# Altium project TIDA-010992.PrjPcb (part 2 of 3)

## Sheet TIDA-010992_04_BOOT_SoC power_CLK.SchDoc
size 431 x 279 mm; Date: Not shown in title block; ApprovedBy: Not shown in title block; CheckedBy: Not shown in title block; Author: Not shown in title block; CompanyName: Not shown in title block; Engineer: Not shown in title block; Organization: Not shown in title block; Address1: Not shown in title block; Address2: Not shown in title block; Address3: Not shown in title block; Address4: Not shown in title block; DocumentNumber: 4; Revision: Use project parameter SCH_Rev; SheetNumber: 4; SheetTotal: 13; PageSetup: Record=PageOptions¦CenterHorizontal=True¦CenterVertical=True¦PrintScale=1.00¦XCorrection=1.00¦YCorrection=1.00¦PrintKind=0¦BorderSize=5000000¦LeftOffset=0¦BottomOffset=0¦Orientation=2¦PaperLength=1000¦PaperWidth=1000¦Scale=100¦PaperSource=15¦PrintQuality=600¦MediaType=1¦DitherType=10¦PaperKind=Letter¦PrintScaleMode=1

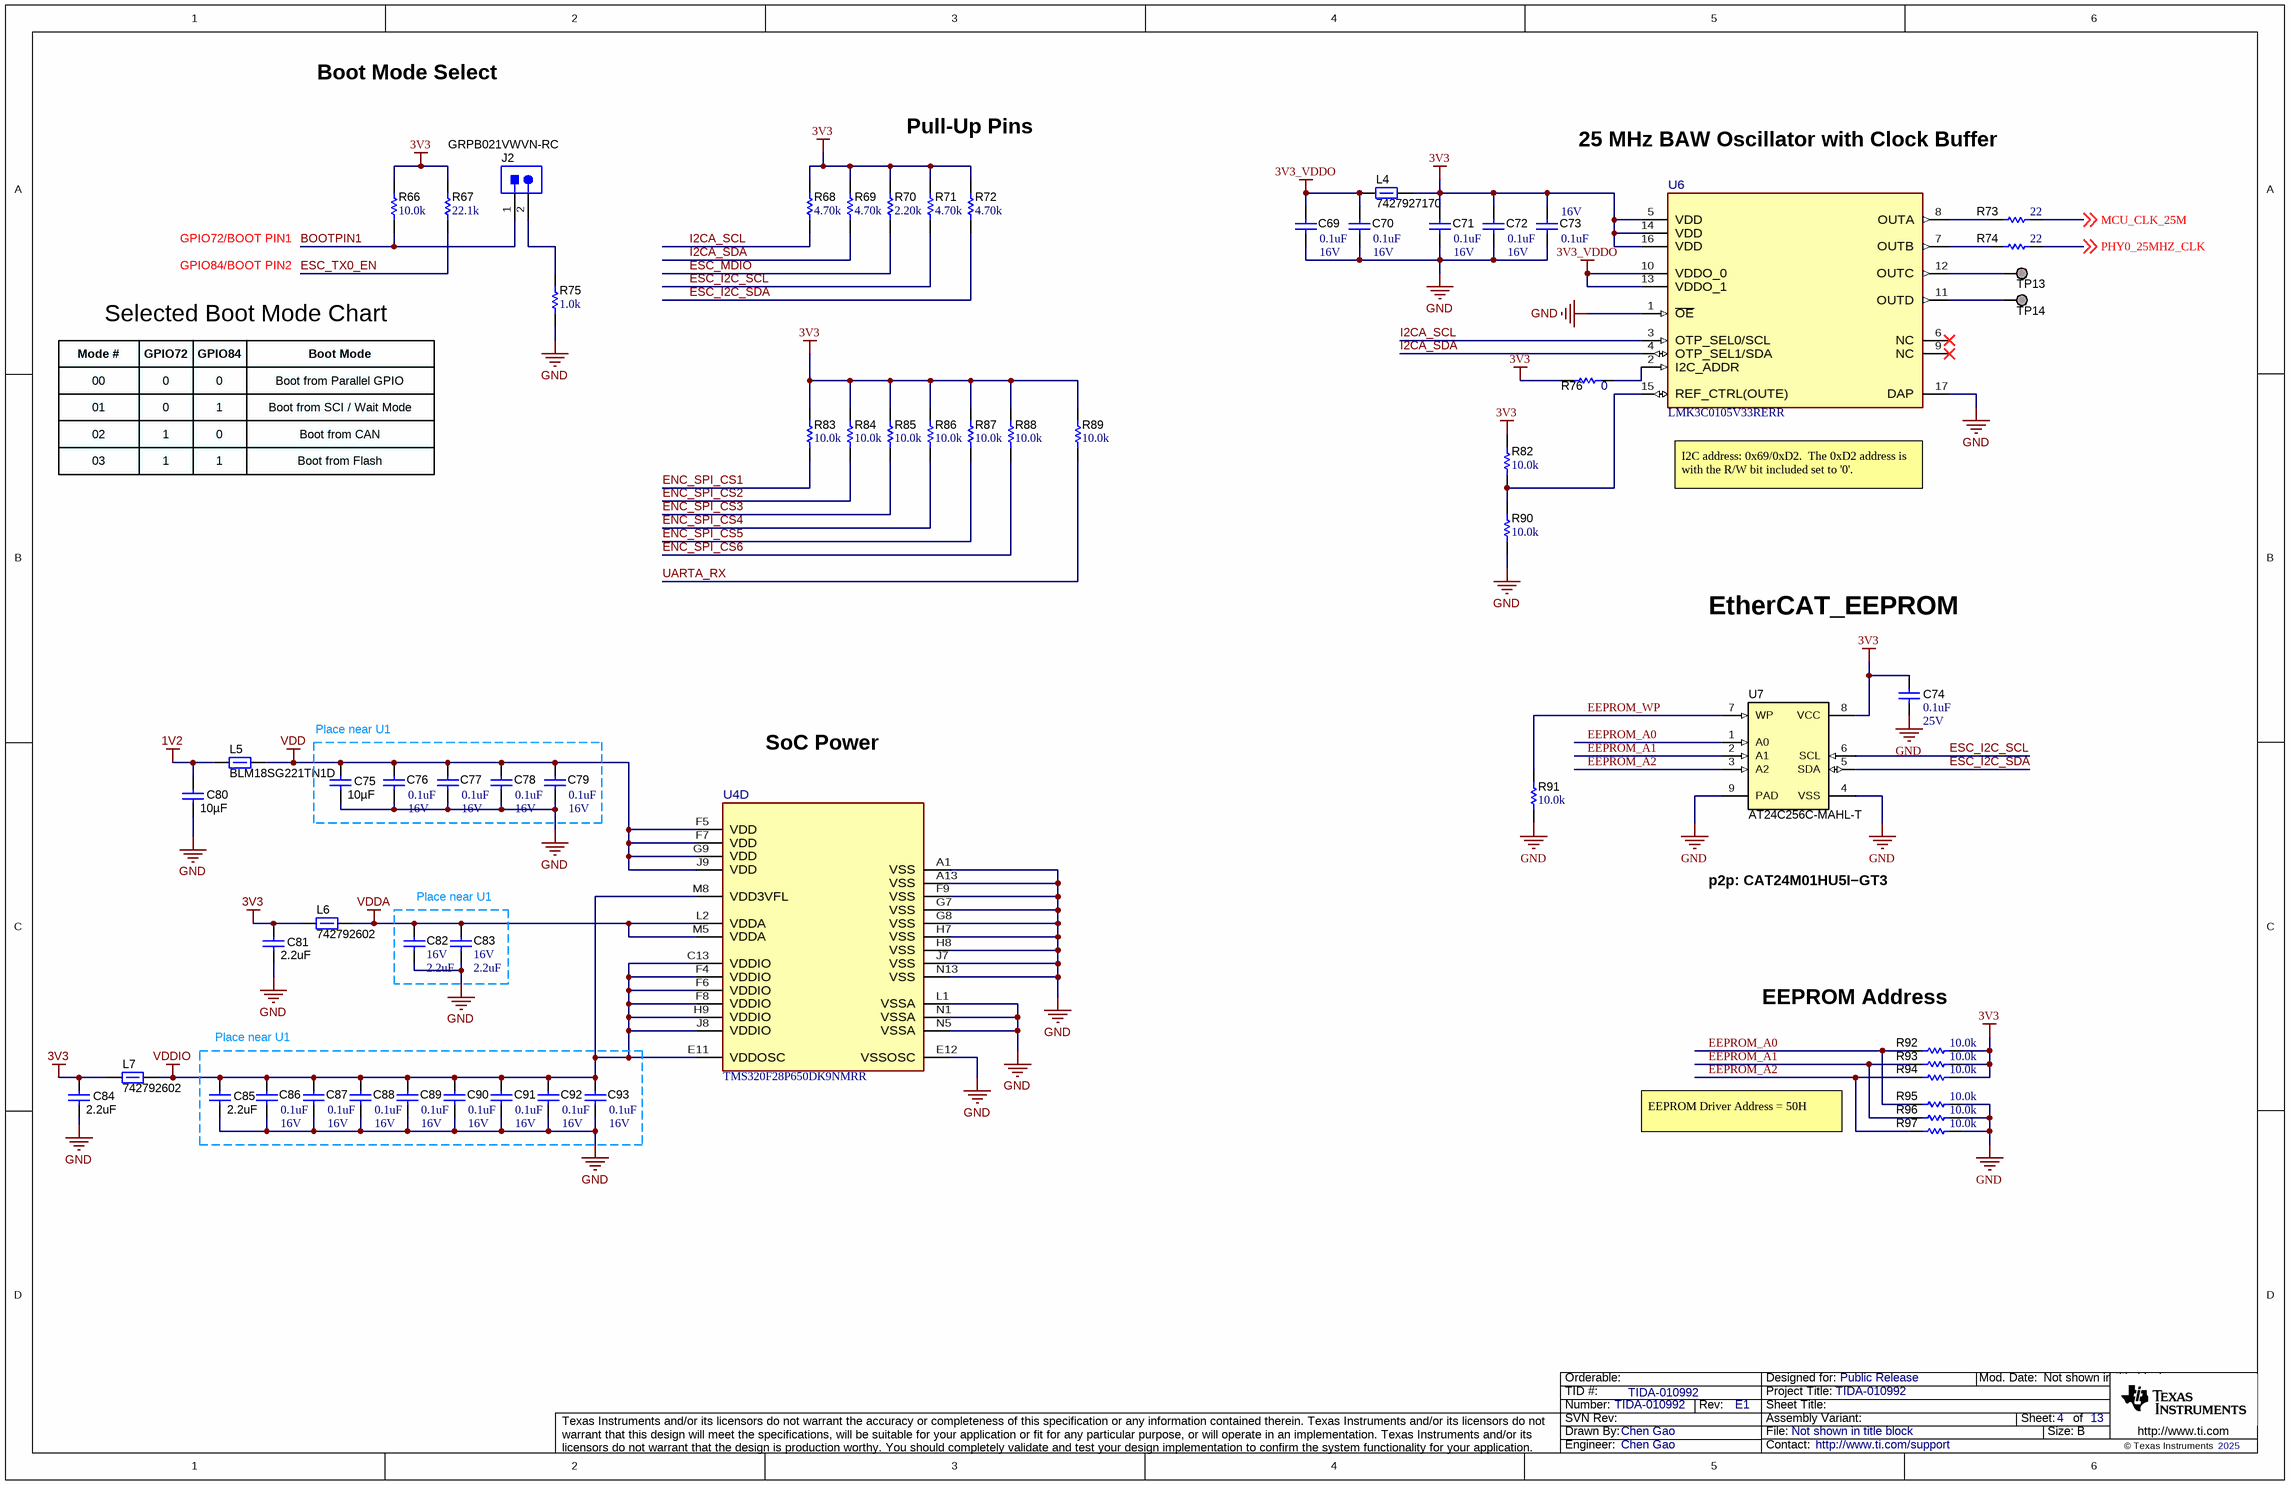
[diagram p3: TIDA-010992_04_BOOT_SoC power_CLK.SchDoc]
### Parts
C69  VDC_V: 16V  ValueDisplayed: 0.1uF  [0201]  (hidden comment: GRM033Z71C104KE14D)
C70  VDC_V: 16V  ValueDisplayed: 0.1uF  [0201]  (hidden comment: GRM033Z71C104KE14D)
C71  VDC_V: 16V  ValueDisplayed: 0.1uF  [0201]  (hidden comment: GRM033Z71C104KE14D)
C72  VDC_V: 16V  ValueDisplayed: 0.1uF  [0201]  (hidden comment: GRM033Z71C104KE14D)
C73  VDC_V: 16V  ValueDisplayed: 0.1uF  [0201]  (hidden comment: GRM033Z71C104KE14D)
C74  Value2: 25V  ValueDisplayed: 0.1uF  [0402]  (hidden comment: GRM155R71E104KE14D)
C75  ValueDisplayed: 10µF  [0603]  (hidden comment: GRM188R61C106KAALD)
C76  VDC_V: 16V  ValueDisplayed: 0.1uF  [0201]  (hidden comment: GRM033Z71C104KE14D)
C77  VDC_V: 16V  ValueDisplayed: 0.1uF  [0201]  (hidden comment: GRM033Z71C104KE14D)
C78  VDC_V: 16V  ValueDisplayed: 0.1uF  [0201]  (hidden comment: GRM033Z71C104KE14D)
C79  VDC_V: 16V  ValueDisplayed: 0.1uF  [0201]  (hidden comment: GRM033Z71C104KE14D)
C80  ValueDisplayed: 10µF  [0603]  (hidden comment: GRM188R61C106KAALD)
C81  ValueDisplayed: 2.2uF  [0603]  (hidden comment: 885012106018)
C82  VDC_V: 16V  ValueDisplayed: 2.2uF  [0402]  (hidden comment: GRM155R61C225KE11D)
C83  VDC_V: 16V  ValueDisplayed: 2.2uF  [0402]  (hidden comment: GRM155R61C225KE11D)
C84  ValueDisplayed: 2.2uF  [0603]  (hidden comment: 885012106018)
C85  ValueDisplayed: 2.2uF  [0603]  (hidden comment: 885012106018)
C86  VDC_V: 16V  ValueDisplayed: 0.1uF  [0201]  (hidden comment: GRM033Z71C104KE14D)
C87  VDC_V: 16V  ValueDisplayed: 0.1uF  [0201]  (hidden comment: GRM033Z71C104KE14D)
C88  VDC_V: 16V  ValueDisplayed: 0.1uF  [0201]  (hidden comment: GRM033Z71C104KE14D)
C89  VDC_V: 16V  ValueDisplayed: 0.1uF  [0201]  (hidden comment: GRM033Z71C104KE14D)
C90  VDC_V: 16V  ValueDisplayed: 0.1uF  [0201]  (hidden comment: GRM033Z71C104KE14D)
C91  VDC_V: 16V  ValueDisplayed: 0.1uF  [0201]  (hidden comment: GRM033Z71C104KE14D)
C92  VDC_V: 16V  ValueDisplayed: 0.1uF  [0201]  (hidden comment: GRM033Z71C104KE14D)
C93  VDC_V: 16V  ValueDisplayed: 0.1uF  [0201]  (hidden comment: GRM033Z71C104KE14D)
J2  GRPB021VWVN-RC  [Sullins_GRPB021VWVN-RC]
L4  7427927170  [0402]
L5  BLM18SG221TN1D  [0603]
L6  742792602  [0603]
L7  742792602  [0603]
R66  ValueDisplayed: 10.0k  [0402]  (hidden comment: ERJ-2RKF1002X)
R67  ValueDisplayed: 22.1k  [0402]  (hidden comment: CRCW040222K1FKED)
R68  ValueDisplayed: 4.70k  [0201]  (hidden comment: RC0201FR-7D4K7L)
R69  ValueDisplayed: 4.70k  [0201]  (hidden comment: RC0201FR-7D4K7L)
R70  ValueDisplayed: 2.20k  [0201]  (hidden comment: RC0201FR-072K2L)
R71  ValueDisplayed: 4.70k  [0201]  (hidden comment: RC0201FR-7D4K7L)
R72  ValueDisplayed: 4.70k  [0201]  (hidden comment: RC0201FR-7D4K7L)
R73  ValueDisplayed: 22  [0402L]  (hidden comment: CRCW040222R0JNED)
R74  ValueDisplayed: 22  [0402L]  (hidden comment: CRCW040222R0JNED)
R75  ValueDisplayed: 1.0k  [0402]  (hidden comment: ERJ-2GEJ102X)
R76  ValueDisplayed: 0  [0402]  (hidden comment: CRCW04020000Z0EDHP)
R82  ValueDisplayed: 10.0k  [0201]  (hidden comment: RC0201FS-7D10KL)
R83  ValueDisplayed: 10.0k  [0201]  (hidden comment: RC0201FS-7D10KL)
R84  ValueDisplayed: 10.0k  [0201]  (hidden comment: RC0201FS-7D10KL)
R85  ValueDisplayed: 10.0k  [0201]  (hidden comment: RC0201FS-7D10KL)
R86  ValueDisplayed: 10.0k  [0201]  (hidden comment: RC0201FS-7D10KL)
R87  ValueDisplayed: 10.0k  [0201]  (hidden comment: RC0201FS-7D10KL)
R88  ValueDisplayed: 10.0k  [0201]  (hidden comment: RC0201FS-7D10KL)
R89  ValueDisplayed: 10.0k  [0201]  (hidden comment: RC0201FS-7D10KL)
R90  ValueDisplayed: 10.0k  [0201]  (hidden comment: RC0201FS-7D10KL)
R91  ValueDisplayed: 10.0k  [0402]  (hidden comment: ERJ-2RKF1002X)
R92  ValueDisplayed: 10.0k  [0402]  (hidden comment: ERJ-2RKF1002X)
R93  ValueDisplayed: 10.0k  [0402]  (hidden comment: ERJ-2RKF1002X)
R94  ValueDisplayed: 10.0k  [0402]  (hidden comment: ERJ-2RKF1002X)
R95  ValueDisplayed: 10.0k  [0402]  (hidden comment: ERJ-2RKF1002X)
R96  ValueDisplayed: 10.0k  [0402]  (hidden comment: ERJ-2RKF1002X)
R97  ValueDisplayed: 10.0k  [0402]  (hidden comment: ERJ-2RKF1002X)
TP13  TP_SM_1MM  [TP_SM_1MM]  (value not drawn)  (no BOM)
TP14  TP_SM_1MM  [TP_SM_1MM]  (value not drawn)  (no BOM)
U4  TMS320F28P650DK9NMRR  [NMR0169A-MFG]  (part D of 4)
U6  LMK3C0105V33RERR  [RER0016A-MFG]
U7  AT24C256C-MAHL-T  [8MA2]

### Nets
1V2: C80.1 L5.1
3V3: C71.1 C72.1 C73.1 C74.2 C81.1 C84.1 L4.1 L6.1 L7.1 R66.1 R67.2 R68.2 R69.2 R70.2 R71.2 R72.2 R76.1 R82.2 R83.2 R84.2 R85.2 R86.2 R87.2 R88.2 R89.2 R92.1 R93.1 R94.1 U6.5(VDD) U6.14(VDD) U6.16(VDD) U7.8(VCC)
3V3_VDDO: C69.1 C70.1 L4.2 U6.10(VDDO_0) U6.13(VDDO_1)
GND: C69.2 C70.2 C71.2 C72.2 C73.2 C74.1 C75.2 C76.2 C77.2 C78.2 C79.2 C80.2 C81.2 C82.2 C83.2 C84.2 C85.2 C86.2 C87.2 C88.2 C89.2 C90.2 C91.2 C92.2 C93.2 R75.1 R90.1 R91.2 R95.1 R96.1 R97.1 U4.A1(VSS) U4.A13(VSS) U4.E12(VSSOSC) U4.F9(VSS) U4.G7(VSS) U4.G8(VSS) U4.H7(VSS) U4.H8(VSS) U4.J7(VSS) U4.L1(VSSA) U4.N1(VSSA) U4.N5(VSSA) U4.N13(VSS) U6.1(~{OE}) U6.17(DAP) U7.4(VSS) U7.9(PAD)
VDD: C75.1 C76.1 C77.1 C78.1 C79.1 L5.2 U4.F5(VDD) U4.F7(VDD) U4.G9(VDD) U4.J9(VDD)
VDDA: C82.1 C83.1 L6.2 U4.L2(VDDA) U4.M5(VDDA)
VDDIO: C85.1 C86.1 C87.1 C88.1 C89.1 C90.1 C91.1 C92.1 C93.1 L7.2 U4.C13(VDDIO) U4.E11(VDDOSC) U4.F4(VDDIO) U4.F6(VDDIO) U4.F8(VDDIO) U4.H9(VDDIO) U4.J8(VDDIO) U4.M8(VDD3VFL)
BOOTPIN1: J2.1 R66.2
EEPROM_A0: R92.2 R95.2 U7.1(A0)
EEPROM_A1: R93.2 R96.2 U7.2(A1)
EEPROM_A2: R94.2 R97.2 U7.3(A2)
EEPROM_WP: R91.1 U7.7(WP)
ENC_SPI_CS1: R83.1
ENC_SPI_CS2: R84.1
ENC_SPI_CS3: R85.1
ENC_SPI_CS4: R86.1
ENC_SPI_CS5: R87.1
ENC_SPI_CS6: R88.1
ESC_I2C_SCL: R71.1 U7.6(SCL)
ESC_I2C_SDA: R72.1 U7.5(SDA)
ESC_MDIO: R70.1
ESC_TX0_EN: R67.1
I2CA_SCL: R68.1 U6.3(OTP_SEL0/SCL)
I2CA_SDA: R69.1 U6.4(OTP_SEL1/SDA)
MCU_CLK_25M: R73.2 ; off-sheet MCU_CLK_25M
PHY0_25MHZ_CLK: R74.2 ; off-sheet PHY0_25MHZ_CLK
UARTA_RX: R89.1
NetJ2_2: J2.2 R75.2
NetR73_1: R73.1 U6.8(OUTA)
NetR74_1: R74.1 U6.7(OUTB)
NetR76_2: R76.2 U6.2(I2C_ADDR)
NetR82_1: R82.1 R90.2 U6.15(REF_CTRL(OUTE))
NetTP13_1: TP13.1 U6.12(OUTC)
NetTP14_1: TP14.1 U6.11(OUTD)

Not connected (* = marked no-connect by the designer): U6 6(NC)* 9(NC)*

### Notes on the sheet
- Boot Mode Select
- Pull-Up Pins
- 25 MHz BAW Oscillator with Clock Buffer
- GPIO72/BOOT PIN1
- GPIO84/BOOT PIN2
- Mode #
- GPIO72
- GPIO84
- Selected Boot Mode Chart
- Boot Mode
- 00
- 01
- 02
- 0
- 1
- Boot from Parallel GPIO
- Boot from SCI / Wait Mode
- Boot from CAN
- 03
- Boot from Flash
- (near U6) I2C address: 0x69/0xD2.  The 0xD2 address is with the R/W bit included set to '0'.
- EtherCAT_EEPROM
- Place near U1
- SoC Power
- p2p: CAT24M01HU5I−GT3
- EEPROM Address
- EEPROM Driver Address = 50H

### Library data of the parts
C69-C73 C76-C79 C86-C93 = CMP-0064970-1: CAP, CERM, 0.1 uF, 16 V,+/- 10%, X7R, 0201; Manufacturer: MuRata; TaMin_C: -55°C; Polarized: N; SizeAreaWB_mm2: 2.08; Value1: Unknown; U/M: EA; Value: 0.1uF; TaMax_C: 125°C; SizeZ_mm: 0.26; SizeX_mm: 0.6; SizeY_mm: 0.3; SizeArea_mm2: 0.18; Cap_F: 100nF; AEC Category: Q200
C74 = CMP-0006659-2: CAP, CERM, 0.1 uF, 25 V, +/- 10%, X7R, 0402; Manufacturer: MuRata; TaMin_C: -55°C; Polarized: N; SizeAreaWB_mm2: 3; U/M: EA; Value: 0.1uF; TaMax_C: 125°C; SizeZ_mm: 0.6; SizeX_mm: 1; SizeY_mm: 0.5; Cap_F: 100nF; AEC Category: Q200; Value1: Unknown
C75 C80 = CMP-0086225-1: CAP, CERM, 10 µF, 16 V,+/- 10%, X5R, 0603; Manufacturer: MuRata; SizeZ_mm: 1; SizeX_mm: 1.6; SizeArea_mm2: 1.28; VDC_V: 16V; U/M: EA; AEC Category: Q200; SizeY_mm: 0.8; Polarized: N; TaMax_C: 85°C; Value: 10uF; SizeAreaWB_mm2: 4.68; TaMin_C: -55°C
C81 C84 C85 = CMP-0006825-5: CAP, CERM, 2.2 uF, 16 V, +/- 20%, X5R, 0603; Manufacturer: Wurth Elektronik; TaMin_C: -55°C; Polarized: N; SizeAreaWB_mm2: 4.68; Value1: Unknown; U/M: EA; Value: 2.2uF; TaMax_C: 85°C; SizeZ_mm: 1; SizeX_mm: 1.6; SizeY_mm: 0.8; Value2: 16V; SizeArea_mm2: 1.28; Cap_F: 2.2µF; AEC Category: Q200
C82 C83 = CMP-0006594-2: CAP, CERM, 2.2 uF, 16 V, +/- 10%, X5R, 0402; Manufacturer: MuRata; TaMin_C: -55°C; Polarized: N; SizeAreaWB_mm2: 3; Value1: Unknown; U/M: EA; Value: 2.2uF; TaMax_C: 85°C; SizeZ_mm: 0.6; SizeX_mm: 1; SizeY_mm: 0.5; Cap_F: 2.2µF; AEC Category: Q200
J2 = CMP-0054555-1: Header, 50mil, 2x1, Gold, TH; Manufacturer: Sullins Connector Solutions; CNHeader: TRUE; Green_Lifecycle: Not Set; Green_REACh: Incomplete; CT: FALSE
L4 = CMP-0003226-1: Ferrite Bead, 75 ohm @ 100 MHz, 0.3 A, 0402; Manufacturer: Wurth Elektronik; Ztyp@1GHz_Ohm: 541.253; ZTyp@100MHz_Ohm: 75; SizeAreaWB_mm2: 3; DCR_ohm: 0.31; Value1: 0.31 ohm; Value: 75 ohm; Imax_A: 300mA; SizeZ_mm: 0.6; SizeX_mm: 1; SizeY_mm: 0.5; Value2: 0.3A
L5 = CMP-0003353-2: Ferrite Bead, 220 ohm @ 100 MHz, 2.5 A, 0603; Manufacturer: MuRata; ZTyp@100MHz_Ohm: 220; SizeAreaWB_mm2: 4.68; DCR_ohm: 40m; Value1: 0.04 ohm; Value: 220 ohm; Imax_A: 2.5A; SizeZ_mm: 1; SizeX_mm: 1.6; SizeY_mm: 0.8; SizeArea_mm2: 1.28
L6 L7 = CMP-0003173-2: Ferrite Bead, 60 ohm @ 100 MHz, 3 A, 0603; Manufacturer: Wurth Elektronik; Ztyp@1GHz_Ohm: 110.436; ZTyp@100MHz_Ohm: 60; SizeAreaWB_mm2: 4.68; DCR_ohm: 40m; Value1: 0.04 ohm; Value: 60 ohm; Imax_A: 3A; SizeZ_mm: 1; SizeX_mm: 1.6; SizeY_mm: 0.8; SizeArea_mm2: 1.28
R66 R91-R97 = CMP-0026658-1: RES, 10.0 k, 1%, 0.1 W, 0402; Manufacturer: Panasonic; Power_W: 100mW; TempCo: 100 ppm/C; Value_Code: 10k0; U/M: EA; Value: 10.0k; EIA_Code: E96; Res_ohm: 10k; SizeX_mm: 1; SizeY_mm: 0.5; SizeZ_mm: 0.6; Value2: 0.1W; VDC_V: 50V; AEC Category: Q200
R67 = CMP-0026178-2: RES, 22.1 k, 1%, 0.063 W, AEC-Q200 Grade 0, 0402; Manufacturer: Vishay-Dale; Power_W: 63mW; TempCo: 100 ppm/C; Value_Code: 22k1; Value: 22.1k; EIA_Code: E96; SizeX_mm: 1; SizeY_mm: 0.5; SizeZ_mm: 0.6; Value2: 0.063W; AEC Qualified: Y; VDC_V: 50V; AEC Category: Q200; AEC Grade: 0
R68 R69 R71 R72 = CMP-0028031-1: RES, 4.70 k, 1%, 0.05 W, 0201; Manufacturer: Yageo America; Power_W: 50mW; TempCo: 200 ppm/C; Value_Code: 4k70; U/M: EA; Value: 4.70k; Res_ohm: 4.7k; SizeX_mm: 0.6; SizeY_mm: 0.3; SizeZ_mm: 0.26; Value2: 0.05W; SizeArea_mm2: 0.18; AEC Qualified: N; VDC_V: 25V; AEC Category: Q200
R70 = CMP-0027558-1: RES, 2.20 k, 1%, 0.05 W, 0201; Manufacturer: Yageo America; Power_W: 50mW; TempCo: 200 ppm/C; Value_Code: 2k20; U/M: EA; Value: 2.20k; Res_ohm: 2.2k; SizeX_mm: 0.6; SizeY_mm: 0.3; SizeZ_mm: 0.26; Value2: 0.05W; SizeArea_mm2: 0.18; AEC Qualified: N; VDC_V: 25V; AEC Category: Q200
R73 R74 = CMP-0026880-3: RES, 22, 5%, 0.063 W, AEC-Q200 Grade 0, 0402; Manufacturer: Vishay-Dale; Power_W: 63mW; TempCo: 200 ppm/C; Value_Code: 22R0; Value: 22; EIA_Code: E24; SizeX_mm: 1; SizeY_mm: 0.5; SizeZ_mm: 0.6; Value2: 0.063W; AEC Qualified: Y; VDC_V: 50V; AEC Category: Q200; AEC Grade: 0
R75 = CMP-0078193-1: RES, 1.0 k, 5%, 0.1 W, AEC-Q200 Grade 0, 0402; Manufacturer: Panasonic; Value_Code: 1k00; SizeArea_mm2: 0.5; AEC Qualified: Y; AEC Category: Q200; Res_ohm: 1k; Value: 1.0k; SizeZ_mm: 0.6; Green_REACh: Passed; EIA_Code: E24; TempCo: 200 ppm/C; AEC Grade: 0; Power_W: 100mW; VDC_V: 50V; Value2: 0.1W; Green_Lifecycle: Active; U/M: EA; SizeX_mm: 1
R76 = CMP-0081856-1: RES, 0, 0%, 0.2 W, AEC-Q200 Grade 0, 0402; Manufacturer: Vishay-Dale; SizeAreaWB_mm2: 3; SizeArea_mm2: 0.5; AEC Qualified: Y; AEC Category: Q200; Value: 0; SizeZ_mm: 0.6; Power_W: 200mW; VDC_V: 50V; Value2: 0.2W; SizeX_mm: 1
R82-R90 = CMP-0028071-1: RES, 10.0 k, 1%, 0.05 W, 0201; Manufacturer: Yageo America; Power_W: 50mW; TempCo: 200 ppm/C; Value_Code: 10k0; U/M: EA; Value: 10.0k; EIA_Code: E96; Res_ohm: 10k; SizeX_mm: 0.6; SizeY_mm: 0.3; SizeZ_mm: 0.26; Value2: 0.05W; SizeArea_mm2: 0.18; AEC Qualified: N; VDC_V: 25V; AEC Category: Q200
TP13 TP14 = CMP-0003825-1: 1mm Test Point, SMT; Manufacturer: Any
U4 = CMP-0098413-1: Real-Time Microcontroller, NFBGA169; Manufacturer: Texas Instruments; SizeZ_mm: 1mm; AEC Qualified: No; Core Architecture: C28x; Data Bus Width: 32bits; Frequency_Fixed: 200MHz; Interface: I2C,SPI,UART,CAN,USB,LIN,SCI,Ethernet; Max Supply Voltage: 3.63V; Memory Size: 1.28MBytes; Memory Type: FLASH; Min Supply Voltage: 1.14V; Number Of A/D Converters: 3; Number Of Adc Channels: 34; Number Of Cores: 2; Number Of Ethernet Channels: 1; Number Of I/Os: 119; Number Of Pwm Channels: 36; Number Of Spi Channels: 4; Number Of Timers/Counters: 6; Ram Size: 248KBytes; Standoff Height: 0.19mm; TaMax_C: +125°C; TaMin_C: -40°C; TJmax_C: +155°C
U6 = CMP-0126121-1: 5 output reference-less clock generator with bulk acoustic wave (BAW) 16-TQFN -40 to 85; Manufacturer: Texas Instruments; SizeZ_mm: 1.2mm; AEC Qualified: No; Interface: I2C; Max Frequency: 200MHz; Max Supply Voltage: 3.465V; Min Supply Voltage: 1.71V; Number Of Outputs: 5; Standoff Height: 0mm; TaMax_C: +85°C; TaMin_C: -40°C; TJmax_C: +105°C
U7 = CMP-0005119-3: I2C-Compatible (2-Wire) Serial EEPROM 256 kb, 8UDFN; Manufacturer: Atmel

## Sheet TIDA-010992_05_ETH_Conn.SchDoc
size 431 x 279 mm; Date: Not shown in title block; ApprovedBy: Not shown in title block; CheckedBy: Not shown in title block; Author: Not shown in title block; CompanyName: Not shown in title block; Engineer: Not shown in title block; Organization: Not shown in title block; Address1: Not shown in title block; Address2: Not shown in title block; Address3: Not shown in title block; Address4: Not shown in title block; DocumentNumber: 5; Revision: Use project parameter SCH_Rev; SheetNumber: 5; SheetTotal: 13; PageSetup: Record=PageOptions¦CenterHorizontal=True¦CenterVertical=True¦PrintScale=1.00¦XCorrection=1.00¦YCorrection=1.00¦PrintKind=0¦BorderSize=5000000¦LeftOffset=0¦BottomOffset=0¦Orientation=2¦PaperLength=1000¦PaperWidth=1000¦Scale=100¦PaperSource=15¦PrintQuality=600¦MediaType=1¦DitherType=10¦PaperKind=Letter¦PrintScaleMode=1

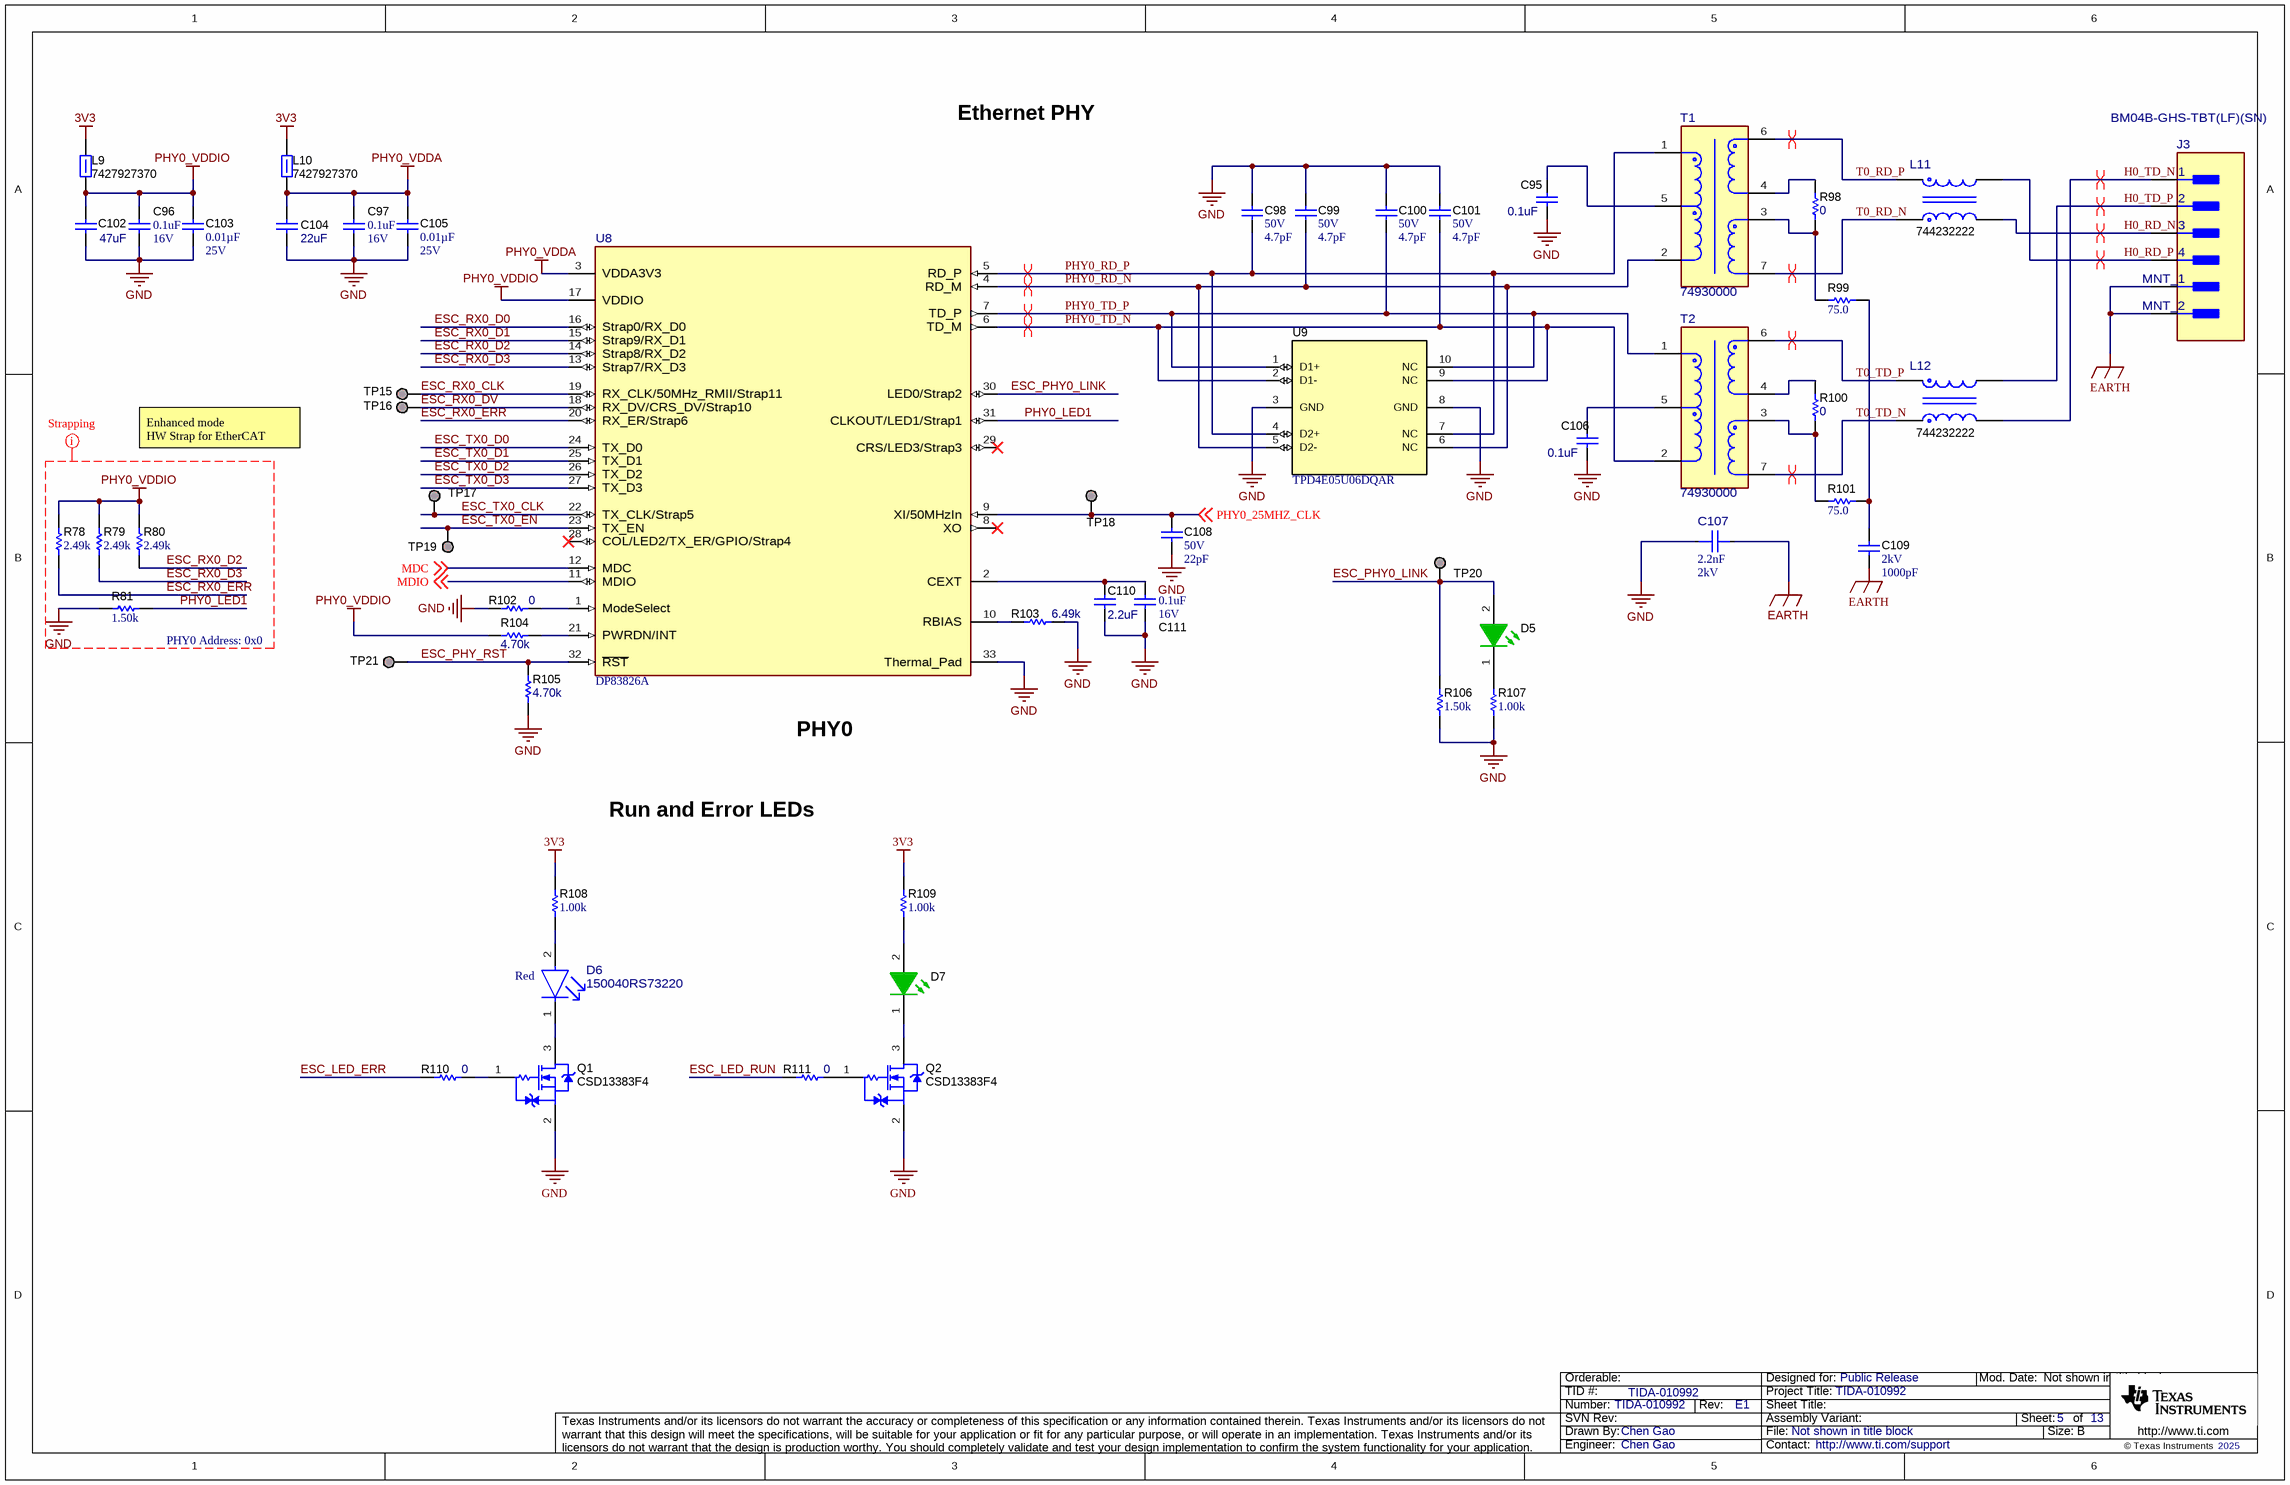
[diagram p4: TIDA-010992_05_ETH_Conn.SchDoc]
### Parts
C95  ValueDisplayed: 0.1uF  [0402]  (hidden comment: 885012205037)
C96  VDC_V: 16V  ValueDisplayed: 0.1uF  [0201]  (hidden comment: GRM033Z71C104KE14D)
C97  VDC_V: 16V  ValueDisplayed: 0.1uF  [0201]  (hidden comment: GRM033Z71C104KE14D)
C98  VDC_V: 50V  ValueDisplayed: 4.7pF  [0201_033]  (hidden comment: GRM0335C1H4R7BA01D)
C99  VDC_V: 50V  ValueDisplayed: 4.7pF  [0201_033]  (hidden comment: GRM0335C1H4R7BA01D)
C100  VDC_V: 50V  ValueDisplayed: 4.7pF  [0201_033]  (hidden comment: GRM0335C1H4R7BA01D)
C101  VDC_V: 50V  ValueDisplayed: 4.7pF  [0201_033]  (hidden comment: GRM0335C1H4R7BA01D)
C102  ValueDisplayed: 47uF  [0603]  (hidden comment: GRM188R60J476ME15D)
C103  ValueDisplayed: 0.01µF  VDC_V: 25V  [0201]  (hidden comment: GRM033R71E103KE14D)
C104  ValueDisplayed: 22uF  [0603]  (hidden comment: GRM188R61A226ME15D)
C105  ValueDisplayed: 0.01µF  VDC_V: 25V  [0201]  (hidden comment: GRM033R71E103KE14D)
C106  ValueDisplayed: 0.1uF  [0402]  (hidden comment: 885012205037)
C107  ValueDisplayed: 2.2nF  VDC_V: 2kV  [FP-1206Y2K00222KET_1206-MFG]  (hidden comment: 1206Y2K00222KET)
C108  VDC_V: 50V  ValueDisplayed: 22pF  [0402]  (hidden comment: CL05C220JB5NNNC)
C109  VDC_V: 2kV  ValueDisplayed: 1000pF  [1206_180]  (hidden comment: C1206C102KGRACAUTO)
C110  ValueDisplayed: 2.2uF  [0402_065]  (hidden comment: C1005X5R1V225K050BC)
C111  VDC_V: 16V  ValueDisplayed: 0.1uF  [0201]  (hidden comment: GRM033Z71C104KE14D)
D5  150040GS73240  [WL-SMCC_0402_Green]  (value not drawn)
D6  150040RS73220  Color: Red  [FP-150040RS73220_0402-MFG]
D7  150040GS73240  [WL-SMCC_0402_Green]  (value not drawn)
J3  BM04B-GHS-TBT(LF)(SN)  [FP-BM04B-GHS-TBT(LF)(SN)_HDR4-MFG]
L9  7427927370  [0402]
L10  7427927370  [0402]
L11  744232222  [FP-744232222_SMT4_3MM2_1MM6-MFG]
L12  744232222  [FP-744232222_SMT4_3MM2_1MM6-MFG]
Q1  CSD13383F4  [YJC0003A]
Q2  CSD13383F4  [YJC0003A]
R78  ValueDisplayed: 2.49k  [0201]  (hidden comment: RC0201FR-072K49L)
R79  ValueDisplayed: 2.49k  [0201]  (hidden comment: RC0201FR-072K49L)
R80  ValueDisplayed: 2.49k  [0201]  (hidden comment: RC0201FR-072K49L)
R81  ValueDisplayed: 1.50k  [0201]  (hidden comment: RK73H1HTTC1501F)
R98  ValueDisplayed: 0  [0402]  (hidden comment: CRCW04020000Z0EDHP)
R99  ValueDisplayed: 75.0  [0402]  (hidden comment: CRCW040275R0FKED)
R100  ValueDisplayed: 0  [0402]  (hidden comment: CRCW04020000Z0EDHP)
R101  ValueDisplayed: 75.0  [0402]  (hidden comment: CRCW040275R0FKED)
R102  ValueDisplayed: 0  [0402]  (hidden comment: CRCW04020000Z0EDHP)
R103  ValueDisplayed: 6.49k  [0402]  (hidden comment: CRCW04026K49FKED)
R104  ValueDisplayed: 4.70k  [0402]  (hidden comment: CRG0402F4K7)
R105  ValueDisplayed: 4.70k  [0402]  (hidden comment: CRG0402F4K7)
R106  ValueDisplayed: 1.50k  [0402]  (hidden comment: CRCW04021K50FKED)
R107  ValueDisplayed: 1.00k  [0402]  (hidden comment: CRCW04021K00FKED)
R108  ValueDisplayed: 1.00k  [0402]  (hidden comment: RC0402FR-071KL)
R109  ValueDisplayed: 1.00k  [0402]  (hidden comment: RC0402FR-071KL)
R110  ValueDisplayed: 0  [0402]  (hidden comment: CRCW04020000Z0EDHP)
R111  ValueDisplayed: 0  [0402]  (hidden comment: CRCW04020000Z0EDHP)
T1  74930000  [FP-74930000_SMT_4MM7_3MM22-MFG]
T2  74930000  [FP-74930000_SMT_4MM7_3MM22-MFG]
TP15  TESTPOINT  [TP_25MIL-SMT]  (value not drawn)  (no BOM)
TP16  TESTPOINT  [TP_25MIL-SMT]  (value not drawn)  (no BOM)
TP17  TESTPOINT  [TP_25MIL-SMT]  (value not drawn)  (no BOM)
TP18  TP_SM_1MM  [TP_SM_1MM]  (value not drawn)  (no BOM)
TP19  TESTPOINT  [TP_25MIL-SMT]  (value not drawn)  (no BOM)
TP20  TESTPOINT  [TP_25MIL-SMT]  (value not drawn)  (no BOM)
TP21  TESTPOINT  [TP_25MIL-SMT]  (value not drawn)  (no BOM)
U8  DP83826A  [RHB0032M-MFG]
U9  TPD4E05U06DQAR  [DQA0010A]

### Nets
3V3: L9.2 L10.2 R108.2 R109.2
EARTH: C107.2 C109.2 J3.5(MNT_1) J3.6(MNT_2)
GND: C95.2 C96.2 C97.2 C98.1 C99.1 C100.1 C101.1 C102.2 C103.2 C104.2 C105.2 C106.2 C107.1 C108.2 C110.2 C111.2 Q1.2(S) Q2.2(S) R81.1 R102.1 R103.2 R105.1 R106.2 R107.1 U8.33(Thermal_Pad) U9.3(GND) U9.8(GND)
PHY0_VDDA: C97.1 C104.1 C105.1 L10.1 U8.3(VDDA3V3)
PHY0_VDDIO: C96.1 C102.1 C103.1 L9.1 R78.2 R79.2 R80.2 R104.1 U8.17(VDDIO)
ESC_LED_ERR: R110.1
ESC_LED_RUN: R111.1
ESC_PHY0_LINK: D5.2(A) R106.1 TP20.1 U8.30(LED0/Strap2)
ESC_PHY_RST: R105.2 TP21.1 U8.32(~{RST})
ESC_RX0_CLK: TP15.1 U8.19(RX_CLK/50MHz_RMII/Strap11)
ESC_RX0_D0: U8.16(Strap0/RX_D0)
ESC_RX0_D1: U8.15(Strap9/RX_D1)
ESC_RX0_D2: R80.1 U8.14(Strap8/RX_D2)
ESC_RX0_D3: R79.1 U8.13(Strap7/RX_D3)
ESC_RX0_DV: TP16.1 U8.18(RX_DV/CRS_DV/Strap10)
ESC_RX0_ERR: R78.1 U8.20(RX_ER/Strap6)
ESC_TX0_CLK: TP17.1 U8.22(TX_CLK/Strap5)
ESC_TX0_D0: U8.24(TX_D0)
ESC_TX0_D1: U8.25(TX_D1)
ESC_TX0_D2: U8.26(TX_D2)
ESC_TX0_D3: U8.27(TX_D3)
ESC_TX0_EN: TP19.1 U8.23(TX_EN)
H0_RD_N: J3.3 L11.2
H0_RD_P: J3.4 L11.3
H0_TD_N: J3.1 L12.2
H0_TD_P: J3.2 L12.3
MDC: U8.12(MDC) ; off-sheet MDC
MDIO: U8.11(MDIO) ; off-sheet MDIO
PHY0_25MHZ_CLK: C108.1 TP18.1 U8.9(XI/50MHzIn) ; off-sheet PHY0_25MHZ_CLK
PHY0_LED1: R81.2 U8.31(CLKOUT/LED1/Strap1)
PHY0_RD_N: C99.2 T1.2 U8.4(RD_M) U9.5(D2-) U9.6(NC)
PHY0_RD_P: C98.2 T1.1 U8.5(RD_P) U9.4(D2+) U9.7(NC)
PHY0_TD_N: C101.2 T2.2 U8.6(TD_M) U9.2(D1-) U9.9(NC)
PHY0_TD_P: C100.2 T2.1 U8.7(TD_P) U9.1(D1+) U9.10(NC)
T0_RD_N: L11.1 T1.7
T0_RD_P: L11.4 T1.6
T0_TD_N: L12.1 T2.7
T0_TD_P: L12.4 T2.6
NetC95_1: C95.1 T1.5
NetC106_1: C106.1 T2.5
NetC109_1: C109.1 R99.2 R101.2
NetC110_1: C110.1 C111.1 U8.2(CEXT)
NetD5_1: D5.1(K) R107.2
NetD6_1: D6.1(CATHODE) Q1.3(D)
NetD6_2: D6.2(ANODE) R108.1
NetD7_1: D7.1(K) Q2.3(D)
NetD7_2: D7.2(A) R109.1
NetQ1_1: Q1.1(G) R110.2
NetQ2_1: Q2.1(G) R111.2
NetR98_1: R98.1 R99.1 T1.3
NetR98_2: R98.2 T1.4
NetR100_1: R100.1 R101.1 T2.3
NetR100_2: R100.2 T2.4
NetR102_2: R102.2 U8.1(ModeSelect)
NetR103_1: R103.1 U8.10(RBIAS)
NetR104_2: R104.2 U8.21(PWRDN/INT)

Not connected (* = marked no-connect by the designer): U8 8(XO)* 28(COL/LED2/TX_ER/GPIO/Strap4)* 29(CRS/LED3/Strap3)*

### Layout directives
differential pair: H0_RD_N, H0_RD_P, H0_TD_N, H0_TD_P, PHY0_RD_N, PHY0_RD_P, PHY0_TD_N, PHY0_TD_P, T0_RD_N, T0_RD_P, T0_TD_N, T0_TD_P
mark named Strapping: ESC_RX0_D2, ESC_RX0_D3, ESC_RX0_ERR, GND, PHY0_LED1, PHY0_VDDIO

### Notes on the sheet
- Ethernet PHY
- Enhanced mode
  HW Strap for EtherCAT setting
- (near R81) PHY0 Address: 0x0
- PHY0
- Run and Error LEDs

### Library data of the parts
C95 C106 = CMP-0006228-2: CAP, CERM, 0.1 uF, 16 V, +/- 10%, X7R, 0402; Manufacturer: Wurth Elektronik; TaMin_C: -55°C; Polarized: N; SizeAreaWB_mm2: 3; Value1: Unknown; U/M: EA; Value: 0.1uF; TaMax_C: 125°C; SizeZ_mm: 0.6; SizeX_mm: 1; SizeY_mm: 0.5; Value2: 16V; Cap_F: 100nF; AEC Category: Q200
C96 C97 C111 = CMP-0064970-1: as C69-C73 on sheet TIDA-010992_04_BOOT_SoC power_CLK
C98-C101 = CMP-0080076-1: CAP, CERM, 4.7 pF, 50 V,+/- 3%, C0G/NP0, 0201; Manufacturer: MuRata; TaMin_C: -55°C; Polarized: N; SizeAreaWB_mm2: 2.08; U/M: EA; Value: 4.7pF; TaMax_C: 125°C; SizeZ_mm: 0.33; SizeX_mm: 0.6; SizeY_mm: 0.3; Cap_Case: 0201; SizeArea_mm2: 0.18; AEC Category: Q200
C102 = CMP-0007313-5: CAP, CERM, 47 uF, 6.3 V, +/- 20%, X5R, 0603; Manufacturer: MuRata; TaMin_C: -55°C; Polarized: N; SizeAreaWB_mm2: 4.68; Value1: Unknown; U/M: EA; Value: 47uF; TaMax_C: 85°C; SizeZ_mm: 1; SizeX_mm: 1.6; SizeY_mm: 0.8; Value2: 6.3V; SizeArea_mm2: 1.28; Cap_F: 47µF; AEC Category: Q200
C103 C105 = CMP-0860568-1: CAP, CERM, 0.01 µF, 25 V,+/- 10%, X7R, 0201; Manufacturer: MuRata; U/M: EA; TaMax_C: 125°C; SizeZ_mm: 0.26; AEC Qualified: N; TaMin_C: -55°C; SizeY_mm: 0.3; AEC Category: Q200; SizeAreaWB_mm2: 2.08; Cap_F: 10nF; SizeX_mm: 0.6; Value: 0.01uF; SizeArea_mm2: 0.18
C104 = CMP-0007324-5: CAP, CERM, 22 uF, 10 V, +/- 20%, X5R, 0603; Manufacturer: MuRata; TaMin_C: -55°C; Polarized: N; SizeAreaWB_mm2: 4.68; Value1: Unknown; U/M: EA; Value: 22uF; TaMax_C: 85°C; SizeZ_mm: 1; SizeX_mm: 1.6; SizeY_mm: 0.8; Value2: 10V; SizeArea_mm2: 1.28; Cap_F: 22µF; AEC Category: Q200
C107 = CMP-0090879-1: 2200pF ±10% 2000V (2kV) Ceramic Capacitor X7R (2R1) 1206 (3216 Metric); Manufacturer: Knowles Syfer; TempCo: 15%; AEC Grade: Grade 1; AEC Qualified: Yes; SizeZ_mm: 1.7mm; Value: 2.2nF
C108 = CMP-0085851-1: CAP, CERM, 22 pF, 50 V,+/- 5%, C0G/NP0, 0402; Manufacturer: Walsin; AEC Qualified: N; TaMax_C: 125°C; SizeX_mm: 1; Value: 22pF; SizeZ_mm: 0.6; AEC Category: Q200; TaMin_C: -55°C; SizeArea_mm2: 0.5; SizeAreaWB_mm2: 3; U/M: EA
C109 = CMP-0008579-2: CAP, CERM, 1000 pF, 2000 V, +/- 10%, X7R, AEC-Q200 Grade 1, 1206; Manufacturer: Kemet; TaMin_C: -55°C; Polarized: N; SizeAreaWB_mm2: 10.92; Value1: Unknown; U/M: EA; Value: 1000pF; TaMax_C: 125°C; SizeZ_mm: 1.8; SizeX_mm: 3.2; SizeY_mm: 1.6; Cap_Case: 1206; Value2: 2000V; SizeArea_mm2: 5.12; AEC Qualified: Y; Cap_F: 1nF; AEC Grade: 1; AEC Category: Q200
C110 = CMP-0006283-2: CAP, CERM, 2.2 uF, 35 V, +/- 10%, X5R, 0402; Manufacturer: TDK; TaMin_C: -55°C; ESR_ohm: 5.925m; Polarized: N; SizeAreaWB_mm2: 3; Value1: 0.005925 ohm; U/M: EA; Value: 2.2uF; TaMax_C: 85°C; SizeZ_mm: 0.65; SizeX_mm: 1; SizeY_mm: 0.5; Value2: 35V; Cap_F: 2.2µF; IRMS_A: 2.0559A; AEC Category: Q200
D5 D7 = CMP-0081765-2: LED, Green, SMD; Manufacturer: Wurth Elektronik; Vr_V: 5V; Io_A: 20mA; Tjmax_C: 95°C; Ir_A: 10µA; Power_TotalModule: 99mW; Value2: 3.2V; SizeArea_mm2: 0.5; SizeX_mm: 1; Value1: 0.099W; Angle: 120; Type: InGaN; SizeAreaWB_mm2: 3
D6 = CMP-0122246-1: Red 624nm LED Indication - Discrete 2V 0402 (1005 Metric); Manufacturer: Wurth; Angle: 120°; LambdaP: 632nm; Power_TotalModule: 48mW; SizeZ_mm: 0.35mm; Tjmax_C: 115°C; Vr_V: 5V; AEC Qualified: No; Forward Current: 20mA; Led Orientation: Top View; Luminous Intensity: 110mcd
J3 = CMP-0125599-1: Connector Header Surface Mount 4 position 0.049" (1.25mm); Manufacturer: JST; ContactFinish: Tin; Current_A: 1A; Row_Count: 1; Voltage_V: 50V; AEC Qualified: No; Conn Gender: Male; Conn Orientation: Vertical; SizeZ_mm: 4.05mm
L9 L10 = CMP-0003238-1: Ferrite Bead, 70 ohm @ 100 MHz, 1.2 A, 0402; Manufacturer: Wurth Elektronik; Ztyp@1GHz_Ohm: 122.92; ZTyp@100MHz_Ohm: 70; SizeAreaWB_mm2: 3; DCR_ohm: 90m; Value1: 0.09 ohm; Value: 70 ohm; Imax_A: 1.2A; SizeZ_mm: 0.6; SizeX_mm: 1; SizeY_mm: 0.5
L11 L12 = CMP-0092201-1: 2 Line Common Mode Choke Surface Mount 200mA DCR 1.2Ohm; Manufacturer: Wurth; TaMin_C: -40°C; AEC Qualified: Yes; AEC Grade: Grade 1; SizeZ_mm: 2mm; Ind_H: 2.578µH; Impedance At Frequency: 2200Ω @ 100MHz; TaMax_C: +85°C; DCR_ohm: 1.2
Q1 Q2 = CMP-0000198-1: MOSFET, N-CH, 12 V, 2.9 A, YJC0003A (PICOSTAR-3); Alternate Manufacturer: None; Manufacturer: Texas Instruments; SizeZ_mm: 0.35; ChType: N; Value2: 2 nC; Value1: 0.04; VdsMax_V: 12V; SizeX_mm: 1.035; SizeY_mm: 0.635; Vgs_V: 10V; Value: 12V; Rdson45_ohm: 44m; SizeArea_mm2: 0.657225; AEC Category: Q101; IdsMax_A: 2.9A; SizeAreaWB_mm2: 3.327225; U/M: EA; QgTyp_nC: 2
R78-R80 = CMP-0027562-1: RES, 2.49 k, 1%, 0.05 W, 0201; Manufacturer: Yageo America; Power_W: 50mW; TempCo: 200 ppm/C; Value_Code: 2k49; U/M: EA; Value: 2.49k; EIA_Code: E96; SizeX_mm: 0.6; SizeY_mm: 0.3; SizeZ_mm: 0.26; Value2: 0.05W; SizeArea_mm2: 0.18; AEC Qualified: N; VDC_V: 25V; AEC Category: Q200
R81 = CMP-0028124-1: RES, 1.50 k, 1%, 0.05 W, AEC-Q200 Grade 0, 0201; Manufacturer: KOA Speer; Power_W: 50mW; TempCo: 200 ppm/C; Value_Code: 1k50; U/M: EA; Value: 1.50k; EIA_Code: E96; Res_ohm: 1.5k; SizeX_mm: 0.6; SizeY_mm: 0.3; SizeZ_mm: 0.26; Value2: 0.05W; SizeArea_mm2: 0.18; AEC Qualified: Y; VDC_V: 25V; AEC Grade: 0; AEC Category: Q200
R98 R100 R102 R110 R111 = CMP-0081856-1: as R76 on sheet TIDA-010992_04_BOOT_SoC power_CLK
R99 R101 = CMP-0026544-2: RES, 75.0, 1%, 0.063 W, AEC-Q200 Grade 0, 0402; Manufacturer: Vishay-Dale; Power_W: 63mW; TempCo: 100 ppm/C; Value_Code: 75R0; Value: 75.0; EIA_Code: E96; Res_ohm: 75; SizeX_mm: 1; SizeY_mm: 0.5; SizeZ_mm: 0.6; Value2: 0.063W; AEC Qualified: Y; VDC_V: 50V; AEC Category: Q200; AEC Grade: 0
R103 = CMP-0026515-2: RES, 6.49 k, 1%, 0.063 W, AEC-Q200 Grade 0, 0402; Manufacturer: Vishay-Dale; Power_W: 63mW; TempCo: 100 ppm/C; Value_Code: 6k49; Value: 6.49k; EIA_Code: E96; SizeX_mm: 1; SizeY_mm: 0.5; SizeZ_mm: 0.6; Value2: 0.063W; AEC Qualified: Y; VDC_V: 50V; AEC Category: Q200; AEC Grade: 0
R104 R105 = CMP-0026631-1: RES, 4.70 k, 1%, 0.063 W, 0402; Manufacturer: TE Connectivity; Power_W: 63mW; TempCo: 100 ppm/C; Value_Code: 4k70; U/M: EA; Value: 4.70k; Res_ohm: 4.7k; SizeX_mm: 1; SizeY_mm: 0.5; SizeZ_mm: 0.6; Value2: 0.063W; AEC Qualified: N; AEC Category: Q200
R106 = CMP-0026088-3: RES, 1.50 k, 1%, 0.063 W, AEC-Q200 Grade 0, 0402; Manufacturer: Vishay-Dale; Power_W: 63mW; TempCo: 100 ppm/C; Value_Code: 1k50; Value: 1.50k; EIA_Code: E96; Res_ohm: 1.5k; SizeX_mm: 1; SizeY_mm: 0.5; SizeZ_mm: 0.6; Value2: 0.063W; AEC Qualified: Y; VDC_V: 50V; AEC Category: Q200; AEC Grade: 0
R107 = CMP-0026071-3: RES, 1.00 k, 1%, 0.063 W, AEC-Q200 Grade 0, 0402; Manufacturer: Vishay-Dale; Power_W: 63mW; TempCo: 100 ppm/C; Value_Code: 1k00; Value: 1.00k; EIA_Code: E96; Res_ohm: 1k; SizeX_mm: 1; SizeY_mm: 0.5; SizeZ_mm: 0.6; Value2: 0.063W; AEC Qualified: Y; VDC_V: 50V; AEC Category: Q200; AEC Grade: 0
R108 R109 = CMP-0026725-1: RES, 1.00 k, 1%, 0.0625 W, 0402; Manufacturer: Yageo America; Power_W: 62.5mW; TempCo: 100 ppm/C; Value_Code: 1k00; U/M: EA; Value: 1.00k; EIA_Code: E96; Res_ohm: 1k; SizeX_mm: 1; SizeY_mm: 0.5; SizeZ_mm: 0.6; AEC Qualified: N; VDC_V: 50V; AEC Category: Q200
T1 T2 = CMP-0088807-1: 350µH  Pulse Transformer 1:1 Surface Mount; Manufacturer: Wurth Electronics; Voltage_Isolation_Vrms: 1500Vrms; SizeZ_mm: 2.9mm; AEC Qualified: No; DCR_ohm: 4.5; Insertion Loss: -1dB; Return Loss: -10dB
TP15-TP17 TP19-TP21 = CMP-0078143-3: TEST POINT.  No entry in BOM.
TP18 = CMP-0003825-1: 1mm Test Point, SMT; Manufacturer: Any
U8 = CMP-0124715-2: Deterministic, Low-Latency, Low-Power, 10/100 Mbps, Industrial Ethernet PHY; Manufacturer: Texas Instruments; SizeZ_mm: 1mm; AEC Qualified: No; Data Rate: 100Mbits/s; Interface: Ethernet,Other; Max Supply Voltage: 3.6V; Min Supply Voltage: 1.62V; Number Of Channels: 1; Simplex Duplex: Full-Duplex; Standoff Height: 0mm; TaMax_C: +85°C; TaMin_C: -40°C; AEC Category: Q200; CompType: IC
U9 = CMP-0073613-3: 4-Channel Ultra-Low-Capacitance IEC ESD Protection Diode, DQA0010A (USON-10); Alternate Manufacturer: Texas Instruments; Green_Lifecycle: Active; SizeAreaWB_mm2: 7.0; Green_REACh: Passed; SizeZ_mm: 0.55; SizeX_mm: 1.0; SizeY_mm: 2.5; CompType: IC; AEC Category: Q200; AEC Qualified: N

## Sheet TIDA-010992_06_DRV_AXIS1.SchDoc
size 431 x 279 mm; Date: Not shown in title block; ApprovedBy: Not shown in title block; CheckedBy: Not shown in title block; Author: Not shown in title block; CompanyName: Not shown in title block; Engineer: Not shown in title block; Organization: Not shown in title block; Address1: Not shown in title block; Address2: Not shown in title block; Address3: Not shown in title block; Address4: Not shown in title block; DocumentNumber: 6; Revision: Use project parameter SCH_Rev; SheetNumber: 6; SheetTotal: 13; PageSetup: Record=PageOptions¦CenterHorizontal=True¦CenterVertical=True¦PrintScale=1.00¦XCorrection=1.00¦YCorrection=1.00¦PrintKind=0¦BorderSize=5000000¦LeftOffset=0¦BottomOffset=0¦Orientation=2¦PaperLength=1000¦PaperWidth=1000¦Scale=100¦PaperSource=15¦PrintQuality=600¦MediaType=1¦DitherType=10¦PaperKind=Letter¦PrintScaleMode=1

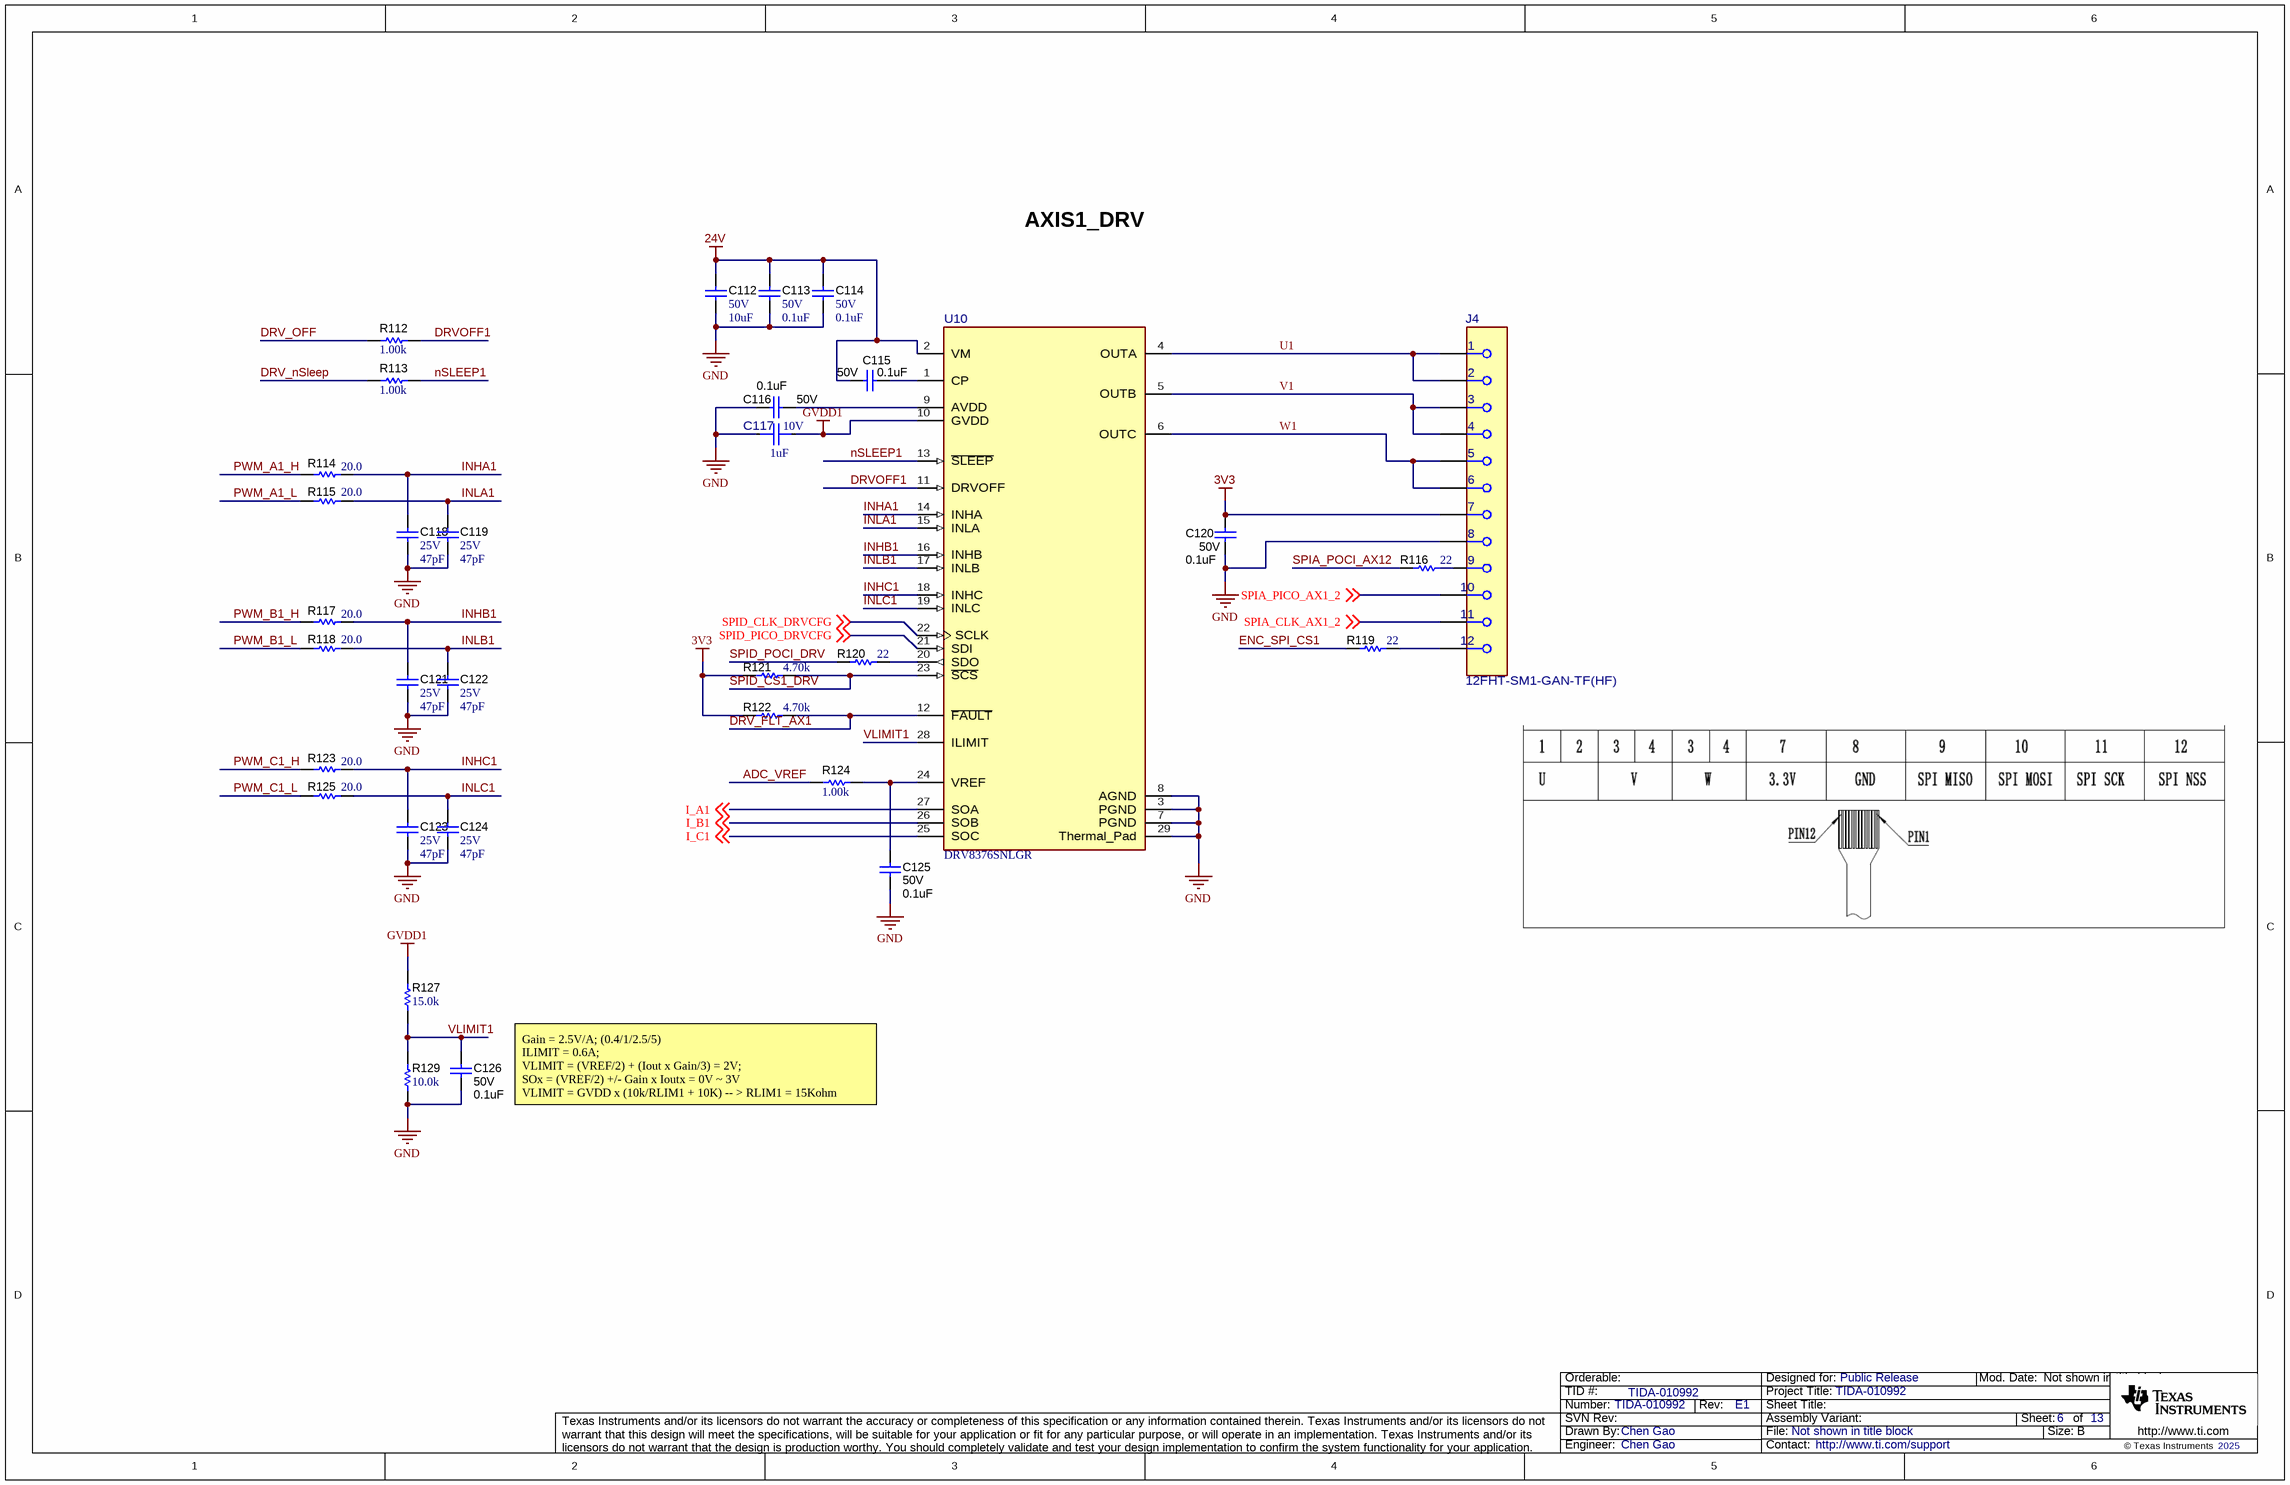
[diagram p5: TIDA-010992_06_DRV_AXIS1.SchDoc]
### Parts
C112  VDC_V: 50V  ValueDisplayed: 10uF  [1206_180]  (hidden comment: CL31B106KBHNNNE)
C113  VDC_V: 50V  ValueDisplayed: 0.1uF  [0402]  (hidden comment: C1005X7R1H104K050BE)
C114  VDC_V: 50V  ValueDisplayed: 0.1uF  [0402]  (hidden comment: C1005X7R1H104K050BE)
C115  VDC_V: 50V  ValueDisplayed: 0.1uF  [0402]  (hidden comment: CGA2B3X7R1H104M050BB)
C116  VDC_V: 50V  ValueDisplayed: 0.1uF  [0402]  (hidden comment: CGA2B3X7R1H104M050BB)
C117  VDC_V: 10V  ValueDisplayed: 1uF  [FP-GMC04X7R105K10NT_0402-MFG]  (hidden comment: GMC04X7R105K10NT)
C118  VDC_V: 25V  ValueDisplayed: 47pF  [0201_033]  (hidden comment: GRM0335C1E470JA01D)
C119  VDC_V: 25V  ValueDisplayed: 47pF  [0201_033]  (hidden comment: GRM0335C1E470JA01D)
C120  VDC_V: 50V  ValueDisplayed: 0.1uF  [0402]  (hidden comment: CGA2B3X7R1H104M050BB)
C121  VDC_V: 25V  ValueDisplayed: 47pF  [0201_033]  (hidden comment: GRM0335C1E470JA01D)
C122  VDC_V: 25V  ValueDisplayed: 47pF  [0201_033]  (hidden comment: GRM0335C1E470JA01D)
C123  VDC_V: 25V  ValueDisplayed: 47pF  [0201_033]  (hidden comment: GRM0335C1E470JA01D)
C124  VDC_V: 25V  ValueDisplayed: 47pF  [0201_033]  (hidden comment: GRM0335C1E470JA01D)
C125  VDC_V: 50V  ValueDisplayed: 0.1uF  [0402]  (hidden comment: CGA2B3X7R1H104M050BB)
C126  VDC_V: 50V  ValueDisplayed: 0.1uF  [0402]  (hidden comment: CGA2B3X7R1H104M050BB)
J4  12FHT-SM1-GAN-TF(HF)  [FP-12FHT-SM1-GAN-TF(HF)_CONN_FPC_12-MFG]
R112  ValueDisplayed: 1.00k  [0402]  (hidden comment: CRCW04021K00FKED)
R113  ValueDisplayed: 1.00k  [0402]  (hidden comment: CRCW04021K00FKED)
R114  ValueDisplayed: 20.0  [0201_033]  (hidden comment: CRCW020120R0FNED)
R115  ValueDisplayed: 20.0  [0201_033]  (hidden comment: CRCW020120R0FNED)
R116  ValueDisplayed: 22  [0201]  (hidden comment: ERJ-1GNJ220C)
R117  ValueDisplayed: 20.0  [0201_033]  (hidden comment: CRCW020120R0FNED)
R118  ValueDisplayed: 20.0  [0201_033]  (hidden comment: CRCW020120R0FNED)
R119  ValueDisplayed: 22  [0201]  (hidden comment: ERJ-1GNJ220C)
R120  ValueDisplayed: 22  [0201]  (hidden comment: ERJ-1GNJ220C)
R121  ValueDisplayed: 4.70k  [0201]  (hidden comment: RC0201FR-7D4K7L)
R122  ValueDisplayed: 4.70k  [0201]  (hidden comment: RC0201FR-7D4K7L)
R123  ValueDisplayed: 20.0  [0201_033]  (hidden comment: CRCW020120R0FNED)
R124  ValueDisplayed: 1.00k  [0402]  (hidden comment: CRCW04021K00FKED)
R125  ValueDisplayed: 20.0  [0201_033]  (hidden comment: CRCW020120R0FNED)
R127  ValueDisplayed: 15.0k  [0402]  (hidden comment: RC0402FR-0715KL)
R129  ValueDisplayed: 10.0k  [0402L]  (hidden comment: CRCW040210K0FKED)
U10  DRV8376SNLGR  [NLG0028A-MFG]

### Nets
3V3: C120.2 J4.7 R121.2 R122.2
24V: C112.1 C113.1 C114.1 C115.1 U10.2(VM)
GND: C112.2 C113.2 C114.2 C116.1 C117.1 C118.2 C119.2 C120.1 C121.2 C122.2 C123.2 C124.2 C125.1 C126.1 J4.8 R129.1 U10.3(PGND) U10.7(PGND) U10.8(AGND) U10.29(Thermal_Pad)
GVDD1: C117.2 R127.2 U10.10(GVDD)
ADC_VREF: R124.1
DRV_FLT_AX1: R122.1 U10.12(~{FAULT})
DRV_nSleep: R113.1
DRV_OFF: R112.1
DRVOFF1: R112.2 U10.11(DRVOFF)
ENC_SPI_CS1: R119.1
I_A1: U10.27(SOA) ; off-sheet I_A1
I_B1: U10.26(SOB) ; off-sheet I_B1
I_C1: U10.25(SOC) ; off-sheet I_C1
INHA1: C118.1 R114.2 U10.14(INHA)
INHB1: C121.1 R117.2 U10.16(INHB)
INHC1: C123.1 R123.2 U10.18(INHC)
INLA1: C119.1 R115.2 U10.15(INLA)
INLB1: C122.1 R118.2 U10.17(INLB)
INLC1: C124.1 R125.2 U10.19(INLC)
nSLEEP1: R113.2 U10.13(~{SLEEP})
PWM_A1_H: R114.1
PWM_A1_L: R115.1
PWM_B1_H: R117.1
PWM_B1_L: R118.1
PWM_C1_H: R123.1
PWM_C1_L: R125.1
SPIA_CLK_AX1_2: J4.11 ; off-sheet SPIA_CLK_AX1_2
SPIA_PICO_AX1_2: J4.10 ; off-sheet SPIA_PICO_AX1_2
SPIA_POCI_AX12: R116.1
SPID_CLK_DRVCFG: U10.22(SCLK) ; off-sheet SPID_CLK_DRVCFG
SPID_CS1_DRV: R121.1 U10.23(~{SCS})
SPID_PICO_DRVCFG: U10.21(SDI) ; off-sheet SPID_PICO_DRVCFG
SPID_POCI_DRV: R120.1
U1: J4.1 J4.2 U10.4(OUTA)
V1: J4.3 J4.4 U10.5(OUTB)
VLIMIT1: C126.2 R127.1 R129.2 U10.28(ILIMIT)
W1: J4.5 J4.6 U10.6(OUTC)
NetC115_2: C115.2 U10.1(CP)
NetC116_2: C116.2 U10.9(AVDD)
NetC125_2: C125.2 R124.2 U10.24(VREF)
NetJ4_9: J4.9 R116.2
NetJ4_12: J4.12 R119.2
NetR120_2: R120.2 U10.20(SDO)

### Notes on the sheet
- AXIS1_DRV
- Gain = 2.5V/A; (0.4/1/2.5/5)
  ILIMIT = 0.6A;
  VLIMIT = (VREF/2) + (Iout x Gain/3) = 2V;
  SOx = (VREF/2) +/- Gain x Ioutx = 0V ~ 3V
  VLIMIT = GVDD x (10k/RLIM1 + 10K) -- > RLIM1 = 15Kohm

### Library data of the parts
C112 = CMP-0008802-2: CAP, CERM, 10 uF, 50 V, +/- 10%, X7R, 1206; Manufacturer: Samsung; TaMin_C: -55°C; Polarized: N; SizeAreaWB_mm2: 10.92; Value1: Unknown; U/M: EA; Value: 10uF; TaMax_C: 125°C; SizeZ_mm: 1.8; SizeX_mm: 3.2; SizeY_mm: 1.6; Cap_Case: 1206; SizeArea_mm2: 5.12; Cap_F: 10µF; AEC Category: Q200
C113 C114 = CMP-0064946-2: CAP, CERM, 0.1 uF, 50 V,+/- 10%, X7R, 0402; Manufacturer: TDK; TaMin_C: -55°C; Polarized: N; SizeAreaWB_mm2: 3; Value1: Unknown; U/M: EA; Value: 0.1uF; TaMax_C: 125°C; SizeZ_mm: 0.6; SizeX_mm: 1; SizeY_mm: 0.5; Cap_F: 100nF; AEC Category: Q200
C115 C116 C120 C125 C126 = CMP-0006326-2: CAP, CERM, 0.1 uF, 50 V, +/- 20%, X7R, AEC-Q200 Grade 1, 0402; Manufacturer: TDK; TaMin_C: -55°C; Polarized: N; SizeAreaWB_mm2: 3; Value1: Unknown; U/M: EA; Value: 0.1uF; TaMax_C: 125°C; SizeZ_mm: 0.6; SizeX_mm: 1; SizeY_mm: 0.5; AEC Qualified: Y; Cap_F: 100nF; AEC Category: Q200
C117 = CMP-0093200-1: 1µF ±10% 10V Ceramic Capacitor X7R 0402 (1005 Metric); Manufacturer: Cal-Chip Electronics; TempCo: 15%; SizeZ_mm: 0.6mm; AEC Qualified: No
C118 C119 C121-C124 = CMP-0009662-3: CAP, CERM, 47 pF, 25 V, +/- 5%, C0G/NP0, 0201; Manufacturer: MuRata; TaMin_C: -55°C; Polarized: N; SizeAreaWB_mm2: 2.08; Value1: Unknown; U/M: EA; Value: 47pF; TaMax_C: 125°C; SizeZ_mm: 0.33; SizeX_mm: 0.6; SizeY_mm: 0.3; Cap_Case: 0201; SizeArea_mm2: 0.18; AEC Category: Q200
J4 = CMP-0126588-1: Conn FPC Connector F 12 POS 0.5mm Solder Ver SMD T/R; Manufacturer: JST; ContactFinish: Gold,Nickel; Current_A: 500mA; Voltage_V: 50V; AEC Qualified: No; Conn Gender: Female; Conn Orientation: Vertical; Is Female: yes; SizeZ_mm: 3.3mm; Standoff Height: 0.13mm
R112 R113 R124 = CMP-0026071-3: as R107 on sheet TIDA-010992_05_ETH_Conn
R114 R115 R117 R118 R123 R125 = CMP-0078192-1: RES, 20.0, 1%, 0.05 W, 0201; Manufacturer: Vishay-Dale; Value_Code: 20R0; SizeArea_mm2: 0.18; AEC Qualified: N; AEC Category: Q200; Res_ohm: 20; Value: 20.0; SizeZ_mm: 0.33; EIA_Code: E96; TempCo: 200 ppm/C; Power_W: 50mW; VDC_V: 30V; SizeY_mm: 0.3; Value2: 0.05W; U/M: EA; SizeX_mm: 0.6
R116 R119 R120 = CMP-0027015-3: RES, 22, 5%, 0.05 W, AEC-Q200 Grade 1, 0201; Manufacturer: Panasonic; Power_W: 50mW; TempCo: 200 ppm/C; Value_Code: 22R0; U/M: EA; Value: 22; EIA_Code: E24; SizeX_mm: 0.6; SizeY_mm: 0.3; SizeZ_mm: 0.26; Value2: 0.05W; SizeArea_mm2: 0.18; AEC Qualified: Y; AEC Grade: 1; AEC Category: Q200
R121 R122 = CMP-0028031-1: as R68 on sheet TIDA-010992_04_BOOT_SoC power_CLK
R127 = CMP-0078583-1: RES, 15.0 k, 1%, 0.063 W, 0402; Manufacturer: Yageo America; Power_W: 63mW; Green_Lifecycle: Active; TempCo: 100 ppm/C; Value_Code: 15k0; Green_REACh: Passed; Value: 15.0k; EIA_Code: E96; Res_ohm: 15k; SizeX_mm: 1; SizeY_mm: 0.5; SizeZ_mm: 0.6; Value2: 0.063W; AEC Qualified: N; AEC Category: Q200
R129 = CMP-0025958-3: RES, 10.0 k, 1%, 0.063 W, AEC-Q200 Grade 0, 0402; Manufacturer: Vishay-Dale; Power_W: 63mW; TempCo: 100 ppm/C; Value_Code: 10k0; Value: 10.0k; EIA_Code: E96; Res_ohm: 10k; SizeX_mm: 1; SizeY_mm: 0.5; SizeZ_mm: 0.6; Value2: 0.063W; AEC Qualified: Y; VDC_V: 50V; AEC Category: Q200; AEC Grade: 0
U10 = CMP-0122073-1: Three-Phase Integrated FET Motor Driver; Manufacturer: Texas Instruments; SizeZ_mm: 1mm; AEC Qualified: No; Max Supply Voltage: 65V; Min Supply Voltage: 4.5V; Motor Type: Brushless DC; Nominal Supply Current: 6.6-8.2mA; Number Of Outputs: 3; Standoff Height: 0mm; Switching Frequency: 100kHz; TaMax_C: +125°C; TaMin_C: -40°C; TJmax_C: +150°C

## Sheet TIDA-010992_07_DRV_AXIS2.SchDoc
size 431 x 279 mm; Date: Not shown in title block; ApprovedBy: Not shown in title block; CheckedBy: Not shown in title block; Author: Not shown in title block; CompanyName: Not shown in title block; Engineer: Not shown in title block; Organization: Not shown in title block; Address1: Not shown in title block; Address2: Not shown in title block; Address3: Not shown in title block; Address4: Not shown in title block; DocumentNumber: 7; Revision: Use project parameter SCH_Rev; SheetNumber: 7; SheetTotal: 13; PageSetup: Record=PageOptions¦CenterHorizontal=True¦CenterVertical=True¦PrintScale=1.00¦XCorrection=1.00¦YCorrection=1.00¦PrintKind=0¦BorderSize=5000000¦LeftOffset=0¦BottomOffset=0¦Orientation=2¦PaperLength=1000¦PaperWidth=1000¦Scale=100¦PaperSource=15¦PrintQuality=600¦MediaType=1¦DitherType=10¦PaperKind=Letter¦PrintScaleMode=1

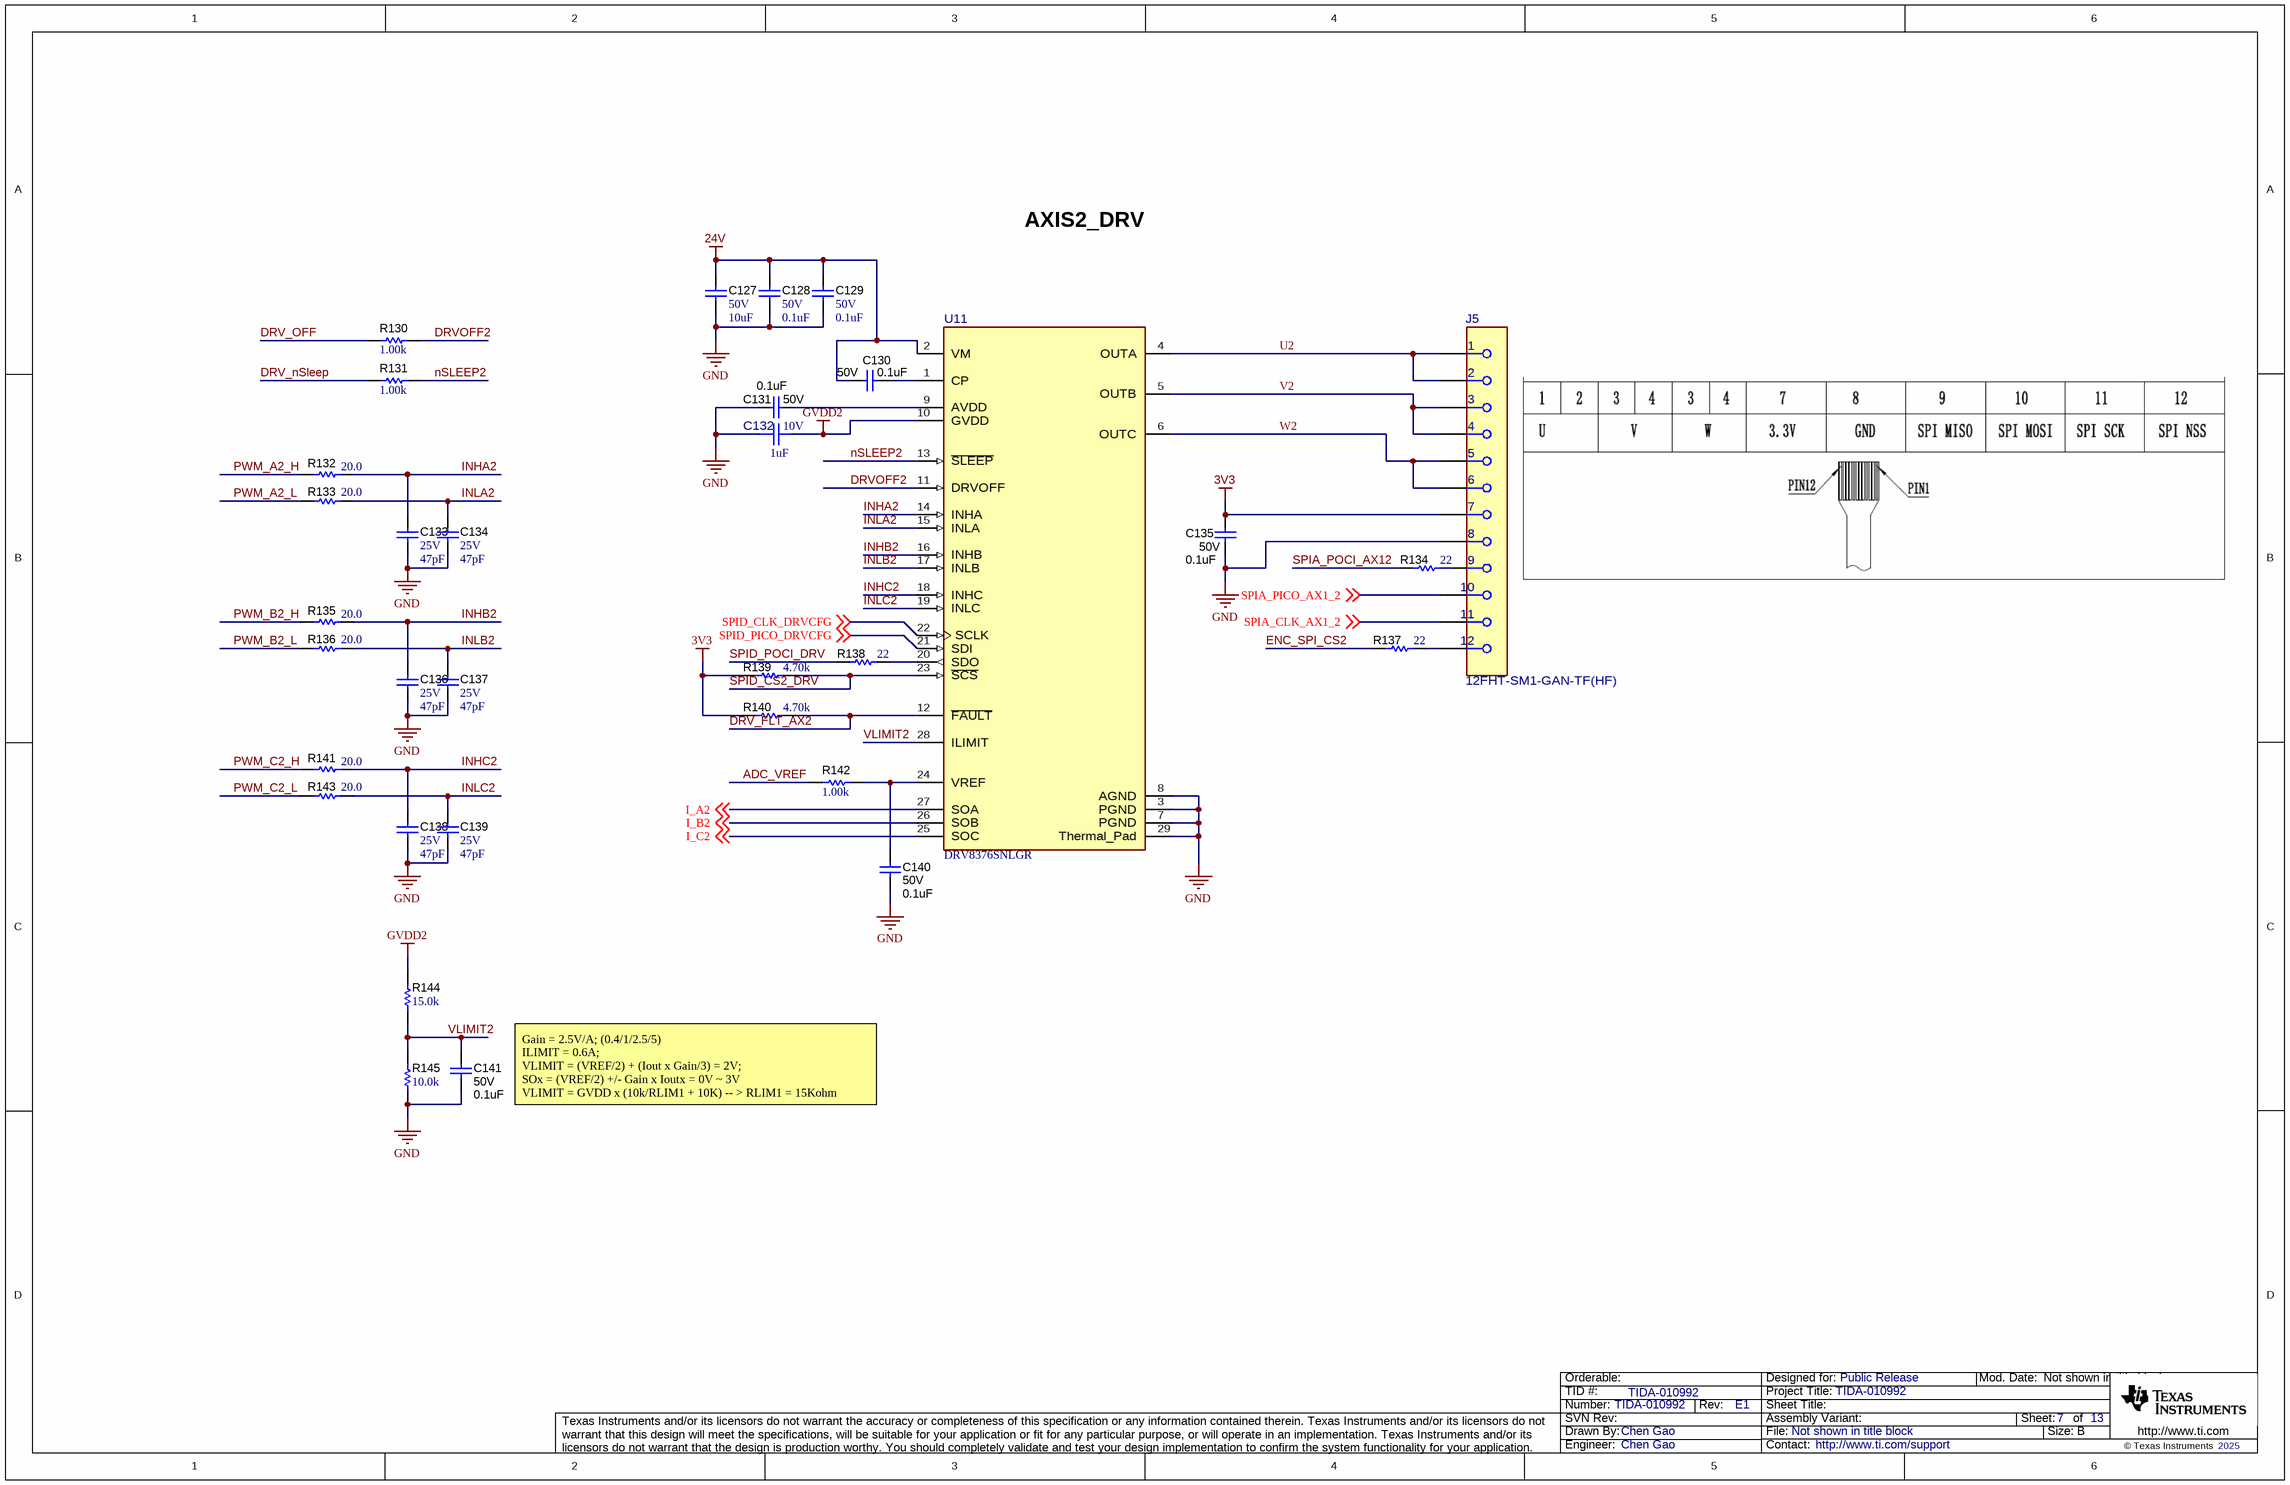
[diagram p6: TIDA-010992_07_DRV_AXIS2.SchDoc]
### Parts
C127  VDC_V: 50V  ValueDisplayed: 10uF  [1206_180]  (hidden comment: CL31B106KBHNNNE)
C128  VDC_V: 50V  ValueDisplayed: 0.1uF  [0402]  (hidden comment: C1005X7R1H104K050BE)
C129  VDC_V: 50V  ValueDisplayed: 0.1uF  [0402]  (hidden comment: C1005X7R1H104K050BE)
C130  VDC_V: 50V  ValueDisplayed: 0.1uF  [0402]  (hidden comment: CGA2B3X7R1H104M050BB)
C131  VDC_V: 50V  ValueDisplayed: 0.1uF  [0402]  (hidden comment: CGA2B3X7R1H104M050BB)
C132  VDC_V: 10V  ValueDisplayed: 1uF  [FP-GMC04X7R105K10NT_0402-MFG]  (hidden comment: GMC04X7R105K10NT)
C133  VDC_V: 25V  ValueDisplayed: 47pF  [0201_033]  (hidden comment: GRM0335C1E470JA01D)
C134  VDC_V: 25V  ValueDisplayed: 47pF  [0201_033]  (hidden comment: GRM0335C1E470JA01D)
C135  VDC_V: 50V  ValueDisplayed: 0.1uF  [0402]  (hidden comment: CGA2B3X7R1H104M050BB)
C136  VDC_V: 25V  ValueDisplayed: 47pF  [0201_033]  (hidden comment: GRM0335C1E470JA01D)
C137  VDC_V: 25V  ValueDisplayed: 47pF  [0201_033]  (hidden comment: GRM0335C1E470JA01D)
C138  VDC_V: 25V  ValueDisplayed: 47pF  [0201_033]  (hidden comment: GRM0335C1E470JA01D)
C139  VDC_V: 25V  ValueDisplayed: 47pF  [0201_033]  (hidden comment: GRM0335C1E470JA01D)
C140  VDC_V: 50V  ValueDisplayed: 0.1uF  [0402]  (hidden comment: CGA2B3X7R1H104M050BB)
C141  VDC_V: 50V  ValueDisplayed: 0.1uF  [0402]  (hidden comment: CGA2B3X7R1H104M050BB)
J5  12FHT-SM1-GAN-TF(HF)  [FP-12FHT-SM1-GAN-TF(HF)_CONN_FPC_12-MFG]
R130  ValueDisplayed: 1.00k  [0402]  (hidden comment: CRCW04021K00FKED)
R131  ValueDisplayed: 1.00k  [0402]  (hidden comment: CRCW04021K00FKED)
R132  ValueDisplayed: 20.0  [0201_033]  (hidden comment: CRCW020120R0FNED)
R133  ValueDisplayed: 20.0  [0201_033]  (hidden comment: CRCW020120R0FNED)
R134  ValueDisplayed: 22  [0201]  (hidden comment: ERJ-1GNJ220C)
R135  ValueDisplayed: 20.0  [0201_033]  (hidden comment: CRCW020120R0FNED)
R136  ValueDisplayed: 20.0  [0201_033]  (hidden comment: CRCW020120R0FNED)
R137  ValueDisplayed: 22  [0201]  (hidden comment: ERJ-1GNJ220C)
R138  ValueDisplayed: 22  [0201]  (hidden comment: ERJ-1GNJ220C)
R139  ValueDisplayed: 4.70k  [0201]  (hidden comment: RC0201FR-7D4K7L)
R140  ValueDisplayed: 4.70k  [0201]  (hidden comment: RC0201FR-7D4K7L)
R141  ValueDisplayed: 20.0  [0201_033]  (hidden comment: CRCW020120R0FNED)
R142  ValueDisplayed: 1.00k  [0402]  (hidden comment: CRCW04021K00FKED)
R143  ValueDisplayed: 20.0  [0201_033]  (hidden comment: CRCW020120R0FNED)
R144  ValueDisplayed: 15.0k  [0402]  (hidden comment: RC0402FR-0715KL)
R145  ValueDisplayed: 10.0k  [0402L]  (hidden comment: CRCW040210K0FKED)
U11  DRV8376SNLGR  [NLG0028A-MFG]

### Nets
3V3: C135.2 J5.7 R139.2 R140.2
24V: C127.1 C128.1 C129.1 C130.1 U11.2(VM)
GND: C127.2 C128.2 C129.2 C131.1 C132.1 C133.2 C134.2 C135.1 C136.2 C137.2 C138.2 C139.2 C140.1 C141.1 J5.8 R145.1 U11.3(PGND) U11.7(PGND) U11.8(AGND) U11.29(Thermal_Pad)
GVDD2: C132.2 R144.2 U11.10(GVDD)
ADC_VREF: R142.1
DRV_FLT_AX2: R140.1 U11.12(~{FAULT})
DRV_nSleep: R131.1
DRV_OFF: R130.1
DRVOFF2: R130.2 U11.11(DRVOFF)
ENC_SPI_CS2: R137.1
I_A2: U11.27(SOA) ; off-sheet I_A2
I_B2: U11.26(SOB) ; off-sheet I_B2
I_C2: U11.25(SOC) ; off-sheet I_C2
INHA2: C133.1 R132.2 U11.14(INHA)
INHB2: C136.1 R135.2 U11.16(INHB)
INHC2: C138.1 R141.2 U11.18(INHC)
INLA2: C134.1 R133.2 U11.15(INLA)
INLB2: C137.1 R136.2 U11.17(INLB)
INLC2: C139.1 R143.2 U11.19(INLC)
nSLEEP2: R131.2 U11.13(~{SLEEP})
PWM_A2_H: R132.1
PWM_A2_L: R133.1
PWM_B2_H: R135.1
PWM_B2_L: R136.1
PWM_C2_H: R141.1
PWM_C2_L: R143.1
SPIA_CLK_AX1_2: J5.11 ; off-sheet SPIA_CLK_AX1_2
SPIA_PICO_AX1_2: J5.10 ; off-sheet SPIA_PICO_AX1_2
SPIA_POCI_AX12: R134.1
SPID_CLK_DRVCFG: U11.22(SCLK) ; off-sheet SPID_CLK_DRVCFG
SPID_CS2_DRV: R139.1 U11.23(~{SCS})
SPID_PICO_DRVCFG: U11.21(SDI) ; off-sheet SPID_PICO_DRVCFG
SPID_POCI_DRV: R138.1
U2: J5.1 J5.2 U11.4(OUTA)
V2: J5.3 J5.4 U11.5(OUTB)
VLIMIT2: C141.2 R144.1 R145.2 U11.28(ILIMIT)
W2: J5.5 J5.6 U11.6(OUTC)
NetC130_2: C130.2 U11.1(CP)
NetC131_2: C131.2 U11.9(AVDD)
NetC140_2: C140.2 R142.2 U11.24(VREF)
NetJ5_9: J5.9 R134.2
NetJ5_12: J5.12 R137.2
NetR138_2: R138.2 U11.20(SDO)

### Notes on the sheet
- AXIS2_DRV
- Gain = 2.5V/A; (0.4/1/2.5/5)
  ILIMIT = 0.6A;
  VLIMIT = (VREF/2) + (Iout x Gain/3) = 2V;
  SOx = (VREF/2) +/- Gain x Ioutx = 0V ~ 3V
  VLIMIT = GVDD x (10k/RLIM1 + 10K) -- > RLIM1 = 15Kohm

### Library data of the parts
C127 = CMP-0008802-2: as C112 on sheet TIDA-010992_06_DRV_AXIS1
C128 C129 = CMP-0064946-2: as C113 on sheet TIDA-010992_06_DRV_AXIS1
C130 C131 C135 C140 C141 = CMP-0006326-2: as C115 on sheet TIDA-010992_06_DRV_AXIS1
C132 = CMP-0093200-1: as C117 on sheet TIDA-010992_06_DRV_AXIS1
C133 C134 C136-C139 = CMP-0009662-3: as C118 on sheet TIDA-010992_06_DRV_AXIS1
J5 = CMP-0126588-1: as J4 on sheet TIDA-010992_06_DRV_AXIS1
R130 R131 R142 = CMP-0026071-3: as R107 on sheet TIDA-010992_05_ETH_Conn
R132 R133 R135 R136 R141 R143 = CMP-0078192-1: as R114 on sheet TIDA-010992_06_DRV_AXIS1
R134 R137 R138 = CMP-0027015-3: as R116 on sheet TIDA-010992_06_DRV_AXIS1
R139 R140 = CMP-0028031-1: as R68 on sheet TIDA-010992_04_BOOT_SoC power_CLK
R144 = CMP-0078583-1: as R127 on sheet TIDA-010992_06_DRV_AXIS1
R145 = CMP-0025958-3: as R129 on sheet TIDA-010992_06_DRV_AXIS1
U11 = CMP-0122073-1: as U10 on sheet TIDA-010992_06_DRV_AXIS1

## Sheet TIDA-010992_08_DRV_AXIS3.SchDoc
size 431 x 279 mm; Date: Not shown in title block; ApprovedBy: Not shown in title block; CheckedBy: Not shown in title block; Author: Not shown in title block; CompanyName: Not shown in title block; Engineer: Not shown in title block; Organization: Not shown in title block; Address1: Not shown in title block; Address2: Not shown in title block; Address3: Not shown in title block; Address4: Not shown in title block; DocumentNumber: 8; Revision: Use project parameter SCH_Rev; SheetNumber: 8; SheetTotal: 13; PageSetup: Record=PageOptions¦CenterHorizontal=True¦CenterVertical=True¦PrintScale=1.00¦XCorrection=1.00¦YCorrection=1.00¦PrintKind=0¦BorderSize=5000000¦LeftOffset=0¦BottomOffset=0¦Orientation=2¦PaperLength=1000¦PaperWidth=1000¦Scale=100¦PaperSource=15¦PrintQuality=600¦MediaType=1¦DitherType=10¦PaperKind=Letter¦PrintScaleMode=1

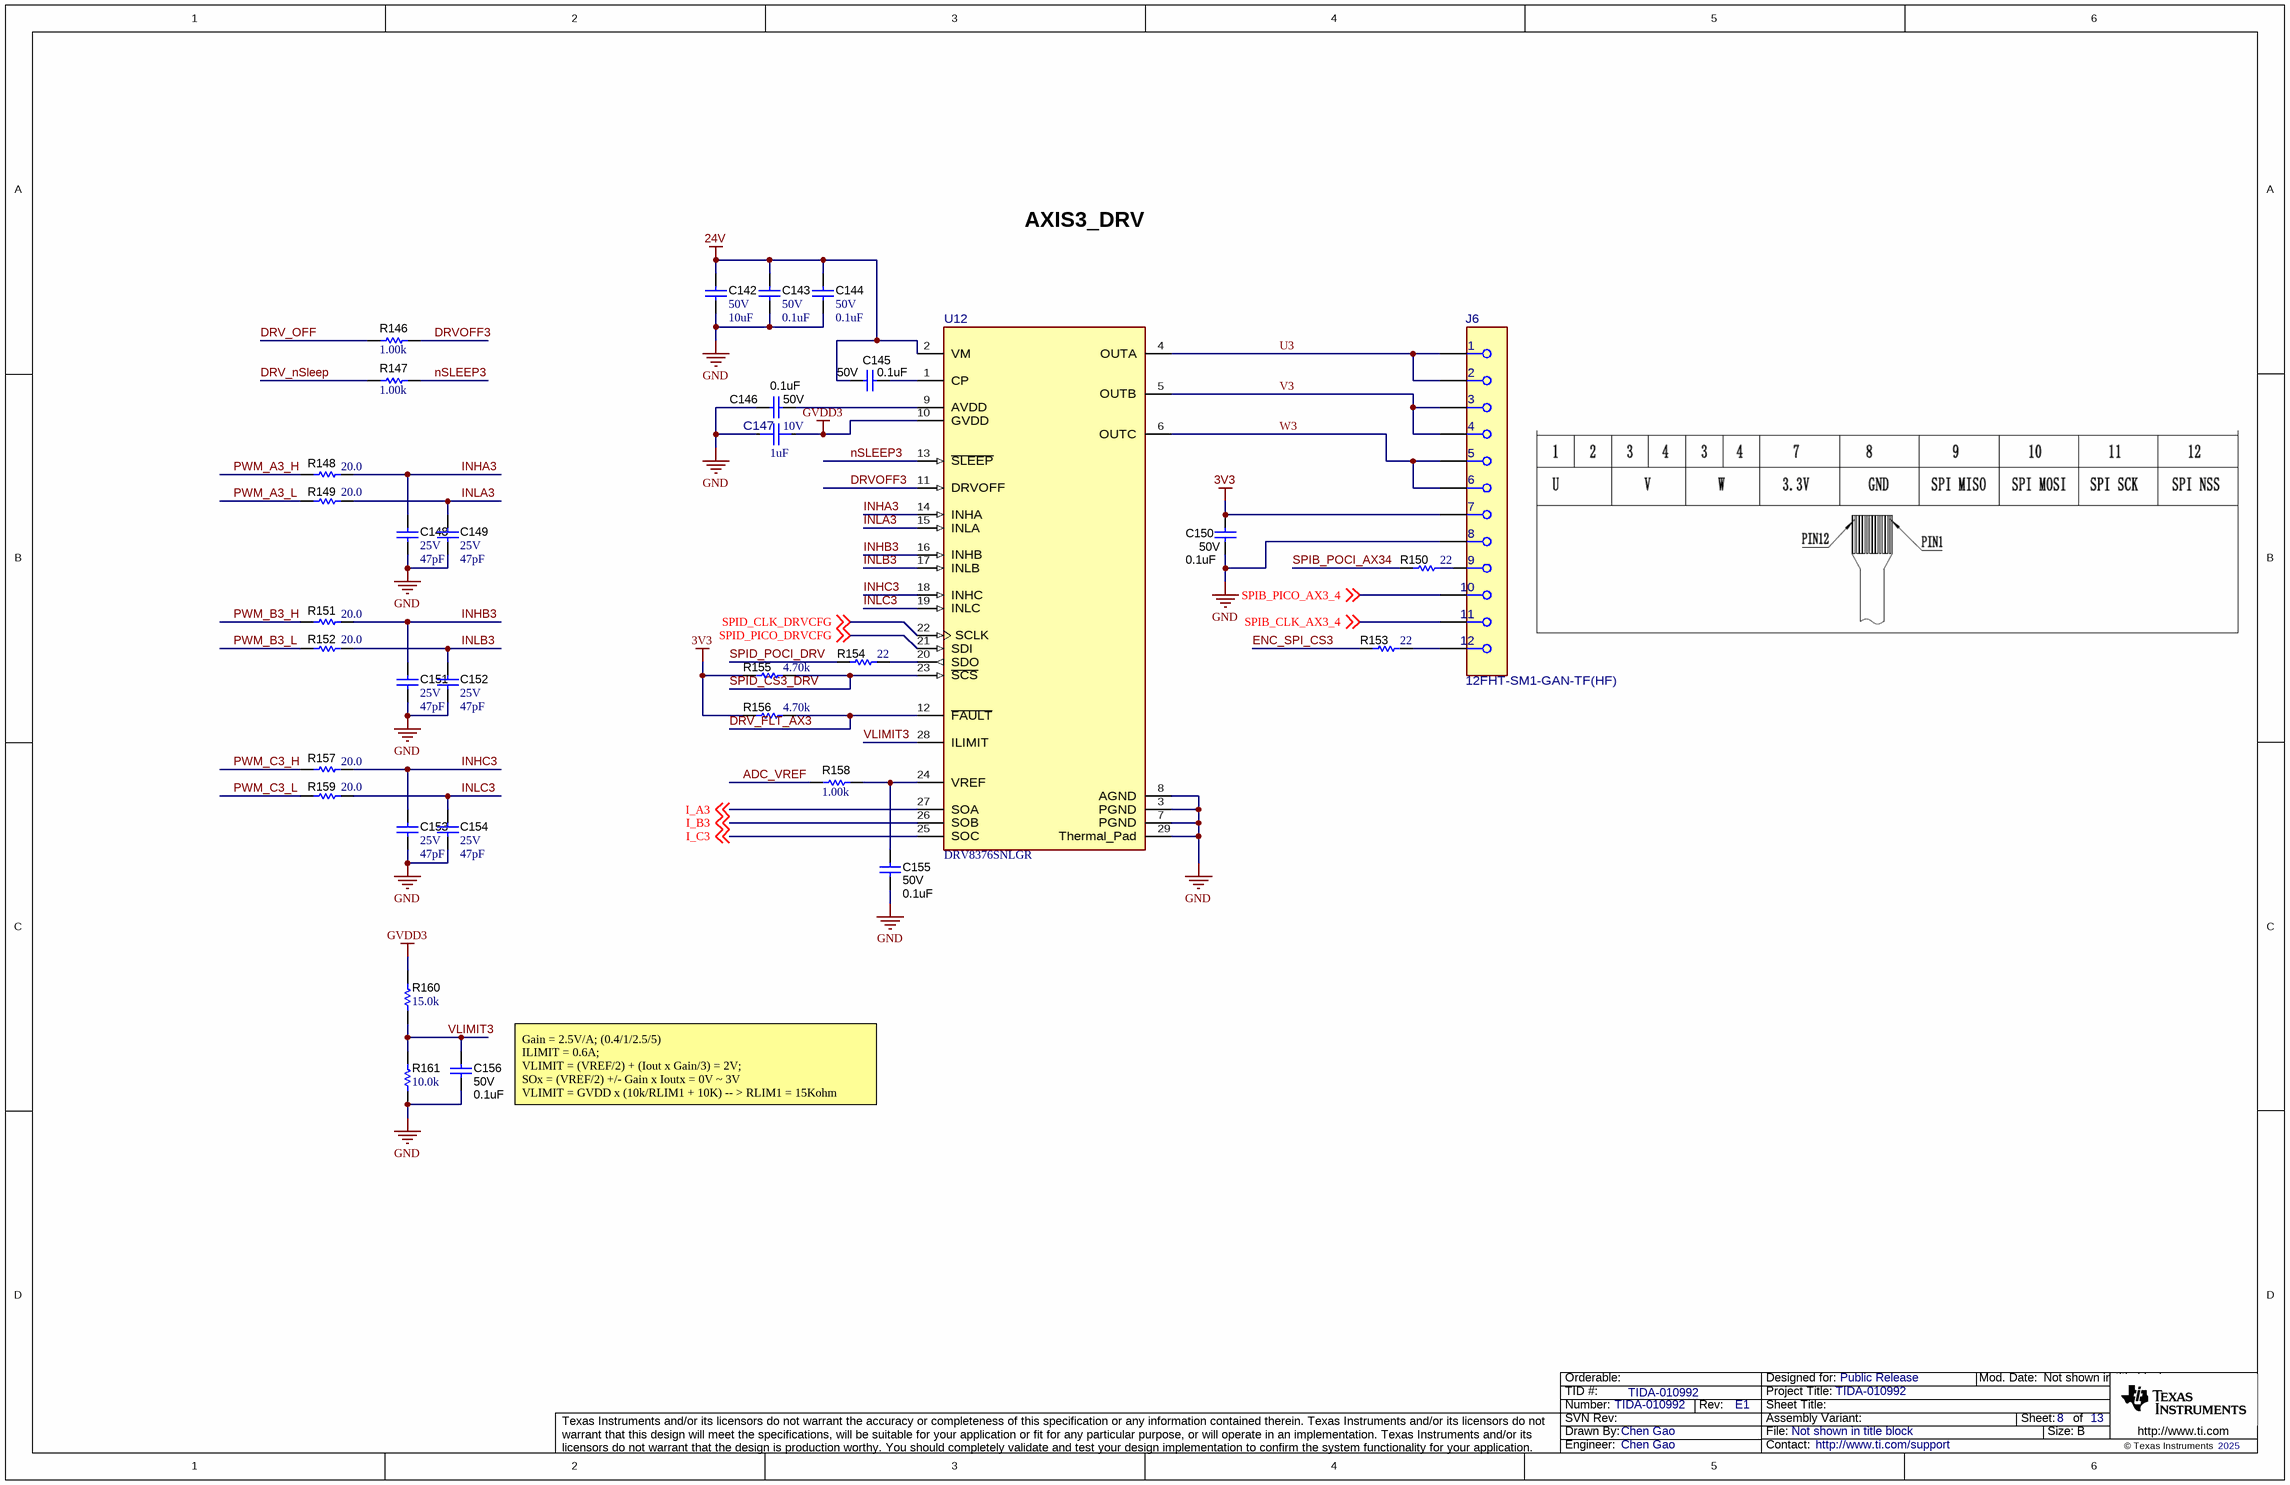
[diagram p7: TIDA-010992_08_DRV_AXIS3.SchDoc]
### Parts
C142  VDC_V: 50V  ValueDisplayed: 10uF  [1206_180]  (hidden comment: CL31B106KBHNNNE)
C143  VDC_V: 50V  ValueDisplayed: 0.1uF  [0402]  (hidden comment: C1005X7R1H104K050BE)
C144  VDC_V: 50V  ValueDisplayed: 0.1uF  [0402]  (hidden comment: C1005X7R1H104K050BE)
C145  VDC_V: 50V  ValueDisplayed: 0.1uF  [0402]  (hidden comment: CGA2B3X7R1H104M050BB)
C146  VDC_V: 50V  ValueDisplayed: 0.1uF  [0402]  (hidden comment: CGA2B3X7R1H104M050BB)
C147  VDC_V: 10V  ValueDisplayed: 1uF  [FP-GMC04X7R105K10NT_0402-MFG]  (hidden comment: GMC04X7R105K10NT)
C148  VDC_V: 25V  ValueDisplayed: 47pF  [0201_033]  (hidden comment: GRM0335C1E470JA01D)
C149  VDC_V: 25V  ValueDisplayed: 47pF  [0201_033]  (hidden comment: GRM0335C1E470JA01D)
C150  VDC_V: 50V  ValueDisplayed: 0.1uF  [0402]  (hidden comment: CGA2B3X7R1H104M050BB)
C151  VDC_V: 25V  ValueDisplayed: 47pF  [0201_033]  (hidden comment: GRM0335C1E470JA01D)
C152  VDC_V: 25V  ValueDisplayed: 47pF  [0201_033]  (hidden comment: GRM0335C1E470JA01D)
C153  VDC_V: 25V  ValueDisplayed: 47pF  [0201_033]  (hidden comment: GRM0335C1E470JA01D)
C154  VDC_V: 25V  ValueDisplayed: 47pF  [0201_033]  (hidden comment: GRM0335C1E470JA01D)
C155  VDC_V: 50V  ValueDisplayed: 0.1uF  [0402]  (hidden comment: CGA2B3X7R1H104M050BB)
C156  VDC_V: 50V  ValueDisplayed: 0.1uF  [0402]  (hidden comment: CGA2B3X7R1H104M050BB)
J6  12FHT-SM1-GAN-TF(HF)  [FP-12FHT-SM1-GAN-TF(HF)_CONN_FPC_12-MFG]
R146  ValueDisplayed: 1.00k  [0402]  (hidden comment: CRCW04021K00FKED)
R147  ValueDisplayed: 1.00k  [0402]  (hidden comment: CRCW04021K00FKED)
R148  ValueDisplayed: 20.0  [0201_033]  (hidden comment: CRCW020120R0FNED)
R149  ValueDisplayed: 20.0  [0201_033]  (hidden comment: CRCW020120R0FNED)
R150  ValueDisplayed: 22  [0201]  (hidden comment: ERJ-1GNJ220C)
R151  ValueDisplayed: 20.0  [0201_033]  (hidden comment: CRCW020120R0FNED)
R152  ValueDisplayed: 20.0  [0201_033]  (hidden comment: CRCW020120R0FNED)
R153  ValueDisplayed: 22  [0201]  (hidden comment: ERJ-1GNJ220C)
R154  ValueDisplayed: 22  [0201]  (hidden comment: ERJ-1GNJ220C)
R155  ValueDisplayed: 4.70k  [0201]  (hidden comment: RC0201FR-7D4K7L)
R156  ValueDisplayed: 4.70k  [0201]  (hidden comment: RC0201FR-7D4K7L)
R157  ValueDisplayed: 20.0  [0201_033]  (hidden comment: CRCW020120R0FNED)
R158  ValueDisplayed: 1.00k  [0402]  (hidden comment: CRCW04021K00FKED)
R159  ValueDisplayed: 20.0  [0201_033]  (hidden comment: CRCW020120R0FNED)
R160  ValueDisplayed: 15.0k  [0402]  (hidden comment: RC0402FR-0715KL)
R161  ValueDisplayed: 10.0k  [0402L]  (hidden comment: CRCW040210K0FKED)
U12  DRV8376SNLGR  [NLG0028A-MFG]

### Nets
3V3: C150.2 J6.7 R155.2 R156.2
24V: C142.1 C143.1 C144.1 C145.1 U12.2(VM)
GND: C142.2 C143.2 C144.2 C146.1 C147.1 C148.2 C149.2 C150.1 C151.2 C152.2 C153.2 C154.2 C155.1 C156.1 J6.8 R161.1 U12.3(PGND) U12.7(PGND) U12.8(AGND) U12.29(Thermal_Pad)
GVDD3: C147.2 R160.2 U12.10(GVDD)
ADC_VREF: R158.1
DRV_FLT_AX3: R156.1 U12.12(~{FAULT})
DRV_nSleep: R147.1
DRV_OFF: R146.1
DRVOFF3: R146.2 U12.11(DRVOFF)
ENC_SPI_CS3: R153.1
I_A3: U12.27(SOA) ; off-sheet I_A3
I_B3: U12.26(SOB) ; off-sheet I_B3
I_C3: U12.25(SOC) ; off-sheet I_C3
INHA3: C148.1 R148.2 U12.14(INHA)
INHB3: C151.1 R151.2 U12.16(INHB)
INHC3: C153.1 R157.2 U12.18(INHC)
INLA3: C149.1 R149.2 U12.15(INLA)
INLB3: C152.1 R152.2 U12.17(INLB)
INLC3: C154.1 R159.2 U12.19(INLC)
nSLEEP3: R147.2 U12.13(~{SLEEP})
PWM_A3_H: R148.1
PWM_A3_L: R149.1
PWM_B3_H: R151.1
PWM_B3_L: R152.1
PWM_C3_H: R157.1
PWM_C3_L: R159.1
SPIB_CLK_AX3_4: J6.11 ; off-sheet SPIB_CLK_AX3_4
SPIB_PICO_AX3_4: J6.10 ; off-sheet SPIB_PICO_AX3_4
SPIB_POCI_AX34: R150.1
SPID_CLK_DRVCFG: U12.22(SCLK) ; off-sheet SPID_CLK_DRVCFG
SPID_CS3_DRV: R155.1 U12.23(~{SCS})
SPID_PICO_DRVCFG: U12.21(SDI) ; off-sheet SPID_PICO_DRVCFG
SPID_POCI_DRV: R154.1
U3: J6.1 J6.2 U12.4(OUTA)
V3: J6.3 J6.4 U12.5(OUTB)
VLIMIT3: C156.2 R160.1 R161.2 U12.28(ILIMIT)
W3: J6.5 J6.6 U12.6(OUTC)
NetC145_2: C145.2 U12.1(CP)
NetC146_2: C146.2 U12.9(AVDD)
NetC155_2: C155.2 R158.2 U12.24(VREF)
NetJ6_9: J6.9 R150.2
NetJ6_12: J6.12 R153.2
NetR154_2: R154.2 U12.20(SDO)

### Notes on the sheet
- AXIS3_DRV
- Gain = 2.5V/A; (0.4/1/2.5/5)
  ILIMIT = 0.6A;
  VLIMIT = (VREF/2) + (Iout x Gain/3) = 2V;
  SOx = (VREF/2) +/- Gain x Ioutx = 0V ~ 3V
  VLIMIT = GVDD x (10k/RLIM1 + 10K) -- > RLIM1 = 15Kohm

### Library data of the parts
C142 = CMP-0008802-2: as C112 on sheet TIDA-010992_06_DRV_AXIS1
C143 C144 = CMP-0064946-2: as C113 on sheet TIDA-010992_06_DRV_AXIS1
C145 C146 C150 C155 C156 = CMP-0006326-2: as C115 on sheet TIDA-010992_06_DRV_AXIS1
C147 = CMP-0093200-1: as C117 on sheet TIDA-010992_06_DRV_AXIS1
C148 C149 C151-C154 = CMP-0009662-3: as C118 on sheet TIDA-010992_06_DRV_AXIS1
J6 = CMP-0126588-1: as J4 on sheet TIDA-010992_06_DRV_AXIS1
R146 R147 R158 = CMP-0026071-3: as R107 on sheet TIDA-010992_05_ETH_Conn
R148 R149 R151 R152 R157 R159 = CMP-0078192-1: as R114 on sheet TIDA-010992_06_DRV_AXIS1
R150 R153 R154 = CMP-0027015-3: as R116 on sheet TIDA-010992_06_DRV_AXIS1
R155 R156 = CMP-0028031-1: as R68 on sheet TIDA-010992_04_BOOT_SoC power_CLK
R160 = CMP-0078583-1: as R127 on sheet TIDA-010992_06_DRV_AXIS1
R161 = CMP-0025958-3: as R129 on sheet TIDA-010992_06_DRV_AXIS1
U12 = CMP-0122073-1: as U10 on sheet TIDA-010992_06_DRV_AXIS1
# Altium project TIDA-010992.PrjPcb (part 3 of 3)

## Sheet TIDA-010992_09_DRV_AXIS4.SchDoc
size 431 x 279 mm; Date: Not shown in title block; ApprovedBy: Not shown in title block; CheckedBy: Not shown in title block; Author: Not shown in title block; CompanyName: Not shown in title block; Engineer: Not shown in title block; Organization: Not shown in title block; Address1: Not shown in title block; Address2: Not shown in title block; Address3: Not shown in title block; Address4: Not shown in title block; DocumentNumber: 9; Revision: Use project parameter SCH_Rev; SheetNumber: 9; SheetTotal: 13; PageSetup: Record=PageOptions¦CenterHorizontal=True¦CenterVertical=True¦PrintScale=1.00¦XCorrection=1.00¦YCorrection=1.00¦PrintKind=0¦BorderSize=5000000¦LeftOffset=0¦BottomOffset=0¦Orientation=2¦PaperLength=1000¦PaperWidth=1000¦Scale=100¦PaperSource=15¦PrintQuality=600¦MediaType=1¦DitherType=10¦PaperKind=Letter¦PrintScaleMode=1

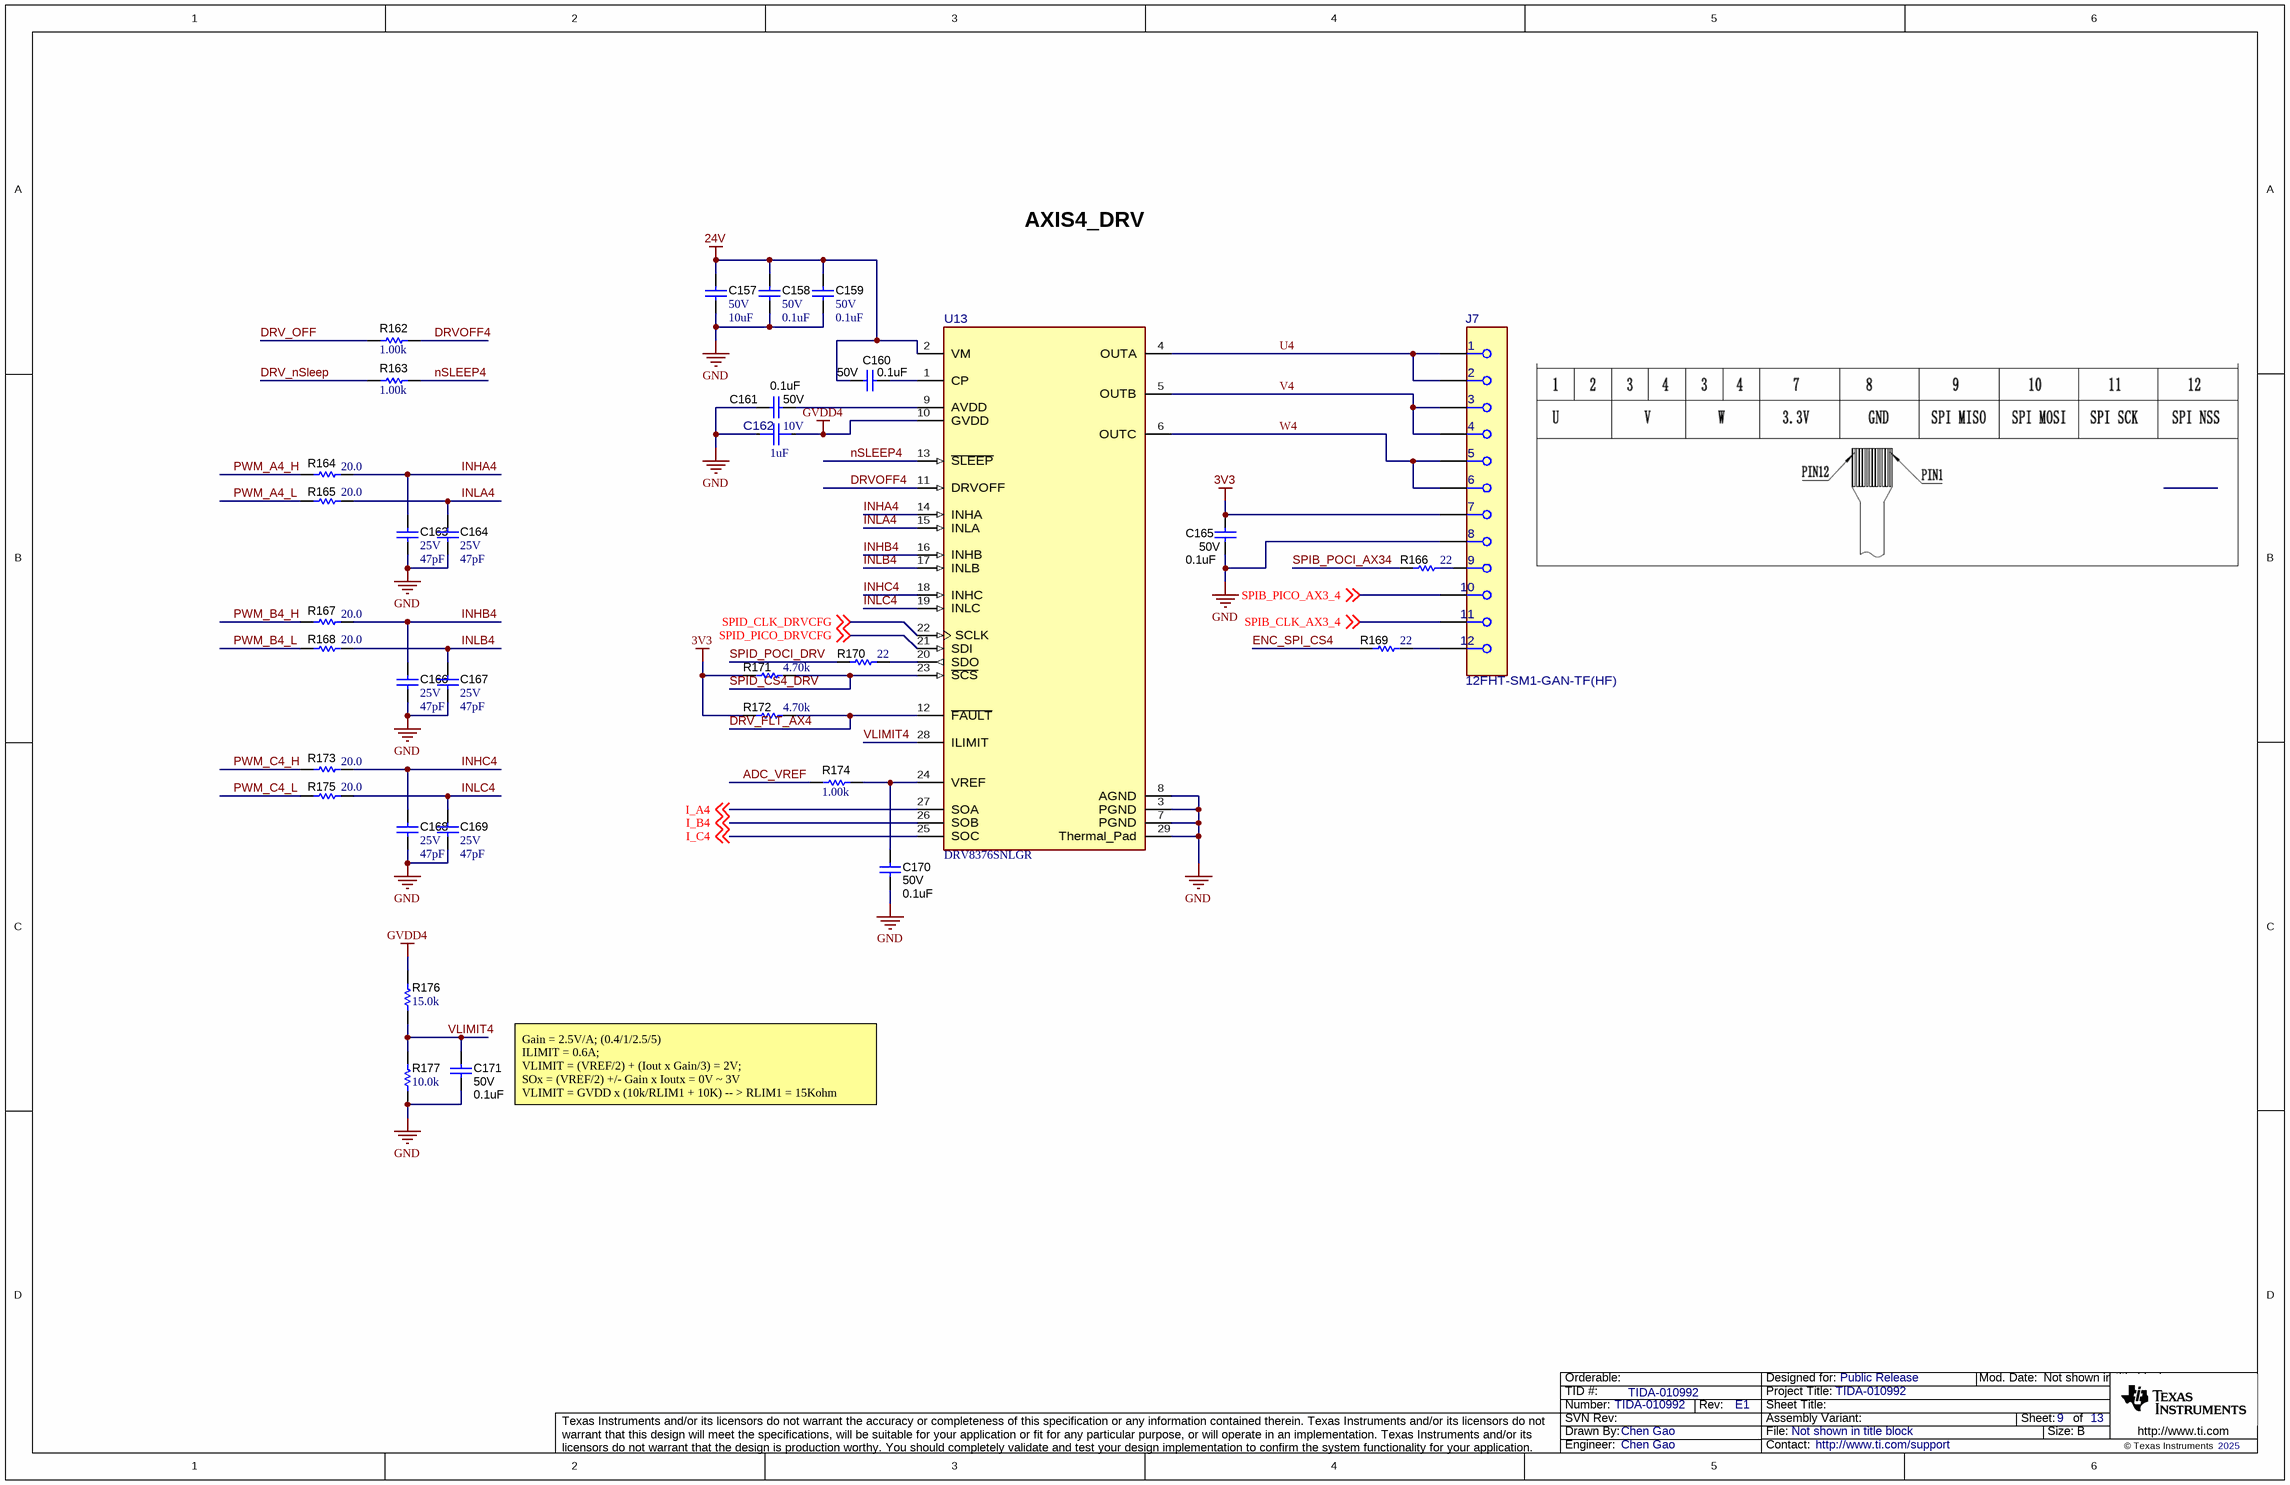
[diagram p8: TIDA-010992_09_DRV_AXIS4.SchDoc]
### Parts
C157  VDC_V: 50V  ValueDisplayed: 10uF  [1206_180]  (hidden comment: CL31B106KBHNNNE)
C158  VDC_V: 50V  ValueDisplayed: 0.1uF  [0402]  (hidden comment: C1005X7R1H104K050BE)
C159  VDC_V: 50V  ValueDisplayed: 0.1uF  [0402]  (hidden comment: C1005X7R1H104K050BE)
C160  VDC_V: 50V  ValueDisplayed: 0.1uF  [0402]  (hidden comment: CGA2B3X7R1H104M050BB)
C161  VDC_V: 50V  ValueDisplayed: 0.1uF  [0402]  (hidden comment: CGA2B3X7R1H104M050BB)
C162  VDC_V: 10V  ValueDisplayed: 1uF  [FP-GMC04X7R105K10NT_0402-MFG]  (hidden comment: GMC04X7R105K10NT)
C163  VDC_V: 25V  ValueDisplayed: 47pF  [0201_033]  (hidden comment: GRM0335C1E470JA01D)
C164  VDC_V: 25V  ValueDisplayed: 47pF  [0201_033]  (hidden comment: GRM0335C1E470JA01D)
C165  VDC_V: 50V  ValueDisplayed: 0.1uF  [0402]  (hidden comment: CGA2B3X7R1H104M050BB)
C166  VDC_V: 25V  ValueDisplayed: 47pF  [0201_033]  (hidden comment: GRM0335C1E470JA01D)
C167  VDC_V: 25V  ValueDisplayed: 47pF  [0201_033]  (hidden comment: GRM0335C1E470JA01D)
C168  VDC_V: 25V  ValueDisplayed: 47pF  [0201_033]  (hidden comment: GRM0335C1E470JA01D)
C169  VDC_V: 25V  ValueDisplayed: 47pF  [0201_033]  (hidden comment: GRM0335C1E470JA01D)
C170  VDC_V: 50V  ValueDisplayed: 0.1uF  [0402]  (hidden comment: CGA2B3X7R1H104M050BB)
C171  VDC_V: 50V  ValueDisplayed: 0.1uF  [0402]  (hidden comment: CGA2B3X7R1H104M050BB)
J7  12FHT-SM1-GAN-TF(HF)  [FP-12FHT-SM1-GAN-TF(HF)_CONN_FPC_12-MFG]
R162  ValueDisplayed: 1.00k  [0402]  (hidden comment: CRCW04021K00FKED)
R163  ValueDisplayed: 1.00k  [0402]  (hidden comment: CRCW04021K00FKED)
R164  ValueDisplayed: 20.0  [0201_033]  (hidden comment: CRCW020120R0FNED)
R165  ValueDisplayed: 20.0  [0201_033]  (hidden comment: CRCW020120R0FNED)
R166  ValueDisplayed: 22  [0201]  (hidden comment: ERJ-1GNJ220C)
R167  ValueDisplayed: 20.0  [0201_033]  (hidden comment: CRCW020120R0FNED)
R168  ValueDisplayed: 20.0  [0201_033]  (hidden comment: CRCW020120R0FNED)
R169  ValueDisplayed: 22  [0201]  (hidden comment: ERJ-1GNJ220C)
R170  ValueDisplayed: 22  [0201]  (hidden comment: ERJ-1GNJ220C)
R171  ValueDisplayed: 4.70k  [0201]  (hidden comment: RC0201FR-7D4K7L)
R172  ValueDisplayed: 4.70k  [0201]  (hidden comment: RC0201FR-7D4K7L)
R173  ValueDisplayed: 20.0  [0201_033]  (hidden comment: CRCW020120R0FNED)
R174  ValueDisplayed: 1.00k  [0402]  (hidden comment: CRCW04021K00FKED)
R175  ValueDisplayed: 20.0  [0201_033]  (hidden comment: CRCW020120R0FNED)
R176  ValueDisplayed: 15.0k  [0402]  (hidden comment: RC0402FR-0715KL)
R177  ValueDisplayed: 10.0k  [0402L]  (hidden comment: CRCW040210K0FKED)
U13  DRV8376SNLGR  [NLG0028A-MFG]

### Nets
3V3: C165.2 J7.7 R171.2 R172.2
24V: C157.1 C158.1 C159.1 C160.1 U13.2(VM)
GND: C157.2 C158.2 C159.2 C161.1 C162.1 C163.2 C164.2 C165.1 C166.2 C167.2 C168.2 C169.2 C170.1 C171.1 J7.8 R177.1 U13.3(PGND) U13.7(PGND) U13.8(AGND) U13.29(Thermal_Pad)
GVDD4: C162.2 R176.2 U13.10(GVDD)
ADC_VREF: R174.1
DRV_FLT_AX4: R172.1 U13.12(~{FAULT})
DRV_nSleep: R163.1
DRV_OFF: R162.1
DRVOFF4: R162.2 U13.11(DRVOFF)
ENC_SPI_CS4: R169.1
I_A4: U13.27(SOA) ; off-sheet I_A4
I_B4: U13.26(SOB) ; off-sheet I_B4
I_C4: U13.25(SOC) ; off-sheet I_C4
INHA4: C163.1 R164.2 U13.14(INHA)
INHB4: C166.1 R167.2 U13.16(INHB)
INHC4: C168.1 R173.2 U13.18(INHC)
INLA4: C164.1 R165.2 U13.15(INLA)
INLB4: C167.1 R168.2 U13.17(INLB)
INLC4: C169.1 R175.2 U13.19(INLC)
nSLEEP4: R163.2 U13.13(~{SLEEP})
PWM_A4_H: R164.1
PWM_A4_L: R165.1
PWM_B4_H: R167.1
PWM_B4_L: R168.1
PWM_C4_H: R173.1
PWM_C4_L: R175.1
SPIB_CLK_AX3_4: J7.11 ; off-sheet SPIB_CLK_AX3_4
SPIB_PICO_AX3_4: J7.10 ; off-sheet SPIB_PICO_AX3_4
SPIB_POCI_AX34: R166.1
SPID_CLK_DRVCFG: U13.22(SCLK) ; off-sheet SPID_CLK_DRVCFG
SPID_CS4_DRV: R171.1 U13.23(~{SCS})
SPID_PICO_DRVCFG: U13.21(SDI) ; off-sheet SPID_PICO_DRVCFG
SPID_POCI_DRV: R170.1
U4: J7.1 J7.2 U13.4(OUTA)
V4: J7.3 J7.4 U13.5(OUTB)
VLIMIT4: C171.2 R176.1 R177.2 U13.28(ILIMIT)
W4: J7.5 J7.6 U13.6(OUTC)
NetC160_2: C160.2 U13.1(CP)
NetC161_2: C161.2 U13.9(AVDD)
NetC170_2: C170.2 R174.2 U13.24(VREF)
NetJ7_9: J7.9 R166.2
NetJ7_12: J7.12 R169.2
NetR170_2: R170.2 U13.20(SDO)

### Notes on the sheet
- AXIS4_DRV
- Gain = 2.5V/A; (0.4/1/2.5/5)
  ILIMIT = 0.6A;
  VLIMIT = (VREF/2) + (Iout x Gain/3) = 2V;
  SOx = (VREF/2) +/- Gain x Ioutx = 0V ~ 3V
  VLIMIT = GVDD x (10k/RLIM1 + 10K) -- > RLIM1 = 15Kohm

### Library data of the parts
C157 = CMP-0008802-2: CAP, CERM, 10 uF, 50 V, +/- 10%, X7R, 1206; Manufacturer: Samsung; TaMin_C: -55°C; Polarized: N; SizeAreaWB_mm2: 10.92; Value1: Unknown; U/M: EA; Value: 10uF; TaMax_C: 125°C; SizeZ_mm: 1.8; SizeX_mm: 3.2; SizeY_mm: 1.6; Cap_Case: 1206; SizeArea_mm2: 5.12; Cap_F: 10µF; AEC Category: Q200
C158 C159 = CMP-0064946-2: CAP, CERM, 0.1 uF, 50 V,+/- 10%, X7R, 0402; Manufacturer: TDK; TaMin_C: -55°C; Polarized: N; SizeAreaWB_mm2: 3; Value1: Unknown; U/M: EA; Value: 0.1uF; TaMax_C: 125°C; SizeZ_mm: 0.6; SizeX_mm: 1; SizeY_mm: 0.5; Cap_F: 100nF; AEC Category: Q200
C160 C161 C165 C170 C171 = CMP-0006326-2: CAP, CERM, 0.1 uF, 50 V, +/- 20%, X7R, AEC-Q200 Grade 1, 0402; Manufacturer: TDK; TaMin_C: -55°C; Polarized: N; SizeAreaWB_mm2: 3; Value1: Unknown; U/M: EA; Value: 0.1uF; TaMax_C: 125°C; SizeZ_mm: 0.6; SizeX_mm: 1; SizeY_mm: 0.5; AEC Qualified: Y; Cap_F: 100nF; AEC Category: Q200
C162 = CMP-0093200-1: 1µF ±10% 10V Ceramic Capacitor X7R 0402 (1005 Metric); Manufacturer: Cal-Chip Electronics; TempCo: 15%; SizeZ_mm: 0.6mm; AEC Qualified: No
C163 C164 C166-C169 = CMP-0009662-3: CAP, CERM, 47 pF, 25 V, +/- 5%, C0G/NP0, 0201; Manufacturer: MuRata; TaMin_C: -55°C; Polarized: N; SizeAreaWB_mm2: 2.08; Value1: Unknown; U/M: EA; Value: 47pF; TaMax_C: 125°C; SizeZ_mm: 0.33; SizeX_mm: 0.6; SizeY_mm: 0.3; Cap_Case: 0201; SizeArea_mm2: 0.18; AEC Category: Q200
J7 = CMP-0126588-1: Conn FPC Connector F 12 POS 0.5mm Solder Ver SMD T/R; Manufacturer: JST; ContactFinish: Gold,Nickel; Current_A: 500mA; Voltage_V: 50V; AEC Qualified: No; Conn Gender: Female; Conn Orientation: Vertical; Is Female: yes; SizeZ_mm: 3.3mm; Standoff Height: 0.13mm
R162 R163 R174 = CMP-0026071-3: RES, 1.00 k, 1%, 0.063 W, AEC-Q200 Grade 0, 0402; Manufacturer: Vishay-Dale; Power_W: 63mW; TempCo: 100 ppm/C; Value_Code: 1k00; Value: 1.00k; EIA_Code: E96; Res_ohm: 1k; SizeX_mm: 1; SizeY_mm: 0.5; SizeZ_mm: 0.6; Value2: 0.063W; AEC Qualified: Y; VDC_V: 50V; AEC Category: Q200; AEC Grade: 0
R164 R165 R167 R168 R173 R175 = CMP-0078192-1: RES, 20.0, 1%, 0.05 W, 0201; Manufacturer: Vishay-Dale; Value_Code: 20R0; SizeArea_mm2: 0.18; AEC Qualified: N; AEC Category: Q200; Res_ohm: 20; Value: 20.0; SizeZ_mm: 0.33; EIA_Code: E96; TempCo: 200 ppm/C; Power_W: 50mW; VDC_V: 30V; SizeY_mm: 0.3; Value2: 0.05W; U/M: EA; SizeX_mm: 0.6
R166 R169 R170 = CMP-0027015-3: RES, 22, 5%, 0.05 W, AEC-Q200 Grade 1, 0201; Manufacturer: Panasonic; Power_W: 50mW; TempCo: 200 ppm/C; Value_Code: 22R0; U/M: EA; Value: 22; EIA_Code: E24; SizeX_mm: 0.6; SizeY_mm: 0.3; SizeZ_mm: 0.26; Value2: 0.05W; SizeArea_mm2: 0.18; AEC Qualified: Y; AEC Grade: 1; AEC Category: Q200
R171 R172 = CMP-0028031-1: RES, 4.70 k, 1%, 0.05 W, 0201; Manufacturer: Yageo America; Power_W: 50mW; TempCo: 200 ppm/C; Value_Code: 4k70; U/M: EA; Value: 4.70k; Res_ohm: 4.7k; SizeX_mm: 0.6; SizeY_mm: 0.3; SizeZ_mm: 0.26; Value2: 0.05W; SizeArea_mm2: 0.18; AEC Qualified: N; VDC_V: 25V; AEC Category: Q200
R176 = CMP-0078583-1: RES, 15.0 k, 1%, 0.063 W, 0402; Manufacturer: Yageo America; Power_W: 63mW; Green_Lifecycle: Active; TempCo: 100 ppm/C; Value_Code: 15k0; Green_REACh: Passed; Value: 15.0k; EIA_Code: E96; Res_ohm: 15k; SizeX_mm: 1; SizeY_mm: 0.5; SizeZ_mm: 0.6; Value2: 0.063W; AEC Qualified: N; AEC Category: Q200
R177 = CMP-0025958-3: RES, 10.0 k, 1%, 0.063 W, AEC-Q200 Grade 0, 0402; Manufacturer: Vishay-Dale; Power_W: 63mW; TempCo: 100 ppm/C; Value_Code: 10k0; Value: 10.0k; EIA_Code: E96; Res_ohm: 10k; SizeX_mm: 1; SizeY_mm: 0.5; SizeZ_mm: 0.6; Value2: 0.063W; AEC Qualified: Y; VDC_V: 50V; AEC Category: Q200; AEC Grade: 0
U13 = CMP-0122073-1: Three-Phase Integrated FET Motor Driver; Manufacturer: Texas Instruments; SizeZ_mm: 1mm; AEC Qualified: No; Max Supply Voltage: 65V; Min Supply Voltage: 4.5V; Motor Type: Brushless DC; Nominal Supply Current: 6.6-8.2mA; Number Of Outputs: 3; Standoff Height: 0mm; Switching Frequency: 100kHz; TaMax_C: +125°C; TaMin_C: -40°C; TJmax_C: +150°C

## Sheet TIDA-010992_10_DRV_AXIS5.SchDoc
size 431 x 279 mm; Date: Not shown in title block; ApprovedBy: Not shown in title block; CheckedBy: Not shown in title block; Author: Not shown in title block; CompanyName: Not shown in title block; Engineer: Not shown in title block; Organization: Not shown in title block; Address1: Not shown in title block; Address2: Not shown in title block; Address3: Not shown in title block; Address4: Not shown in title block; DocumentNumber: 10; Revision: Use project parameter SCH_Rev; SheetNumber: 10; SheetTotal: 13; PageSetup: Record=PageOptions¦CenterHorizontal=True¦CenterVertical=True¦PrintScale=1.00¦XCorrection=1.00¦YCorrection=1.00¦PrintKind=0¦BorderSize=5000000¦LeftOffset=0¦BottomOffset=0¦Orientation=2¦PaperLength=1000¦PaperWidth=1000¦Scale=100¦PaperSource=15¦PrintQuality=600¦MediaType=1¦DitherType=10¦PaperKind=Letter¦PrintScaleMode=1

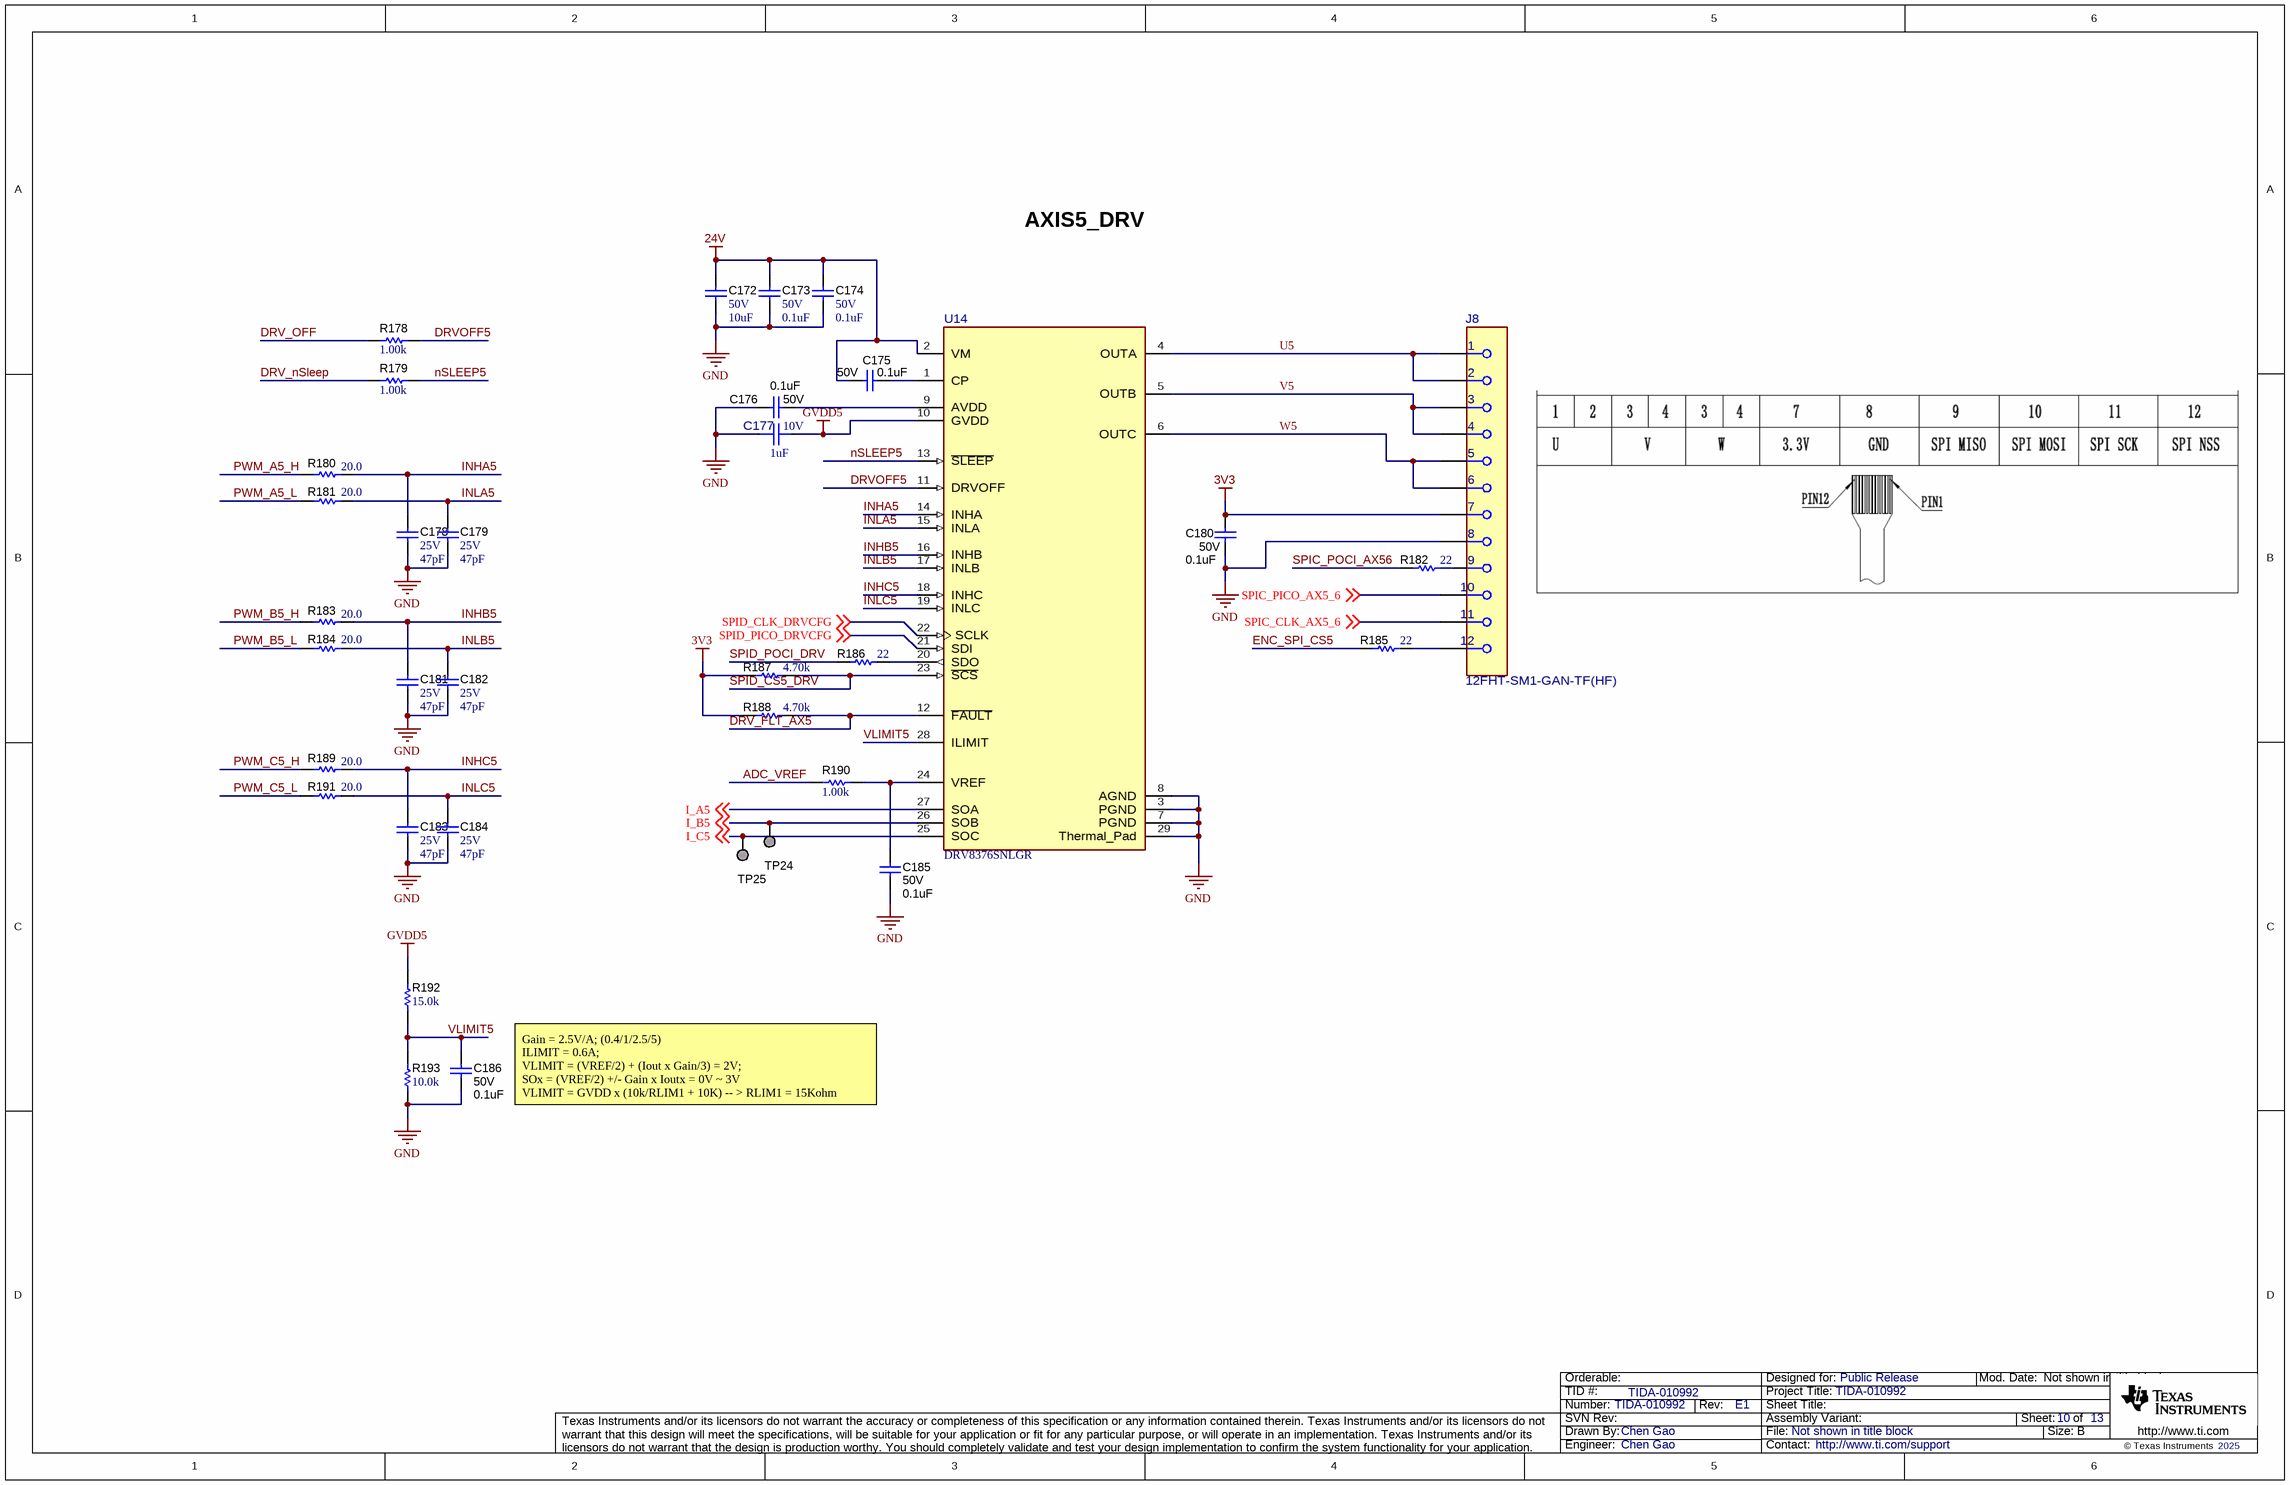
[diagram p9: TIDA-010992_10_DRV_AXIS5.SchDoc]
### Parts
C172  VDC_V: 50V  ValueDisplayed: 10uF  [1206_180]  (hidden comment: CL31B106KBHNNNE)
C173  VDC_V: 50V  ValueDisplayed: 0.1uF  [0402]  (hidden comment: C1005X7R1H104K050BE)
C174  VDC_V: 50V  ValueDisplayed: 0.1uF  [0402]  (hidden comment: C1005X7R1H104K050BE)
C175  VDC_V: 50V  ValueDisplayed: 0.1uF  [0402]  (hidden comment: CGA2B3X7R1H104M050BB)
C176  VDC_V: 50V  ValueDisplayed: 0.1uF  [0402]  (hidden comment: CGA2B3X7R1H104M050BB)
C177  VDC_V: 10V  ValueDisplayed: 1uF  [FP-GMC04X7R105K10NT_0402-MFG]  (hidden comment: GMC04X7R105K10NT)
C178  VDC_V: 25V  ValueDisplayed: 47pF  [0201_033]  (hidden comment: GRM0335C1E470JA01D)
C179  VDC_V: 25V  ValueDisplayed: 47pF  [0201_033]  (hidden comment: GRM0335C1E470JA01D)
C180  VDC_V: 50V  ValueDisplayed: 0.1uF  [0402]  (hidden comment: CGA2B3X7R1H104M050BB)
C181  VDC_V: 25V  ValueDisplayed: 47pF  [0201_033]  (hidden comment: GRM0335C1E470JA01D)
C182  VDC_V: 25V  ValueDisplayed: 47pF  [0201_033]  (hidden comment: GRM0335C1E470JA01D)
C183  VDC_V: 25V  ValueDisplayed: 47pF  [0201_033]  (hidden comment: GRM0335C1E470JA01D)
C184  VDC_V: 25V  ValueDisplayed: 47pF  [0201_033]  (hidden comment: GRM0335C1E470JA01D)
C185  VDC_V: 50V  ValueDisplayed: 0.1uF  [0402]  (hidden comment: CGA2B3X7R1H104M050BB)
C186  VDC_V: 50V  ValueDisplayed: 0.1uF  [0402]  (hidden comment: CGA2B3X7R1H104M050BB)
J8  12FHT-SM1-GAN-TF(HF)  [FP-12FHT-SM1-GAN-TF(HF)_CONN_FPC_12-MFG]
R178  ValueDisplayed: 1.00k  [0402]  (hidden comment: CRCW04021K00FKED)
R179  ValueDisplayed: 1.00k  [0402]  (hidden comment: CRCW04021K00FKED)
R180  ValueDisplayed: 20.0  [0201_033]  (hidden comment: CRCW020120R0FNED)
R181  ValueDisplayed: 20.0  [0201_033]  (hidden comment: CRCW020120R0FNED)
R182  ValueDisplayed: 22  [0201]  (hidden comment: ERJ-1GNJ220C)
R183  ValueDisplayed: 20.0  [0201_033]  (hidden comment: CRCW020120R0FNED)
R184  ValueDisplayed: 20.0  [0201_033]  (hidden comment: CRCW020120R0FNED)
R185  ValueDisplayed: 22  [0201]  (hidden comment: ERJ-1GNJ220C)
R186  ValueDisplayed: 22  [0201]  (hidden comment: ERJ-1GNJ220C)
R187  ValueDisplayed: 4.70k  [0201]  (hidden comment: RC0201FR-7D4K7L)
R188  ValueDisplayed: 4.70k  [0201]  (hidden comment: RC0201FR-7D4K7L)
R189  ValueDisplayed: 20.0  [0201_033]  (hidden comment: CRCW020120R0FNED)
R190  ValueDisplayed: 1.00k  [0402]  (hidden comment: CRCW04021K00FKED)
R191  ValueDisplayed: 20.0  [0201_033]  (hidden comment: CRCW020120R0FNED)
R192  ValueDisplayed: 15.0k  [0402]  (hidden comment: RC0402FR-0715KL)
R193  ValueDisplayed: 10.0k  [0402L]  (hidden comment: CRCW040210K0FKED)
TP24  TP_SM_1MM  [TP_SM_1MM]  (value not drawn)  (no BOM)
TP25  TP_SM_1MM  [TP_SM_1MM]  (value not drawn)  (no BOM)
U14  DRV8376SNLGR  [NLG0028A-MFG]

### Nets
3V3: C180.2 J8.7 R187.2 R188.2
24V: C172.1 C173.1 C174.1 C175.1 U14.2(VM)
GND: C172.2 C173.2 C174.2 C176.1 C177.1 C178.2 C179.2 C180.1 C181.2 C182.2 C183.2 C184.2 C185.1 C186.1 J8.8 R193.1 U14.3(PGND) U14.7(PGND) U14.8(AGND) U14.29(Thermal_Pad)
GVDD5: C177.2 R192.2 U14.10(GVDD)
ADC_VREF: R190.1
DRV_FLT_AX5: R188.1 U14.12(~{FAULT})
DRV_nSleep: R179.1
DRV_OFF: R178.1
DRVOFF5: R178.2 U14.11(DRVOFF)
ENC_SPI_CS5: R185.1
I_A5: U14.27(SOA) ; off-sheet I_A5
I_B5: TP24.1 U14.26(SOB) ; off-sheet I_B5
I_C5: TP25.1 U14.25(SOC) ; off-sheet I_C5
INHA5: C178.1 R180.2 U14.14(INHA)
INHB5: C181.1 R183.2 U14.16(INHB)
INHC5: C183.1 R189.2 U14.18(INHC)
INLA5: C179.1 R181.2 U14.15(INLA)
INLB5: C182.1 R184.2 U14.17(INLB)
INLC5: C184.1 R191.2 U14.19(INLC)
nSLEEP5: R179.2 U14.13(~{SLEEP})
PWM_A5_H: R180.1
PWM_A5_L: R181.1
PWM_B5_H: R183.1
PWM_B5_L: R184.1
PWM_C5_H: R189.1
PWM_C5_L: R191.1
SPIC_CLK_AX5_6: J8.11 ; off-sheet SPIC_CLK_AX5_6
SPIC_PICO_AX5_6: J8.10 ; off-sheet SPIC_PICO_AX5_6
SPIC_POCI_AX56: R182.1
SPID_CLK_DRVCFG: U14.22(SCLK) ; off-sheet SPID_CLK_DRVCFG
SPID_CS5_DRV: R187.1 U14.23(~{SCS})
SPID_PICO_DRVCFG: U14.21(SDI) ; off-sheet SPID_PICO_DRVCFG
SPID_POCI_DRV: R186.1
U5: J8.1 J8.2 U14.4(OUTA)
V5: J8.3 J8.4 U14.5(OUTB)
VLIMIT5: C186.2 R192.1 R193.2 U14.28(ILIMIT)
W5: J8.5 J8.6 U14.6(OUTC)
NetC175_2: C175.2 U14.1(CP)
NetC176_2: C176.2 U14.9(AVDD)
NetC185_2: C185.2 R190.2 U14.24(VREF)
NetJ8_9: J8.9 R182.2
NetJ8_12: J8.12 R185.2
NetR186_2: R186.2 U14.20(SDO)

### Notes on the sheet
- AXIS5_DRV
- Gain = 2.5V/A; (0.4/1/2.5/5)
  ILIMIT = 0.6A;
  VLIMIT = (VREF/2) + (Iout x Gain/3) = 2V;
  SOx = (VREF/2) +/- Gain x Ioutx = 0V ~ 3V
  VLIMIT = GVDD x (10k/RLIM1 + 10K) -- > RLIM1 = 15Kohm

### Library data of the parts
C172 = CMP-0008802-2: as C157 on sheet TIDA-010992_09_DRV_AXIS4
C173 C174 = CMP-0064946-2: as C158 on sheet TIDA-010992_09_DRV_AXIS4
C175 C176 C180 C185 C186 = CMP-0006326-2: as C160 on sheet TIDA-010992_09_DRV_AXIS4
C177 = CMP-0093200-1: as C162 on sheet TIDA-010992_09_DRV_AXIS4
C178 C179 C181-C184 = CMP-0009662-3: as C163 on sheet TIDA-010992_09_DRV_AXIS4
J8 = CMP-0126588-1: as J7 on sheet TIDA-010992_09_DRV_AXIS4
R178 R179 R190 = CMP-0026071-3: as R162 on sheet TIDA-010992_09_DRV_AXIS4
R180 R181 R183 R184 R189 R191 = CMP-0078192-1: as R164 on sheet TIDA-010992_09_DRV_AXIS4
R182 R185 R186 = CMP-0027015-3: as R166 on sheet TIDA-010992_09_DRV_AXIS4
R187 R188 = CMP-0028031-1: as R171 on sheet TIDA-010992_09_DRV_AXIS4
R192 = CMP-0078583-1: as R176 on sheet TIDA-010992_09_DRV_AXIS4
R193 = CMP-0025958-3: as R177 on sheet TIDA-010992_09_DRV_AXIS4
TP24 TP25 = CMP-0003825-1: 1mm Test Point, SMT; Manufacturer: Any
U14 = CMP-0122073-1: as U13 on sheet TIDA-010992_09_DRV_AXIS4

## Sheet TIDA-010992_11_DRV_AXIS6.SchDoc
size 431 x 279 mm; Date: Not shown in title block; ApprovedBy: Not shown in title block; CheckedBy: Not shown in title block; Author: Not shown in title block; CompanyName: Not shown in title block; Engineer: Not shown in title block; Organization: Not shown in title block; Address1: Not shown in title block; Address2: Not shown in title block; Address3: Not shown in title block; Address4: Not shown in title block; DocumentNumber: 11; Revision: Use project parameter SCH_Rev; SheetNumber: 11; SheetTotal: 13; PageSetup: Record=PageOptions¦CenterHorizontal=True¦CenterVertical=True¦PrintScale=1.00¦XCorrection=1.00¦YCorrection=1.00¦PrintKind=0¦BorderSize=5000000¦LeftOffset=0¦BottomOffset=0¦Orientation=2¦PaperLength=1000¦PaperWidth=1000¦Scale=100¦PaperSource=15¦PrintQuality=600¦MediaType=1¦DitherType=10¦PaperKind=Letter¦PrintScaleMode=1

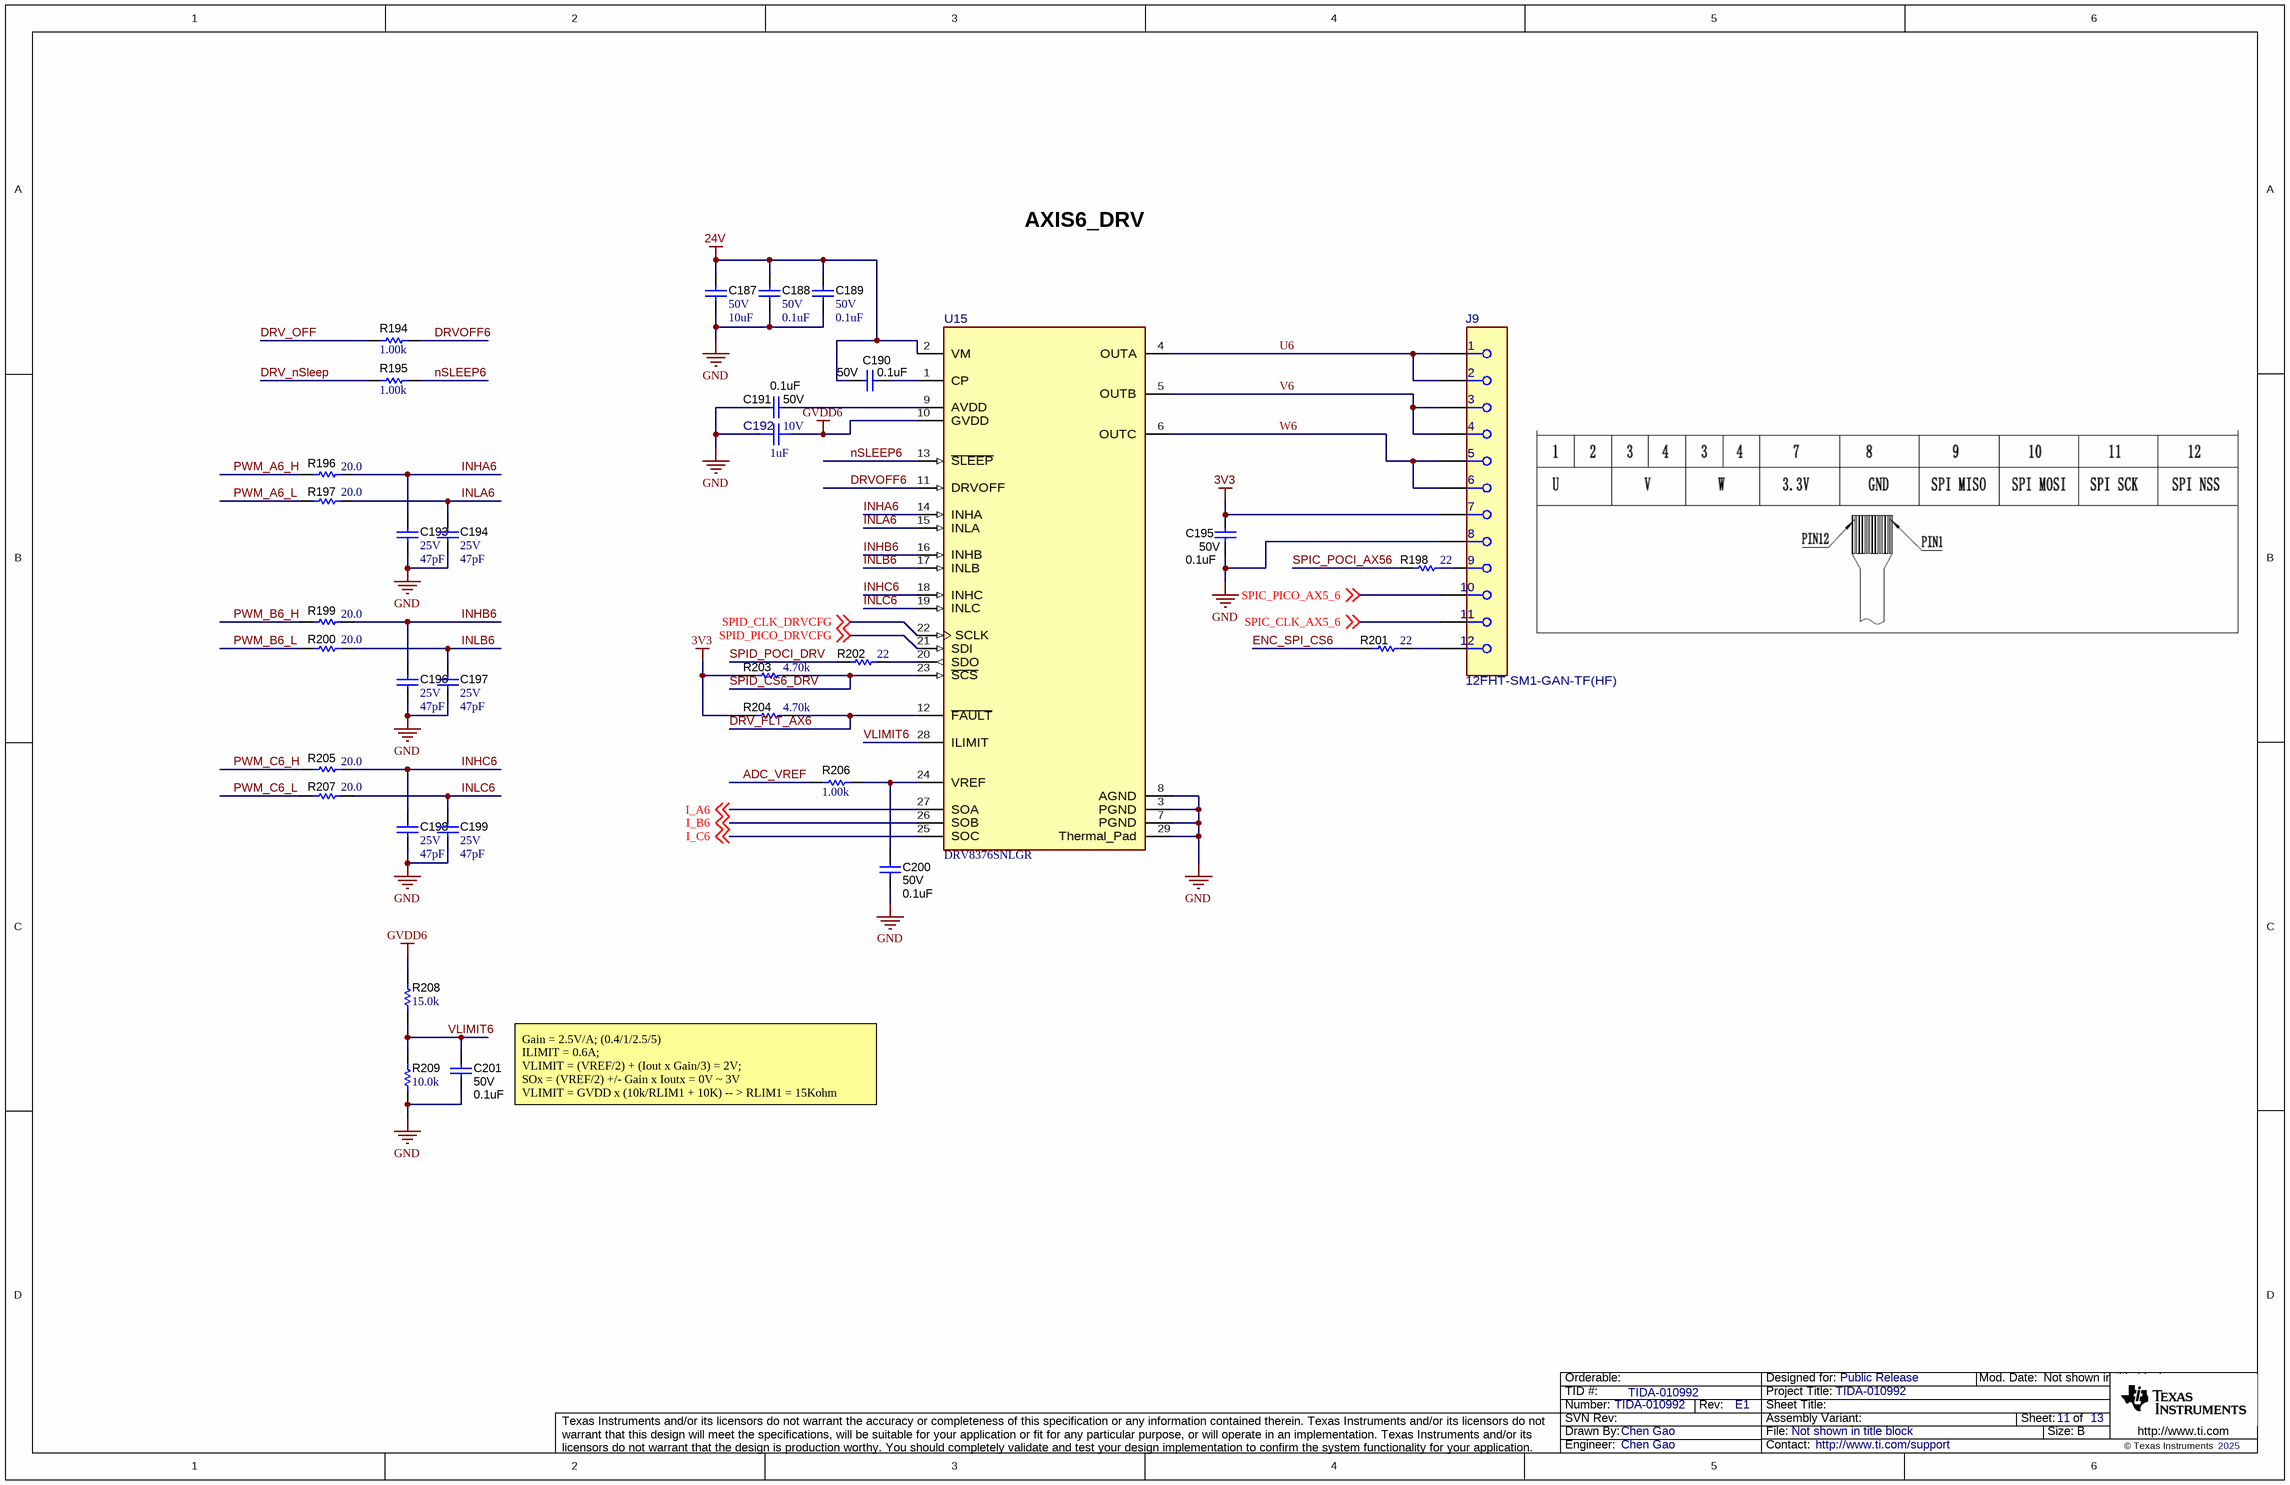
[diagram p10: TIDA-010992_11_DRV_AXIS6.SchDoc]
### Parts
C187  VDC_V: 50V  ValueDisplayed: 10uF  [1206_180]  (hidden comment: CL31B106KBHNNNE)
C188  VDC_V: 50V  ValueDisplayed: 0.1uF  [0402]  (hidden comment: C1005X7R1H104K050BE)
C189  VDC_V: 50V  ValueDisplayed: 0.1uF  [0402]  (hidden comment: C1005X7R1H104K050BE)
C190  VDC_V: 50V  ValueDisplayed: 0.1uF  [0402]  (hidden comment: CGA2B3X7R1H104M050BB)
C191  VDC_V: 50V  ValueDisplayed: 0.1uF  [0402]  (hidden comment: CGA2B3X7R1H104M050BB)
C192  VDC_V: 10V  ValueDisplayed: 1uF  [FP-GMC04X7R105K10NT_0402-MFG]  (hidden comment: GMC04X7R105K10NT)
C193  VDC_V: 25V  ValueDisplayed: 47pF  [0201_033]  (hidden comment: GRM0335C1E470JA01D)
C194  VDC_V: 25V  ValueDisplayed: 47pF  [0201_033]  (hidden comment: GRM0335C1E470JA01D)
C195  VDC_V: 50V  ValueDisplayed: 0.1uF  [0402]  (hidden comment: CGA2B3X7R1H104M050BB)
C196  VDC_V: 25V  ValueDisplayed: 47pF  [0201_033]  (hidden comment: GRM0335C1E470JA01D)
C197  VDC_V: 25V  ValueDisplayed: 47pF  [0201_033]  (hidden comment: GRM0335C1E470JA01D)
C198  VDC_V: 25V  ValueDisplayed: 47pF  [0201_033]  (hidden comment: GRM0335C1E470JA01D)
C199  VDC_V: 25V  ValueDisplayed: 47pF  [0201_033]  (hidden comment: GRM0335C1E470JA01D)
C200  VDC_V: 50V  ValueDisplayed: 0.1uF  [0402]  (hidden comment: CGA2B3X7R1H104M050BB)
C201  VDC_V: 50V  ValueDisplayed: 0.1uF  [0402]  (hidden comment: CGA2B3X7R1H104M050BB)
J9  12FHT-SM1-GAN-TF(HF)  [FP-12FHT-SM1-GAN-TF(HF)_CONN_FPC_12-MFG]
R194  ValueDisplayed: 1.00k  [0402]  (hidden comment: CRCW04021K00FKED)
R195  ValueDisplayed: 1.00k  [0402]  (hidden comment: CRCW04021K00FKED)
R196  ValueDisplayed: 20.0  [0201_033]  (hidden comment: CRCW020120R0FNED)
R197  ValueDisplayed: 20.0  [0201_033]  (hidden comment: CRCW020120R0FNED)
R198  ValueDisplayed: 22  [0201]  (hidden comment: ERJ-1GNJ220C)
R199  ValueDisplayed: 20.0  [0201_033]  (hidden comment: CRCW020120R0FNED)
R200  ValueDisplayed: 20.0  [0201_033]  (hidden comment: CRCW020120R0FNED)
R201  ValueDisplayed: 22  [0201]  (hidden comment: ERJ-1GNJ220C)
R202  ValueDisplayed: 22  [0201]  (hidden comment: ERJ-1GNJ220C)
R203  ValueDisplayed: 4.70k  [0201]  (hidden comment: RC0201FR-7D4K7L)
R204  ValueDisplayed: 4.70k  [0201]  (hidden comment: RC0201FR-7D4K7L)
R205  ValueDisplayed: 20.0  [0201_033]  (hidden comment: CRCW020120R0FNED)
R206  ValueDisplayed: 1.00k  [0402]  (hidden comment: CRCW04021K00FKED)
R207  ValueDisplayed: 20.0  [0201_033]  (hidden comment: CRCW020120R0FNED)
R208  ValueDisplayed: 15.0k  [0402]  (hidden comment: RC0402FR-0715KL)
R209  ValueDisplayed: 10.0k  [0402L]  (hidden comment: CRCW040210K0FKED)
U15  DRV8376SNLGR  [NLG0028A-MFG]

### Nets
3V3: C195.2 J9.7 R203.2 R204.2
24V: C187.1 C188.1 C189.1 C190.1 U15.2(VM)
GND: C187.2 C188.2 C189.2 C191.1 C192.1 C193.2 C194.2 C195.1 C196.2 C197.2 C198.2 C199.2 C200.1 C201.1 J9.8 R209.1 U15.3(PGND) U15.7(PGND) U15.8(AGND) U15.29(Thermal_Pad)
GVDD6: C192.2 R208.2 U15.10(GVDD)
ADC_VREF: R206.1
DRV_FLT_AX6: R204.1 U15.12(~{FAULT})
DRV_nSleep: R195.1
DRV_OFF: R194.1
DRVOFF6: R194.2 U15.11(DRVOFF)
ENC_SPI_CS6: R201.1
I_A6: U15.27(SOA) ; off-sheet I_A6
I_B6: U15.26(SOB) ; off-sheet I_B6
I_C6: U15.25(SOC) ; off-sheet I_C6
INHA6: C193.1 R196.2 U15.14(INHA)
INHB6: C196.1 R199.2 U15.16(INHB)
INHC6: C198.1 R205.2 U15.18(INHC)
INLA6: C194.1 R197.2 U15.15(INLA)
INLB6: C197.1 R200.2 U15.17(INLB)
INLC6: C199.1 R207.2 U15.19(INLC)
nSLEEP6: R195.2 U15.13(~{SLEEP})
PWM_A6_H: R196.1
PWM_A6_L: R197.1
PWM_B6_H: R199.1
PWM_B6_L: R200.1
PWM_C6_H: R205.1
PWM_C6_L: R207.1
SPIC_CLK_AX5_6: J9.11 ; off-sheet SPIC_CLK_AX5_6
SPIC_PICO_AX5_6: J9.10 ; off-sheet SPIC_PICO_AX5_6
SPIC_POCI_AX56: R198.1
SPID_CLK_DRVCFG: U15.22(SCLK) ; off-sheet SPID_CLK_DRVCFG
SPID_CS6_DRV: R203.1 U15.23(~{SCS})
SPID_PICO_DRVCFG: U15.21(SDI) ; off-sheet SPID_PICO_DRVCFG
SPID_POCI_DRV: R202.1
U6: J9.1 J9.2 U15.4(OUTA)
V6: J9.3 J9.4 U15.5(OUTB)
VLIMIT6: C201.2 R208.1 R209.2 U15.28(ILIMIT)
W6: J9.5 J9.6 U15.6(OUTC)
NetC190_2: C190.2 U15.1(CP)
NetC191_2: C191.2 U15.9(AVDD)
NetC200_2: C200.2 R206.2 U15.24(VREF)
NetJ9_9: J9.9 R198.2
NetJ9_12: J9.12 R201.2
NetR202_2: R202.2 U15.20(SDO)

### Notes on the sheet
- AXIS6_DRV
- Gain = 2.5V/A; (0.4/1/2.5/5)
  ILIMIT = 0.6A;
  VLIMIT = (VREF/2) + (Iout x Gain/3) = 2V;
  SOx = (VREF/2) +/- Gain x Ioutx = 0V ~ 3V
  VLIMIT = GVDD x (10k/RLIM1 + 10K) -- > RLIM1 = 15Kohm

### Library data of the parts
C187 = CMP-0008802-2: as C157 on sheet TIDA-010992_09_DRV_AXIS4
C188 C189 = CMP-0064946-2: as C158 on sheet TIDA-010992_09_DRV_AXIS4
C190 C191 C195 C200 C201 = CMP-0006326-2: as C160 on sheet TIDA-010992_09_DRV_AXIS4
C192 = CMP-0093200-1: as C162 on sheet TIDA-010992_09_DRV_AXIS4
C193 C194 C196-C199 = CMP-0009662-3: as C163 on sheet TIDA-010992_09_DRV_AXIS4
J9 = CMP-0126588-1: as J7 on sheet TIDA-010992_09_DRV_AXIS4
R194 R195 R206 = CMP-0026071-3: as R162 on sheet TIDA-010992_09_DRV_AXIS4
R196 R197 R199 R200 R205 R207 = CMP-0078192-1: as R164 on sheet TIDA-010992_09_DRV_AXIS4
R198 R201 R202 = CMP-0027015-3: as R166 on sheet TIDA-010992_09_DRV_AXIS4
R203 R204 = CMP-0028031-1: as R171 on sheet TIDA-010992_09_DRV_AXIS4
R208 = CMP-0078583-1: as R176 on sheet TIDA-010992_09_DRV_AXIS4
R209 = CMP-0025958-3: as R177 on sheet TIDA-010992_09_DRV_AXIS4
U15 = CMP-0122073-1: as U13 on sheet TIDA-010992_09_DRV_AXIS4

## Sheet TIDA-010992_12_Connectors.SchDoc
size 431 x 279 mm; Date: Not shown in title block; ApprovedBy: Not shown in title block; CheckedBy: Not shown in title block; Author: Not shown in title block; CompanyName: Not shown in title block; Engineer: Not shown in title block; Organization: Not shown in title block; Address1: Not shown in title block; Address2: Not shown in title block; Address3: Not shown in title block; Address4: Not shown in title block; DocumentNumber: 12; Revision: Use project parameter SCH_Rev; SheetNumber: 12; SheetTotal: 13; PageSetup: Record=PageOptions¦CenterHorizontal=True¦CenterVertical=True¦PrintScale=1.00¦XCorrection=1.00¦YCorrection=1.00¦PrintKind=0¦BorderSize=5000000¦LeftOffset=0¦BottomOffset=0¦Orientation=2¦PaperLength=1000¦PaperWidth=1000¦Scale=100¦PaperSource=15¦PrintQuality=600¦MediaType=1¦DitherType=10¦PaperKind=Letter¦PrintScaleMode=1

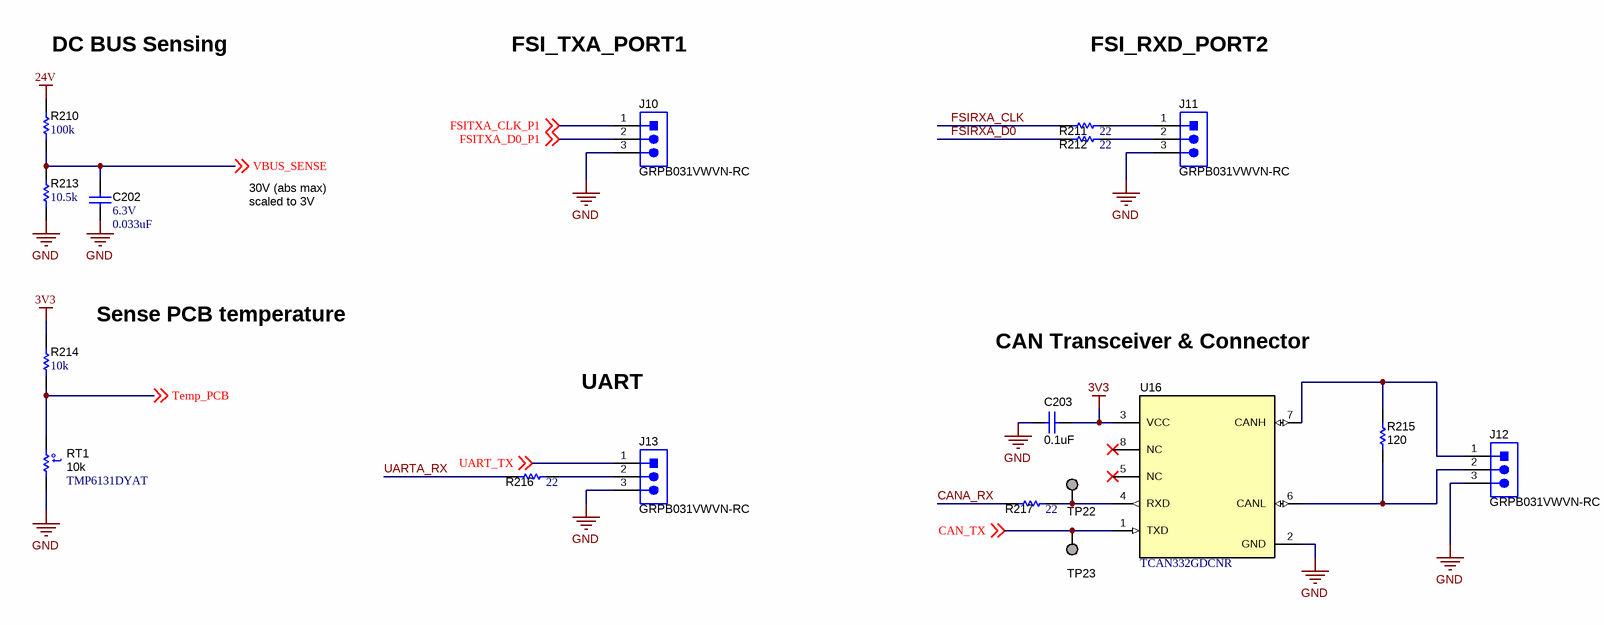
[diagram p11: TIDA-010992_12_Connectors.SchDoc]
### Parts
C202  VDC_V: 6.3V  ValueDisplayed: 0.033uF  [0201]  (hidden comment: GRM033R60J333KE01D)
C203  ValueDisplayed: 0.1uF  [0402]  (hidden comment: 885012205037)
J10  GRPB031VWVN-RC  [Sullins_GRPB031VWVN-RC]
J11  GRPB031VWVN-RC  [Sullins_GRPB031VWVN-RC]
J12  GRPB031VWVN-RC  [Sullins_GRPB031VWVN-RC]
J13  GRPB031VWVN-RC  [Sullins_GRPB031VWVN-RC]
R210  ValueDisplayed: 100k  [0402]  (hidden comment: CMP-0025950-3)
R211  ValueDisplayed: 22  [0201]  (hidden comment: ERJ-1GNJ220C)
R212  ValueDisplayed: 22  [0201]  (hidden comment: ERJ-1GNJ220C)
R213  ValueDisplayed: 10.5k  [0402]  (hidden comment: RC0402FR-0710K5L)
R214  ValueDisplayed: 10k  [0402]  (hidden comment: CMP-0026825-5)
R215  ValueDisplayed: 120  [0603]  (hidden comment: RC0603FR-07120RL)
R216  ValueDisplayed: 22  [0201]  (hidden comment: ERJ-1GNJ220C)
R217  ValueDisplayed: 22  [0201]  (hidden comment: ERJ-1GNJ220C)
RT1  value 10k  [DYA0002A-MFG]  (hidden comment: TMP6131DYAT)
TP22  TESTPOINT  [TP_25MIL-SMT]  (value not drawn)  (no BOM)
TP23  TESTPOINT  [TP_25MIL-SMT]  (value not drawn)  (no BOM)
U16  TCAN332GDCNR  [DCN0008A_N]

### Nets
3V3: C203.2 R214.2 U16.3(VCC)
24V: R210.2
GND: C202.2 C203.1 J10.3 J11.3 J12.3 J13.3 R213.1 RT1.1 U16.2(GND)
CAN_TX: TP23.1 U16.1(TXD) ; off-sheet CAN_TX
CANA_RX: R217.1
FSIRXA_CLK: R211.1
FSIRXA_D0: R212.1
FSITXA_CLK_P1: J10.1 ; off-sheet FSITXA_CLK_P1
FSITXA_D0_P1: J10.2 ; off-sheet FSITXA_D0_P1
Temp_PCB: R214.1 RT1.2 ; off-sheet Temp_PCB
UART_TX: J13.1 ; off-sheet UART_TX
UARTA_RX: R216.1
VBUS_SENSE: C202.1 R210.1 R213.2 ; off-sheet VBUS_SENSE
NetJ11_1: J11.1 R211.2
NetJ11_2: J11.2 R212.2
NetJ12_1: J12.1 R215.2 U16.7(CANH)
NetJ12_2: J12.2 R215.1 U16.6(CANL)
NetJ13_2: J13.2 R216.2
NetR217_2: R217.2 TP22.1 U16.4(RXD)

Not connected (* = marked no-connect by the designer): U16 5(NC)* 8(NC)*

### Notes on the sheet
- DC BUS Sensing
- FSI_TXA_PORT1
- FSI_RXD_PORT2
- 30V (abs max) scaled to 3V
- Sense PCB temperature
- UART
- CAN Transceiver & Connector

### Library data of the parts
C202 = CMP-0009699-1: CAP, CERM, 0.033 uF, 6.3 V, +/- 10%, X5R, 0201; Manufacturer: MuRata; TaMin_C: -55°C; Polarized: N; SizeAreaWB_mm2: 2.08; Value1: Unknown; U/M: EA; TaMax_C: 85°C; SizeZ_mm: 0.26; SizeX_mm: 0.6; SizeY_mm: 0.3; SizeArea_mm2: 0.18; Cap_F: 33nF; AEC Category: Q200
C203 = CMP-0006228-2: CAP, CERM, 0.1 uF, 16 V, +/- 10%, X7R, 0402; Manufacturer: Wurth Elektronik; TaMin_C: -55°C; Polarized: N; SizeAreaWB_mm2: 3; Value1: Unknown; U/M: EA; Value: 0.1uF; TaMax_C: 125°C; SizeZ_mm: 0.6; SizeX_mm: 1; SizeY_mm: 0.5; Value2: 16V; Cap_F: 100nF; AEC Category: Q200
J10-J13 = CMP-0054564-1: Header, 50mil, 3x1, Gold, TH; Manufacturer: Sullins Connector Solutions; CNHeader: TRUE; Green_Lifecycle: Not Set; Shrouded: N; Gender: Male; Green_REACh: Incomplete; Row_Count: 1; CT: FALSE
R210 = CMP-0025950-3: RES, 100 k, 1%, 0.063 W, AEC-Q200 Grade 0, 0402; PartNumber: CRCW0402100KFKED; Manufacturer: Vishay-Dale; Value: 100k; Power_W: 63mW; Value2: 0.063W; VDC_V: 50V; TempCo: 100 ppm/C; EIA_Code: E96; AEC Category: Q200; AEC Qualified: Y; AEC Grade: 0; SizeArea_mm2: 0.5; SizeX_mm: 1; SizeZ_mm: 0.6
R211 R212 R216 R217 = CMP-0027015-3: as R166 on sheet TIDA-010992_09_DRV_AXIS4
R213 = CMP-0078781-1: RES, 10.5 k, 1%, 0.063 W, 0402; Manufacturer: Yageo America; Value_Code: 10k5; SizeArea_mm2: 0.5; AEC Qualified: N; AEC Category: Q200; Value: 10.5k; SizeZ_mm: 0.6; EIA_Code: E96; TempCo: 100 ppm/C; Power_W: 63mW; VDC_V: 50V; Value2: 0.063W; SizeX_mm: 1
R214 = CMP-0026825-5: RES, 10 k, 5%, 0.063 W, AEC-Q200 Grade 0, 0402; PartNumber: CRCW040210K0JNED; Manufacturer: Vishay-Dale; Value: 10k; Value_Code: 10k0; Power_W: 63mW; Value2: 0.063W; VDC_V: 50V; TempCo: 200 ppm/C; SizeArea_mm2: 0.5; SizeX_mm: 1; SizeZ_mm: 0.6; EIA_Code: E24; AEC Category: Q200; AEC Qualified: Y; AEC Grade: 0
R215 = CMP-0022769-3: RES, 120, 1%, 0.1 W, 0603; Manufacturer: Yageo America; Value: 120; Value_Code: 120R; Power_W: 100mW; Value2: 0.1W; VDC_V: 150V; TempCo: 200 ppm/C; SizeArea_mm2: 1.28; SizeX_mm: 1.6; SizeY_mm: 0.8; SizeZ_mm: 1; U/M: EA; AEC Category: Q200
RT1 = CMP-0091865-2: ±1% tolerance 10kΩ linear thermistor available in 0402 and 0603 package options 2-SOT-5X3 -40 to 125; Manufacturer: Texas Instruments; Max Current: 400uA; AEC Qualified: No; TJmax_C: +155°C; TaMin_C: -40°C; TempCo: 6400ppm/°C; TaMax_C: +125°C; VDC_V: 5.5V; SizeZ_mm: 0.77mm; AEC Category: Q200; CompType: IC
TP22 TP23 = CMP-0078143-3: TEST POINT.  No entry in BOM.
U16 = CMP-0080976-2: 3.3-V CAN Transceivers with CAN FD (Flexible Data Rate), DCN0008A (SOT-23-8); Alternate PartNumber: TCAN332GDCNT; Alternate Manufacturer: Texas Instruments; SizeAreaWB_mm2: 15.21; SizeZ_mm: 1.1; SizeX_mm: 2.9; SizeArea_mm2: 8.41; CompType: IC; AEC Qualified: N; AEC Category: Q200

## Sheet TIDA-010992_Hardware.SchDoc
size 431 x 279 mm; Date: Not shown in title block; ApprovedBy: Not shown in title block; CheckedBy: Not shown in title block; Author: Not shown in title block; CompanyName: Not shown in title block; Engineer: Not shown in title block; Organization: Not shown in title block; Address1: Not shown in title block; Address2: Not shown in title block; Address3: Not shown in title block; Address4: Not shown in title block; DocumentNumber: 13; Revision: Use project parameter SCH_Rev; SheetNumber: 13; SheetTotal: 13; PageSetup: Record=PageOptions¦CenterHorizontal=True¦CenterVertical=True¦PrintScale=1.00¦XCorrection=1.00¦YCorrection=1.00¦PrintKind=0¦BorderSize=5000000¦LeftOffset=0¦BottomOffset=0¦Orientation=2¦PaperLength=1000¦PaperWidth=1000¦Scale=100¦PaperSource=15¦PrintQuality=600¦MediaType=1¦DitherType=10¦PaperKind=Letter¦PrintScaleMode=1

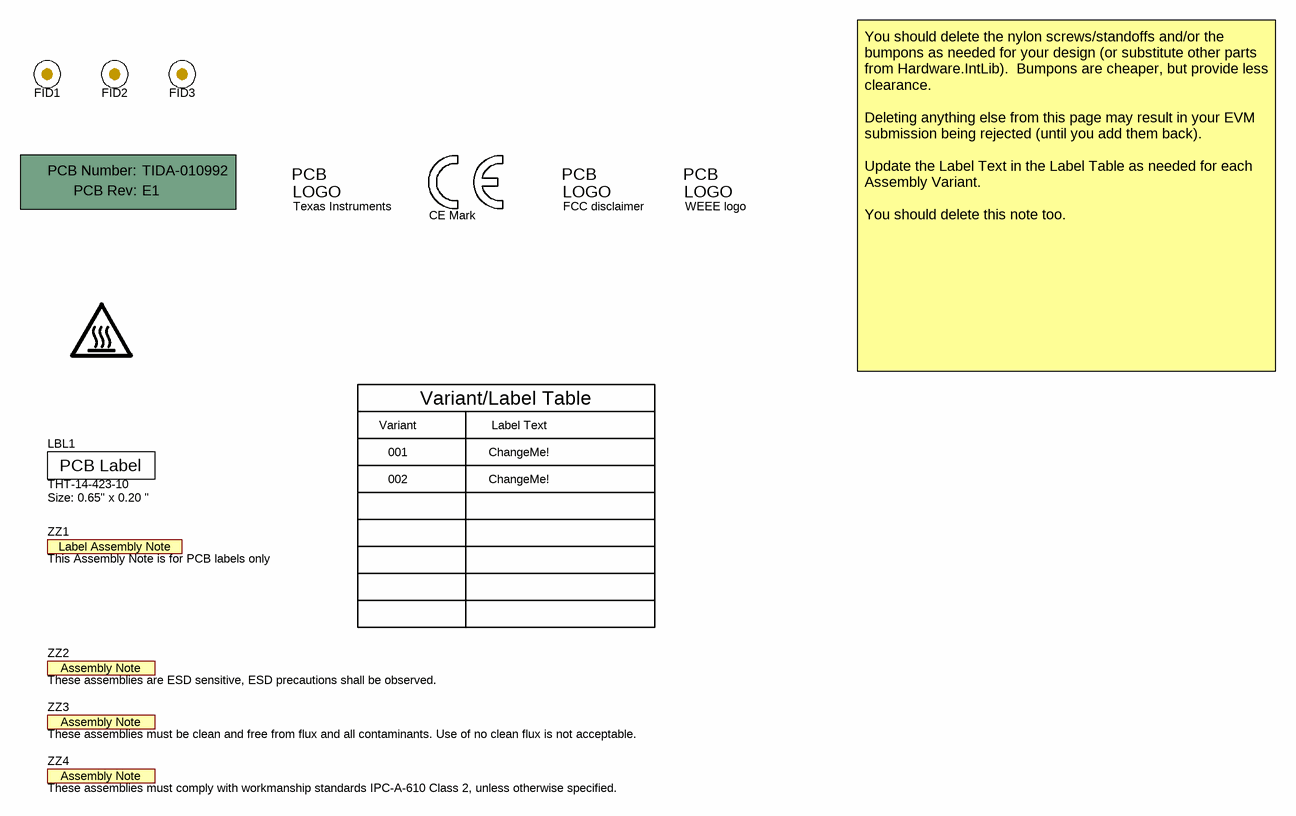
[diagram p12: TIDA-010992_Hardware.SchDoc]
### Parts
1  CAUTION HOT SURFACE  [IEC_HotSurface_Small]  (value not drawn)  (no BOM)
!PCB1  Printed Circuit Board  (value not drawn)  (mechanical)
FID1  Fiducial  [Fiducial10-20]  (value not drawn)
FID2  Fiducial  [Fiducial10-20]  (value not drawn)
FID3  Fiducial  [Fiducial10-20]  (value not drawn)
LBL1  THT-14-423-10  Note: Size: 0.65" x 0.20 "  [Label_650x200]
Logo1  CE Mark  [CE_Mark_5mm]  (no BOM)
Logo2  Texas Instruments  [TI_Symbol_Overlay_Small]  (no BOM)
Logo3  FCC disclaimer  [FCC_disclaimer]  (no BOM)
Logo4  WEEE logo  [WEEE_Minimum]  (no BOM)
ZZ1  This Assembly Note is for PCB labels only  [AssemblyNoteLabel]  (no BOM)
ZZ2  These assemblies are ESD sensitive, ESD precautions shall be observed.  [AssemblyNote]  (no BOM)
ZZ3  These assemblies must be clean and free from flux and all contaminants. Use of no clean flux is not acceptable.  [AssemblyNote]  (no BOM)
ZZ4  These assemblies must comply with workmanship standards IPC-A-610 Class 2, unless otherwise specified.  [AssemblyNote]  (no BOM)

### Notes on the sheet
- Variant
- Variant/Label Table
- Label Text
- You should delete the nylon screws/standoffs and/or the bumpons as needed for your design (or substitute other parts from Hardware.IntLib).  Bumpons are cheaper, but provide less clearance.
  Deleting anything else from this page may result in your EVM submission being rejected (until you add them back).
  Update the Label Text in the Label Table as needed for each Assembly Variant.
  You should delete this note too.
- 001
- 002
- ChangeMe!

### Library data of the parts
1 = CMP-0074837-1: IEC 61010-1 Hot Surface Warning; SymbolCreator: a0412235
!PCB1 = CMP-0003618-2: Manufacturer: Any; PartNumber: TIDA-010992
FID1-FID3 = CMP-0077181-1: Fiducial mark.  There is nothing to buy or mount.
LBL1 = CMP-0003625-1: Thermal Transfer Printable Labels, 0.650" W x 0.200" H - 10,000 per roll; Manufacturer: Brady; CompType: Label
Logo1 = CMP-0074844-1: SymbolCreator: a0412235
Logo2 = CMP-0074838-1: Texas Instrument Corporate Signature; SymbolCreator: a0412235; Lib Reference: TI_Logo; Library Reference: Logo
Logo3 = CMP-0074847-1: FCC_disclaimer; Library Reference: Logo
Logo4 = CMP-0074769-1
ZZ1 = CMP-0003616-3
ZZ2 = CMP-0077236-1
ZZ3 = CMP-0077237-1
ZZ4 = CMP-0077238-1

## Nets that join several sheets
1V2: TIDA-010992_02_Power (6 pins), TIDA-010992_04_BOOT_SoC power_CLK (C80.1 L5.1)
3V3: TIDA-010992_02_Power (12 pins), TIDA-010992_03_IO_Map_Debug (11 pins), TIDA-010992_04_BOOT_SoC power_CLK (32 pins), TIDA-010992_05_ETH_Conn (L9.2 L10.2 R108.2 R109.2), TIDA-010992_06_DRV_AXIS1 (C120.2 J4.7 R121.2 R122.2), TIDA-010992_07_DRV_AXIS2 (C135.2 J5.7 R139.2 R140.2), TIDA-010992_08_DRV_AXIS3 (C150.2 J6.7 R155.2 R156.2), TIDA-010992_09_DRV_AXIS4 (C165.2 J7.7 R171.2 R172.2), TIDA-010992_10_DRV_AXIS5 (C180.2 J8.7 R187.2 R188.2), TIDA-010992_11_DRV_AXIS6 (C195.2 J9.7 R203.2 R204.2), TIDA-010992_12_Connectors (C203.2 R214.2 U16.3)
24V: TIDA-010992_02_Power (22 pins), TIDA-010992_06_DRV_AXIS1 (5 pins), TIDA-010992_07_DRV_AXIS2 (5 pins), TIDA-010992_08_DRV_AXIS3 (5 pins), TIDA-010992_09_DRV_AXIS4 (5 pins), TIDA-010992_10_DRV_AXIS5 (5 pins), TIDA-010992_11_DRV_AXIS6 (5 pins), TIDA-010992_12_Connectors (R210.2)
GND: TIDA-010992_02_Power (63 pins), TIDA-010992_03_IO_Map_Debug (41 pins), TIDA-010992_04_BOOT_SoC power_CLK (48 pins), TIDA-010992_05_ETH_Conn (27 pins), TIDA-010992_06_DRV_AXIS1 (20 pins), TIDA-010992_07_DRV_AXIS2 (20 pins), TIDA-010992_08_DRV_AXIS3 (20 pins), TIDA-010992_09_DRV_AXIS4 (20 pins), TIDA-010992_10_DRV_AXIS5 (20 pins), TIDA-010992_11_DRV_AXIS6 (20 pins), TIDA-010992_12_Connectors (9 pins)
ADC_VREF: TIDA-010992_03_IO_Map_Debug (R43.2 R46.2 U5.5 U5.6), TIDA-010992_06_DRV_AXIS1 (R124.1), TIDA-010992_07_DRV_AXIS2 (R142.1), TIDA-010992_08_DRV_AXIS3 (R158.1), TIDA-010992_09_DRV_AXIS4 (R174.1), TIDA-010992_10_DRV_AXIS5 (R190.1), TIDA-010992_11_DRV_AXIS6 (R206.1)
BOOTPIN1: TIDA-010992_03_IO_Map_Debug (U4.A11), TIDA-010992_04_BOOT_SoC power_CLK (J2.1 R66.2)
CAN_TX: TIDA-010992_03_IO_Map_Debug (R42.2), TIDA-010992_12_Connectors (TP23.1 U16.1)
CANA_RX: TIDA-010992_03_IO_Map_Debug (U4.N11), TIDA-010992_12_Connectors (R217.1)
DRV_FLT_AX1: TIDA-010992_03_IO_Map_Debug (U4.G12), TIDA-010992_06_DRV_AXIS1 (R122.1 U10.12)
DRV_FLT_AX2: TIDA-010992_03_IO_Map_Debug (U4.G11), TIDA-010992_07_DRV_AXIS2 (R140.1 U11.12)
DRV_FLT_AX3: TIDA-010992_03_IO_Map_Debug (U4.G10), TIDA-010992_08_DRV_AXIS3 (R156.1 U12.12)
DRV_FLT_AX4: TIDA-010992_03_IO_Map_Debug (U4.B13), TIDA-010992_09_DRV_AXIS4 (R172.1 U13.12)
DRV_FLT_AX5: TIDA-010992_03_IO_Map_Debug (U4.B11), TIDA-010992_10_DRV_AXIS5 (R188.1 U14.12)
DRV_FLT_AX6: TIDA-010992_03_IO_Map_Debug (U4.G2), TIDA-010992_11_DRV_AXIS6 (R204.1 U15.12)
DRV_nSleep: TIDA-010992_03_IO_Map_Debug (U4.C10), TIDA-010992_06_DRV_AXIS1 (R113.1), TIDA-010992_07_DRV_AXIS2 (R131.1), TIDA-010992_08_DRV_AXIS3 (R147.1), TIDA-010992_09_DRV_AXIS4 (R163.1), TIDA-010992_10_DRV_AXIS5 (R179.1), TIDA-010992_11_DRV_AXIS6 (R195.1)
DRV_OFF: TIDA-010992_03_IO_Map_Debug (J14.2), TIDA-010992_06_DRV_AXIS1 (R112.1), TIDA-010992_07_DRV_AXIS2 (R130.1), TIDA-010992_08_DRV_AXIS3 (R146.1), TIDA-010992_09_DRV_AXIS4 (R162.1), TIDA-010992_10_DRV_AXIS5 (R178.1), TIDA-010992_11_DRV_AXIS6 (R194.1)
DRV_OFF_PMIC: TIDA-010992_02_Power (R221.2), TIDA-010992_03_IO_Map_Debug (J14.1)
ENC_SPI_CS1: TIDA-010992_03_IO_Map_Debug (U4.A10), TIDA-010992_04_BOOT_SoC power_CLK (R83.1), TIDA-010992_06_DRV_AXIS1 (R119.1)
ENC_SPI_CS2: TIDA-010992_03_IO_Map_Debug (U4.F11), TIDA-010992_04_BOOT_SoC power_CLK (R84.1), TIDA-010992_07_DRV_AXIS2 (R137.1)
ENC_SPI_CS3: TIDA-010992_03_IO_Map_Debug (U4.F10), TIDA-010992_04_BOOT_SoC power_CLK (R85.1), TIDA-010992_08_DRV_AXIS3 (R153.1)
ENC_SPI_CS4: TIDA-010992_03_IO_Map_Debug (U4.C12), TIDA-010992_04_BOOT_SoC power_CLK (R86.1), TIDA-010992_09_DRV_AXIS4 (R169.1)
ENC_SPI_CS5: TIDA-010992_03_IO_Map_Debug (U4.M12), TIDA-010992_04_BOOT_SoC power_CLK (R87.1), TIDA-010992_10_DRV_AXIS5 (R185.1)
ENC_SPI_CS6: TIDA-010992_03_IO_Map_Debug (U4.F12), TIDA-010992_04_BOOT_SoC power_CLK (R88.1), TIDA-010992_11_DRV_AXIS6 (R201.1)
ESC_I2C_SCL: TIDA-010992_03_IO_Map_Debug (U4.L9), TIDA-010992_04_BOOT_SoC power_CLK (R71.1 U7.6)
ESC_I2C_SDA: TIDA-010992_03_IO_Map_Debug (U4.N12), TIDA-010992_04_BOOT_SoC power_CLK (R72.1 U7.5)
ESC_LED_ERR: TIDA-010992_03_IO_Map_Debug (U4.L5), TIDA-010992_05_ETH_Conn (R110.1)
ESC_LED_RUN: TIDA-010992_03_IO_Map_Debug (U4.H11), TIDA-010992_05_ETH_Conn (R111.1)
ESC_MDIO: TIDA-010992_03_IO_Map_Debug (R19.1 U4.K12), TIDA-010992_04_BOOT_SoC power_CLK (R70.1)
ESC_PHY0_LINK: TIDA-010992_03_IO_Map_Debug (U4.J13), TIDA-010992_05_ETH_Conn (D5.2 R106.1 TP20.1 U8.30)
ESC_PHY_RST: TIDA-010992_03_IO_Map_Debug (U4.E9), TIDA-010992_05_ETH_Conn (R105.2 TP21.1 U8.32)
ESC_RX0_CLK: TIDA-010992_03_IO_Map_Debug (U4.D9), TIDA-010992_05_ETH_Conn (TP15.1 U8.19)
ESC_RX0_D0: TIDA-010992_03_IO_Map_Debug (U4.E8), TIDA-010992_05_ETH_Conn (U8.16)
ESC_RX0_D1: TIDA-010992_03_IO_Map_Debug (U4.K8), TIDA-010992_05_ETH_Conn (U8.15)
ESC_RX0_D2: TIDA-010992_03_IO_Map_Debug (U4.D8), TIDA-010992_05_ETH_Conn (R80.1 U8.14)
ESC_RX0_D3: TIDA-010992_03_IO_Map_Debug (U4.C8), TIDA-010992_05_ETH_Conn (R79.1 U8.13)
ESC_RX0_DV: TIDA-010992_03_IO_Map_Debug (U4.C9), TIDA-010992_05_ETH_Conn (TP16.1 U8.18)
ESC_RX0_ERR: TIDA-010992_03_IO_Map_Debug (U4.B9), TIDA-010992_05_ETH_Conn (R78.1 U8.20)
ESC_TX0_CLK: TIDA-010992_03_IO_Map_Debug (U4.A7), TIDA-010992_05_ETH_Conn (TP17.1 U8.22)
ESC_TX0_D0: TIDA-010992_03_IO_Map_Debug (U4.C7), TIDA-010992_05_ETH_Conn (U8.24)
ESC_TX0_D1: TIDA-010992_03_IO_Map_Debug (U4.C5), TIDA-010992_05_ETH_Conn (U8.25)
ESC_TX0_D2: TIDA-010992_03_IO_Map_Debug (U4.D5), TIDA-010992_05_ETH_Conn (U8.26)
ESC_TX0_D3: TIDA-010992_03_IO_Map_Debug (U4.E5), TIDA-010992_05_ETH_Conn (U8.27)
ESC_TX0_EN: TIDA-010992_03_IO_Map_Debug (U4.A8), TIDA-010992_04_BOOT_SoC power_CLK (R67.1), TIDA-010992_05_ETH_Conn (TP19.1 U8.23)
Fault_IN: TIDA-010992_02_Power (R220.2), TIDA-010992_03_IO_Map_Debug (R222.2)
FSIRXA_CLK: TIDA-010992_03_IO_Map_Debug (U4.K13), TIDA-010992_12_Connectors (R211.1)
FSIRXA_D0: TIDA-010992_03_IO_Map_Debug (U4.D10), TIDA-010992_12_Connectors (R212.1)
FSITXA_CLK_P1: TIDA-010992_03_IO_Map_Debug (R18.2), TIDA-010992_12_Connectors (J10.1)
FSITXA_D0_P1: TIDA-010992_03_IO_Map_Debug (R17.2), TIDA-010992_12_Connectors (J10.2)
I2CA_SCL: TIDA-010992_02_Power (U3.2), TIDA-010992_03_IO_Map_Debug (U4.H12), TIDA-010992_04_BOOT_SoC power_CLK (R68.1 U6.3)
I2CA_SDA: TIDA-010992_02_Power (U3.3), TIDA-010992_03_IO_Map_Debug (U4.A9), TIDA-010992_04_BOOT_SoC power_CLK (R69.1 U6.4)
I_A1: TIDA-010992_03_IO_Map_Debug (R48.1), TIDA-010992_06_DRV_AXIS1 (U10.27)
I_A2: TIDA-010992_03_IO_Map_Debug (R51.1), TIDA-010992_07_DRV_AXIS2 (U11.27)
I_A3: TIDA-010992_03_IO_Map_Debug (R54.1), TIDA-010992_08_DRV_AXIS3 (U12.27)
I_A4: TIDA-010992_03_IO_Map_Debug (R57.1), TIDA-010992_09_DRV_AXIS4 (U13.27)
I_A5: TIDA-010992_03_IO_Map_Debug (R60.1), TIDA-010992_10_DRV_AXIS5 (U14.27)
I_A6: TIDA-010992_03_IO_Map_Debug (R63.1), TIDA-010992_11_DRV_AXIS6 (U15.27)
I_B1: TIDA-010992_03_IO_Map_Debug (R49.1), TIDA-010992_06_DRV_AXIS1 (U10.26)
I_B2: TIDA-010992_03_IO_Map_Debug (R52.1), TIDA-010992_07_DRV_AXIS2 (U11.26)
I_B3: TIDA-010992_03_IO_Map_Debug (R55.1), TIDA-010992_08_DRV_AXIS3 (U12.26)
I_B4: TIDA-010992_03_IO_Map_Debug (R58.1), TIDA-010992_09_DRV_AXIS4 (U13.26)
I_B5: TIDA-010992_03_IO_Map_Debug (R61.1), TIDA-010992_10_DRV_AXIS5 (TP24.1 U14.26)
I_B6: TIDA-010992_03_IO_Map_Debug (R64.1), TIDA-010992_11_DRV_AXIS6 (U15.26)
I_C1: TIDA-010992_03_IO_Map_Debug (R50.1), TIDA-010992_06_DRV_AXIS1 (U10.25)
I_C2: TIDA-010992_03_IO_Map_Debug (R53.1), TIDA-010992_07_DRV_AXIS2 (U11.25)
I_C3: TIDA-010992_03_IO_Map_Debug (R56.1), TIDA-010992_08_DRV_AXIS3 (U12.25)
I_C4: TIDA-010992_03_IO_Map_Debug (R59.1), TIDA-010992_09_DRV_AXIS4 (U13.25)
I_C5: TIDA-010992_03_IO_Map_Debug (R62.1), TIDA-010992_10_DRV_AXIS5 (TP25.1 U14.25)
I_C6: TIDA-010992_03_IO_Map_Debug (R65.1), TIDA-010992_11_DRV_AXIS6 (U15.25)
MCU_CLK_25M: TIDA-010992_03_IO_Map_Debug (U4.D13), TIDA-010992_04_BOOT_SoC power_CLK (R73.2)
MDC: TIDA-010992_03_IO_Map_Debug (R32.2), TIDA-010992_05_ETH_Conn (U8.12)
MDIO: TIDA-010992_03_IO_Map_Debug (R19.2), TIDA-010992_05_ETH_Conn (U8.11)
PHY0_25MHZ_CLK: TIDA-010992_04_BOOT_SoC power_CLK (R74.2), TIDA-010992_05_ETH_Conn (C108.1 TP18.1 U8.9)
PMIC_NRST: TIDA-010992_02_Power (U3.4), TIDA-010992_03_IO_Map_Debug (R39.1)
PWM_A1_H: TIDA-010992_03_IO_Map_Debug (U4.E7), TIDA-010992_06_DRV_AXIS1 (R114.1)
PWM_A1_L: TIDA-010992_03_IO_Map_Debug (U4.A6), TIDA-010992_06_DRV_AXIS1 (R115.1)
PWM_A2_H: TIDA-010992_03_IO_Map_Debug (U4.A5), TIDA-010992_07_DRV_AXIS2 (R132.1)
PWM_A2_L: TIDA-010992_03_IO_Map_Debug (U4.B5), TIDA-010992_07_DRV_AXIS2 (R133.1)
PWM_A3_H: TIDA-010992_03_IO_Map_Debug (U4.B1), TIDA-010992_08_DRV_AXIS3 (R148.1)
PWM_A3_L: TIDA-010992_03_IO_Map_Debug (U4.C1), TIDA-010992_08_DRV_AXIS3 (R149.1)
PWM_A4_H: TIDA-010992_03_IO_Map_Debug (U4.D3), TIDA-010992_09_DRV_AXIS4 (R164.1)
PWM_A4_L: TIDA-010992_03_IO_Map_Debug (U4.D1), TIDA-010992_09_DRV_AXIS4 (R165.1)
PWM_A5_H: TIDA-010992_03_IO_Map_Debug (U4.D7), TIDA-010992_10_DRV_AXIS5 (R180.1)
PWM_A5_L: TIDA-010992_03_IO_Map_Debug (U4.B8), TIDA-010992_10_DRV_AXIS5 (R181.1)
PWM_A6_H: TIDA-010992_03_IO_Map_Debug (U4.B4), TIDA-010992_11_DRV_AXIS6 (R196.1)
PWM_A6_L: TIDA-010992_03_IO_Map_Debug (U4.A4), TIDA-010992_11_DRV_AXIS6 (R197.1)
PWM_B1_H: TIDA-010992_03_IO_Map_Debug (U4.B6), TIDA-010992_06_DRV_AXIS1 (R117.1)
PWM_B1_L: TIDA-010992_03_IO_Map_Debug (U4.C6), TIDA-010992_06_DRV_AXIS1 (R118.1)
PWM_B2_H: TIDA-010992_03_IO_Map_Debug (U4.E3), TIDA-010992_07_DRV_AXIS2 (R135.1)
PWM_B2_L: TIDA-010992_03_IO_Map_Debug (U4.F3), TIDA-010992_07_DRV_AXIS2 (R136.1)
PWM_B3_H: TIDA-010992_03_IO_Map_Debug (U4.C2), TIDA-010992_08_DRV_AXIS3 (R151.1)
PWM_B3_L: TIDA-010992_03_IO_Map_Debug (U4.C3), TIDA-010992_08_DRV_AXIS3 (R152.1)
PWM_B4_H: TIDA-010992_03_IO_Map_Debug (U4.E1), TIDA-010992_09_DRV_AXIS4 (R167.1)
PWM_B4_L: TIDA-010992_03_IO_Map_Debug (U4.E2), TIDA-010992_09_DRV_AXIS4 (R168.1)
PWM_B5_H: TIDA-010992_03_IO_Map_Debug (U4.L10), TIDA-010992_10_DRV_AXIS5 (R183.1)
PWM_B5_L: TIDA-010992_03_IO_Map_Debug (U4.D11), TIDA-010992_10_DRV_AXIS5 (R184.1)
PWM_B6_H: TIDA-010992_03_IO_Map_Debug (U4.A3), TIDA-010992_11_DRV_AXIS6 (R199.1)
PWM_B6_L: TIDA-010992_03_IO_Map_Debug (U4.A2), TIDA-010992_11_DRV_AXIS6 (R200.1)
PWM_C1_H: TIDA-010992_03_IO_Map_Debug (U4.D6), TIDA-010992_06_DRV_AXIS1 (R123.1)
PWM_C1_L: TIDA-010992_03_IO_Map_Debug (U4.E6), TIDA-010992_06_DRV_AXIS1 (R125.1)
PWM_C2_H: TIDA-010992_03_IO_Map_Debug (U4.B3), TIDA-010992_07_DRV_AXIS2 (R141.1)
PWM_C2_L: TIDA-010992_03_IO_Map_Debug (U4.B2), TIDA-010992_07_DRV_AXIS2 (R143.1)
PWM_C3_H: TIDA-010992_03_IO_Map_Debug (U4.C4), TIDA-010992_08_DRV_AXIS3 (R157.1)
PWM_C3_L: TIDA-010992_03_IO_Map_Debug (U4.D4), TIDA-010992_08_DRV_AXIS3 (R159.1)
PWM_C4_H: TIDA-010992_03_IO_Map_Debug (U4.D2), TIDA-010992_09_DRV_AXIS4 (R173.1)
PWM_C4_L: TIDA-010992_03_IO_Map_Debug (U4.F2), TIDA-010992_09_DRV_AXIS4 (R175.1)
PWM_C5_H: TIDA-010992_03_IO_Map_Debug (U4.K9), TIDA-010992_10_DRV_AXIS5 (R189.1)
PWM_C5_L: TIDA-010992_03_IO_Map_Debug (U4.L8), TIDA-010992_10_DRV_AXIS5 (R191.1)
PWM_C6_H: TIDA-010992_03_IO_Map_Debug (U4.K7), TIDA-010992_11_DRV_AXIS6 (R205.1)
PWM_C6_L: TIDA-010992_03_IO_Map_Debug (U4.N8), TIDA-010992_11_DRV_AXIS6 (R207.1)
SPIA_CLK_AX1_2: TIDA-010992_03_IO_Map_Debug (R29.2), TIDA-010992_06_DRV_AXIS1 (J4.11), TIDA-010992_07_DRV_AXIS2 (J5.11)
SPIA_PICO_AX1_2: TIDA-010992_03_IO_Map_Debug (R27.2), TIDA-010992_06_DRV_AXIS1 (J4.10), TIDA-010992_07_DRV_AXIS2 (J5.10)
SPIA_POCI_AX12: TIDA-010992_03_IO_Map_Debug (R219.2 U4.L7), TIDA-010992_06_DRV_AXIS1 (R116.1), TIDA-010992_07_DRV_AXIS2 (R134.1)
SPIB_CLK_AX3_4: TIDA-010992_03_IO_Map_Debug (R35.2), TIDA-010992_08_DRV_AXIS3 (J6.11), TIDA-010992_09_DRV_AXIS4 (J7.11)
SPIB_PICO_AX3_4: TIDA-010992_03_IO_Map_Debug (R34.2), TIDA-010992_08_DRV_AXIS3 (J6.10), TIDA-010992_09_DRV_AXIS4 (J7.10)
SPIB_POCI_AX34: TIDA-010992_03_IO_Map_Debug (R218.2 U4.G3), TIDA-010992_08_DRV_AXIS3 (R150.1), TIDA-010992_09_DRV_AXIS4 (R166.1)
SPIC_CLK_AX5_6: TIDA-010992_03_IO_Map_Debug (R38.2), TIDA-010992_10_DRV_AXIS5 (J8.11), TIDA-010992_11_DRV_AXIS6 (J9.11)
SPIC_PICO_AX5_6: TIDA-010992_03_IO_Map_Debug (R37.2), TIDA-010992_10_DRV_AXIS5 (J8.10), TIDA-010992_11_DRV_AXIS6 (J9.10)
SPIC_POCI_AX56: TIDA-010992_03_IO_Map_Debug (R128.2 U4.A12), TIDA-010992_10_DRV_AXIS5 (R182.1), TIDA-010992_11_DRV_AXIS6 (R198.1)
SPID_CLK_DRVCFG: TIDA-010992_03_IO_Map_Debug (R30.2), TIDA-010992_06_DRV_AXIS1 (U10.22), TIDA-010992_07_DRV_AXIS2 (U11.22), TIDA-010992_08_DRV_AXIS3 (U12.22), TIDA-010992_09_DRV_AXIS4 (U13.22), TIDA-010992_10_DRV_AXIS5 (U14.22), TIDA-010992_11_DRV_AXIS6 (U15.22)
SPID_CS1_DRV: TIDA-010992_03_IO_Map_Debug (U4.F13), TIDA-010992_06_DRV_AXIS1 (R121.1 U10.23)
SPID_CS2_DRV: TIDA-010992_03_IO_Map_Debug (U4.M13), TIDA-010992_07_DRV_AXIS2 (R139.1 U11.23)
SPID_CS3_DRV: TIDA-010992_03_IO_Map_Debug (U4.J11), TIDA-010992_08_DRV_AXIS3 (R155.1 U12.23)
SPID_CS4_DRV: TIDA-010992_03_IO_Map_Debug (U4.J10), TIDA-010992_09_DRV_AXIS4 (R171.1 U13.23)
SPID_CS5_DRV: TIDA-010992_03_IO_Map_Debug (U4.H13), TIDA-010992_10_DRV_AXIS5 (R187.1 U14.23)
SPID_CS6_DRV: TIDA-010992_03_IO_Map_Debug (U4.G13), TIDA-010992_11_DRV_AXIS6 (R203.1 U15.23)
SPID_PICO_DRVCFG: TIDA-010992_03_IO_Map_Debug (R31.2), TIDA-010992_06_DRV_AXIS1 (U10.21), TIDA-010992_07_DRV_AXIS2 (U11.21), TIDA-010992_08_DRV_AXIS3 (U12.21), TIDA-010992_09_DRV_AXIS4 (U13.21), TIDA-010992_10_DRV_AXIS5 (U14.21), TIDA-010992_11_DRV_AXIS6 (U15.21)
SPID_POCI_DRV: TIDA-010992_03_IO_Map_Debug (R126.2 U4.M7), TIDA-010992_06_DRV_AXIS1 (R120.1), TIDA-010992_07_DRV_AXIS2 (R138.1), TIDA-010992_08_DRV_AXIS3 (R154.1), TIDA-010992_09_DRV_AXIS4 (R170.1), TIDA-010992_10_DRV_AXIS5 (R186.1), TIDA-010992_11_DRV_AXIS6 (R202.1)
Temp_PCB: TIDA-010992_03_IO_Map_Debug (R45.1), TIDA-010992_12_Connectors (R214.1 RT1.2)
UART_TX: TIDA-010992_03_IO_Map_Debug (R40.2), TIDA-010992_12_Connectors (J13.1)
UARTA_RX: TIDA-010992_03_IO_Map_Debug (U4.C11), TIDA-010992_04_BOOT_SoC power_CLK (R89.1), TIDA-010992_12_Connectors (R216.1)
VBUS_SENSE: TIDA-010992_03_IO_Map_Debug (R44.1), TIDA-010992_12_Connectors (C202.1 R210.1 R213.2)

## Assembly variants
001: not fitted C? FID1 FID2 FID3 R39 R87 R88 R89 R92 R102 R220 R221 R222 R? R? TP5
